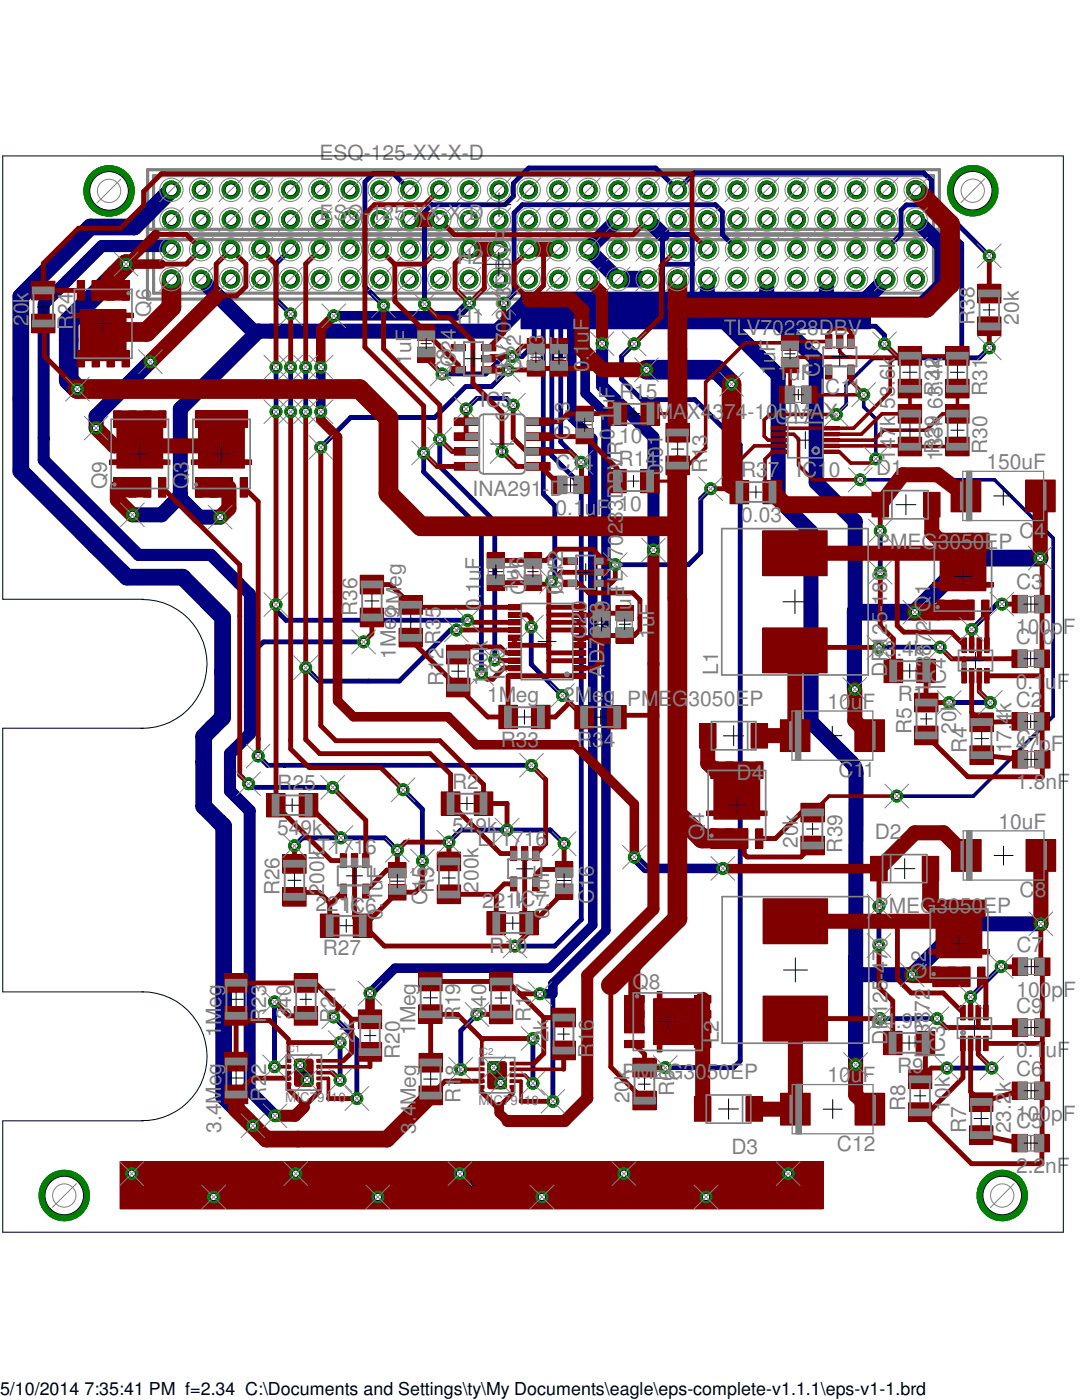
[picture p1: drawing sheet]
<svg xmlns="http://www.w3.org/2000/svg" width="216mm" height="279mm" viewBox="0 0 216 279" stroke-linecap="round" stroke-linejoin="round" font-family="sans-serif">
<defs><g id="words">
<g font-size="4.2" fill="#808080">
<text x="63.8" y="32">ESQ-125-XX-X-D</text>
<text x="63.8" y="43.8">ESQ-125-XX-X-D</text>
<text x="91.2" y="52.7">H2</text>
<text x="5.7" y="65.1" transform="rotate(-90 5.7 65.1)">20k</text>
<text x="14.6" y="66" transform="rotate(-90 14.6 66)">R24</text>
<text x="30.1" y="63.2" transform="rotate(-90 30.1 63.2)">Q6</text>
<text x="91.2" y="64.6">H1</text>
<text x="194.4" y="64.8" transform="rotate(-90 194.4 64.8)">R38</text>
<text x="203.3" y="64.8" transform="rotate(-90 203.3 64.8)">20k</text>
<text x="144.4" y="66.8">TLV70228DBV</text>
<text x="82" y="72.8" transform="rotate(-90 82 72.8)">1uF</text>
<text x="90" y="76.1" transform="rotate(-90 90 76.1)">IC8</text>
<text x="91" y="73.3" transform="rotate(-90 91 73.3)">C24</text>
<text x="101.9" y="76.1" transform="rotate(-90 101.9 76.1)">TLV70233DBVR</text>
<text x="104" y="74.3" transform="rotate(-90 104 74.3)">C22</text>
<text x="108.5" y="74.3" transform="rotate(-90 108.5 74.3)">C23</text>
<text x="112.9" y="74.3" transform="rotate(-90 112.9 74.3)">1uF</text>
<text x="117.5" y="74.3" transform="rotate(-90 117.5 74.3)">0.1uF</text>
<text x="154.6" y="74.8" transform="rotate(-90 154.6 74.8)">1uF</text>
<text x="155.1" y="75.8">1uF</text>
<text x="163.6" y="75.3" transform="rotate(-90 163.6 75.3)">C18</text>
<text x="95.8" y="81.2">IC5</text>
<text x="123.5" y="79.6">R15</text>
<text x="130.9" y="83.5">MAX4374-10UMAX</text>
<text x="163.5" y="78.7">IC11</text>
<text x="178.6" y="81.6" transform="rotate(-90 178.6 81.6)">53.6k</text>
<text x="187.5" y="79" transform="rotate(-90 187.5 79)">R32</text>
<text x="197" y="79" transform="rotate(-90 197 79)">R31</text>
<text x="113.7" y="87.8" transform="rotate(-90 113.7 87.8)">C13</text>
<text x="122.6" y="87.8" transform="rotate(-90 122.6 87.8)">0.1uF</text>
<text x="123.5" y="88.5">10</text>
<text x="154.6" y="84.7">C17</text>
<text x="110.8" y="93.8">C14</text>
<text x="123.4" y="93">R14</text>
<text x="132.2" y="94.8" transform="rotate(-90 132.2 94.8)">0.01</text>
<text x="141.1" y="94.3" transform="rotate(-90 141.1 94.3)">R13</text>
<text x="147.9" y="95.3">R37</text>
<text x="158.9" y="95.3">IC10</text>
<text x="174.8" y="94.8">D1</text>
<text x="178.6" y="92" transform="rotate(-90 178.6 92)">147k</text>
<text x="187.5" y="90.6" transform="rotate(-90 187.5 90.6)">R29</text>
<text x="188.1" y="92" transform="rotate(-90 188.1 92)">133k 63.4k</text>
<text x="196.8" y="93.6">150uF</text>
<text x="197" y="90.6" transform="rotate(-90 197 90.6)">R30</text>
<text x="21.3" y="97.6" transform="rotate(-90 21.3 97.6)">Q9</text>
<text x="37.6" y="97.6" transform="rotate(-90 37.6 97.6)">Q3</text>
<text x="94.3" y="99">INA291-D</text>
<text x="123.4" y="102">10</text>
<text x="110.8" y="102.7">0.1uF</text>
<text x="147.9" y="104.1">0.03</text>
<text x="203.4" y="107.3">C4</text>
<text x="174.8" y="109.6">PMEG3050EP</text>
<text x="103.4" y="118.3" transform="rotate(-90 103.4 118.3)">1uF</text>
<text x="104.9" y="118.8" transform="rotate(-90 104.9 118.8)">C26</text>
<text x="112.3" y="118.8" transform="rotate(-90 112.3 118.8)">C25</text>
<text x="112.4" y="118.7" transform="rotate(-90 112.4 118.7)">IC12</text>
<text x="124.3" y="118.7" transform="rotate(-90 124.3 118.7)">TLV70233DBVR</text>
<text x="202.7" y="117.6">C3</text>
<text x="71.2" y="122.9" transform="rotate(-90 71.2 122.9)">R36</text>
<text x="80.1" y="122.9" transform="rotate(-90 80.1 122.9)">2Meg</text>
<text x="96" y="121.8" transform="rotate(-90 96 121.8)">0.1uF</text>
<text x="185.6" y="122.1" transform="rotate(-90 185.6 122.1)">Q1</text>
<text x="79" y="131.4" transform="rotate(-90 79 131.4)">1Meg</text>
<text x="117" y="127.6" transform="rotate(-90 117 127.6)">C20</text>
<text x="121.6" y="127.6" transform="rotate(-90 121.6 127.6)">C19</text>
<text x="125.9" y="127.6" transform="rotate(-90 125.9 127.6)">0.1uF</text>
<text x="130.6" y="127.6" transform="rotate(-90 130.6 127.6)">1uF</text>
<text x="174.2" y="130.9">63.4k</text>
<text x="202.7" y="128.5">C10</text>
<text x="202.7" y="126.5">100pF</text>
<text x="88.5" y="136.9" transform="rotate(-90 88.5 136.9)">R12R35</text>
<text x="97.4" y="136.9" transform="rotate(-90 97.4 136.9)">100k</text>
<text x="100.7" y="135.8" transform="rotate(-90 100.7 135.8)">IC9</text>
<text x="120.6" y="135.3" transform="rotate(-90 120.6 135.3)">AD7998</text>
<text x="143.3" y="134.7" transform="rotate(-90 143.3 134.7)">L1</text>
<text x="177" y="135.1" transform="rotate(-90 177 135.1)">DR125-180</text>
<text x="185.7" y="137.8" transform="rotate(-90 185.7 137.8)">LT3872</text>
<text x="188.7" y="137.8" transform="rotate(-90 188.7 137.8)">IC4</text>
<text x="202.7" y="137.4">0.1uF</text>
<text x="97.2" y="140.1">1Meg</text>
<text x="112.4" y="140.1">2Meg</text>
<text x="125.1" y="140.9">PMEG3050EP</text>
<text x="165.1" y="141.4">10uF</text>
<text x="179.2" y="139.8">R1</text>
<text x="202.7" y="141">C2</text>
<text x="99.9" y="149.1">R33</text>
<text x="115.1" y="149.1">R34</text>
<text x="181.9" y="146.5" transform="rotate(-90 181.9 146.5)">R5</text>
<text x="190.8" y="146.5" transform="rotate(-90 190.8 146.5)">20k</text>
<text x="202.7" y="149.9">47pF</text>
<text x="202.8" y="148.6">C1</text>
<text x="147" y="155.7">D4</text>
<text x="167.3" y="155.2">C11</text>
<text x="192.9" y="150.4" transform="rotate(-90 192.9 150.4)">R4</text>
<text x="201.8" y="150.4" transform="rotate(-90 201.8 150.4)">17.4k</text>
<text x="55.3" y="157.7">R25</text>
<text x="90.2" y="157.4">R2</text>
<text x="202.8" y="157.5">1.8nF</text>
<text x="55.3" y="166.6">549k</text>
<text x="90.2" y="166.3">549k</text>
<text x="140.5" y="167.7" transform="rotate(-90 140.5 167.7)">Q4</text>
<text x="174.6" y="167.4">D2</text>
<text x="199.3" y="165.4">10uF</text>
<text x="61.3" y="170.3">LT1716</text>
<text x="95.3" y="168.9">LT1716</text>
<text x="159.2" y="169.2" transform="rotate(-90 159.2 169.2)">20k</text>
<text x="168.1" y="170.1" transform="rotate(-90 168.1 170.1)">R39</text>
<text x="55.8" y="178.7" transform="rotate(-90 55.8 178.7)">R26</text>
<text x="64.7" y="178.7" transform="rotate(-90 64.7 178.7)">200k</text>
<text x="86.6" y="178.2" transform="rotate(-90 86.6 178.2)">R3</text>
<text x="95.5" y="178.2" transform="rotate(-90 95.5 178.2)">200k</text>
<text x="203.5" y="179.1">C8</text>
<text x="62.9" y="181.8">221k</text>
<text x="68.7" y="182.2">IC6</text>
<text x="76.3" y="183.6" transform="rotate(-90 76.3 183.6)">0.1uF</text>
<text x="85.2" y="180.6" transform="rotate(-90 85.2 180.6)">C15</text>
<text x="96.2" y="181.2">221k</text>
<text x="102.7" y="180.8">IC7</text>
<text x="109.6" y="183.5" transform="rotate(-90 109.6 183.5)">0.1uF</text>
<text x="118.5" y="180.4" transform="rotate(-90 118.5 180.4)">C16</text>
<text x="174.6" y="182.3">PMEG3050EP</text>
<text x="64.4" y="190.7">R27</text>
<text x="97.6" y="190.2">R10</text>
<text x="202.8" y="189.9">C7</text>
<text x="126.2" y="197.4">Q8</text>
<text x="184.8" y="195.3" transform="rotate(-90 184.8 195.3)">Q2</text>
<text x="58.1" y="203.5" transform="rotate(-90 58.1 203.5)">340</text>
<text x="91.8" y="203.8" transform="rotate(-90 91.8 203.8)">R19</text>
<text x="97" y="203.2" transform="rotate(-90 97 203.2)">340</text>
<text x="105.9" y="203.9" transform="rotate(-90 105.9 203.9)">R17</text>
<text x="202.8" y="202.1">C9</text>
<text x="202.8" y="198.9">100pF</text>
<text x="44.2" y="206.9" transform="rotate(-90 44.2 206.9)">1Meg</text>
<text x="53.1" y="204.1" transform="rotate(-90 53.1 204.1)">R23</text>
<text x="67" y="204.1" transform="rotate(-90 67 204.1)">R21</text>
<text x="70.9" y="208.2" transform="rotate(-90 70.9 208.2)">2k</text>
<text x="82.9" y="206.6" transform="rotate(-90 82.9 206.6)">1Meg</text>
<text x="109.5" y="207.9" transform="rotate(-90 109.5 207.9)">2k</text>
<text x="143.4" y="208.2" transform="rotate(-90 143.4 208.2)">L2</text>
<text x="174.1" y="205.1">64.9k</text>
<text x="177.1" y="208.5" transform="rotate(-90 177.1 208.5)">DR125-470</text>
<text x="79.8" y="211.4" transform="rotate(-90 79.8 211.4)">R20</text>
<text x="118.4" y="211.1" transform="rotate(-90 118.4 211.1)">R16</text>
<text x="124.1" y="215.4">PMEG3050EP</text>
<text x="165.1" y="215.9">10uF</text>
<text x="179" y="214.1">R9</text>
<text x="185.5" y="211.1" transform="rotate(-90 185.5 211.1)">LT3872</text>
<text x="188.5" y="211.1" transform="rotate(-90 188.5 211.1)">IC3</text>
<text x="202.8" y="214.7">C6</text>
<text x="202.8" y="211">0.1uF</text>
<text x="53.1" y="219.8" transform="rotate(-90 53.1 219.8)">R22</text>
<text x="91.9" y="220" transform="rotate(-90 91.9 220)">R18</text>
<text x="125.6" y="220.2" transform="rotate(-90 125.6 220.2)">20k</text>
<text x="134.5" y="218.7" transform="rotate(-90 134.5 218.7)">R6</text>
<text x="180.6" y="221.7" transform="rotate(-90 180.6 221.7)">R8</text>
<text x="189.5" y="221.7" transform="rotate(-90 189.5 221.7)">10k</text>
<text x="44.2" y="226.1" transform="rotate(-90 44.2 226.1)">3.4Meg</text>
<text x="83" y="226.3" transform="rotate(-90 83 226.3)">3.4Meg</text>
<text x="192.8" y="226.2" transform="rotate(-90 192.8 226.2)">R7</text>
<text x="201.7" y="226.2" transform="rotate(-90 201.7 226.2)">23.2k</text>
<text x="202.7" y="225.2">C5</text>
<text x="202.8" y="223.6">100pF</text>
<text x="146" y="230.3">D3</text>
<text x="167" y="229.7">C12</text>
<text x="202.7" y="234.1">2.2nF</text>
</g>
<text font-size="3.6" x="0" y="278.4">5/10/2014 7:35:41 PM f=2.34 C:\Documents and Settings\ty\My Documents\eagle\eps-complete-v1.1.1\eps-v1-1.brd</text>
<g font-size="2.7" fill="#808080">
<text x="56.9" y="219.9">MIC79110</text>
<text x="95.5" y="220.4">MIC79110</text>
</g>
<g font-size="2" fill="#808080">
<text x="56.9" y="210">IC1</text>
<text x="95.5" y="210.5">IC2</text>
</g>
</g></defs>
<path d="M30.6 35.1h155.7v11.6h-155.7zM30.6 46.9h155.7v11.6h-155.7zM187.5 45.8h-158.1v13.9h158.1v-25.8h-158v13.9h158" fill="none" stroke="#808080" stroke-width=".63"/>
<path d="M104 58.3h69.7v7.3h-69.7z" fill-rule="evenodd" fill="#000080"/>
<path d="M104 58.3h69.7v7.3h-69.7z" fill="none" stroke="#000080" stroke-width=".2"/>
<g fill="none" stroke="#000080" stroke-width=".97">
<path d="M81.7 37.9l-3.3-3.3h-3.9l-1.7 1.7v20.9l3.7 3.8M58 49.7l-2.9 3v7l2.9 3M105.7 59.6v.9l.9 .9v7.3l-2.4 2.5h-3.7l-3.6 3.4h-8.7M119.7 58.8h-13.1l-1.4 1.3M123.3 55.6v.2M132.2 58.8v-12h5.9v12M132.2 52.7h6M138.1 58.8h-27.7l1.5 1.5v27.9l4.1 4M138.1 58.8l3.5 3.4h1M147.1 49.7l-3-2.9v-4.6l-1.4-1.3h-38.5l-1.6 1.6v16l-2.1 2M176.8 49.7l3-3v-4.7l1-1.1h3.4l7.7 7.7v22.8M197.4 51.1l-11.6-11.6v-3.5l-1.5-1.5h-45.7l-3.4 3.4-4.3-4.4h-25.4l-3.1 3.1v2.6l-1.6 1.7h-14.7l-1.4 1.4v18.4"/>
<path d="M55.1 73.3v8.9M58 73.3v8.9M61 73.3v8.9M93.7 60.5h.1M101.4 73.8l-3.3 3.3h-5.2l-6.2 6.2h-16.7l-6 6M106.6 63.9h3.5v27l5.9 5.9v86.7l-5.3 5.3h-8M108.4 63.9v34.7l2.3 2.3v14.5l-.6 .6M111.9 60.6h2l.3 .2h2.6M126.5 68.6l-2.5 2.5v4.6l4.1 4.1h10.5l9.1 9v123l-1.4 1.3h-13.5M142.8 62h11.8l1.8 1.8M164 60.7l4.4 4.4h6.3l1.8 1.8v1.7M191.9 71.4v.1"/>
<path d="M197.4 69.4l-2 2h-3.5M84.5 90.4v3.8l11.6 11.5v28.7M87.8 87.7v5.4l10.9 11v27.6M102.4 80.9l-1.4-1.4h-5.8l-2.2 2.1M141.8 97.5l-2 2v10.7l-2.4 2.5h-14.6M175.6 106v8.2M55.1 120.7v1.1l2 2h36.2M72.6 128.1h-20l-2.3 2.2h-.4M91.1 125.7h-1.2l-10.2 10.2h-16l-2.7-2.7M106 125.1v7.5l6.2 6.2M170.5 137.5l.1 .1M170.5 121.8h.1v.4"/>
<path d="M170.6 122.2h.1M173.7 122h-2.8l-.3 .2M187.6 129.2h-12.3M199.9 120.6h-1l-5 5M49.6 156.4l.7 .7h16.1M51.5 150.9l1.9 1.8h52.6M80.4 157.6l3.9 3.9v10.3M189.4 140.2h8.2M58.8 168.8l1.6-1.6h16.4l2.5 2.5M89.6 168.1l2.3-2.4h17.9l2.8 2.7M54.8 199.9v13M110.3 198.3v21.5"/>
<path d="M175.4 180.8v7.9M199.8 192.9l-6.1 6.1M66.6 202.9l4.6 4.7v11.6M67.9 208.1v7.5M95.2 202.4l-3.3 3.3v7.7M106.3 207.3v8.9M175.6 203.3h11.4M188.9 213.1h9"/>
</g>
<path d="M34.2 49.7l-.7-.6h-13.2l-11.6 11.6v31.1l18.9 18.9h14.5l7.8 7.9v27.8l-4 4v7.5l3.9 3.9v55.8l5.1 5.1M120.1 68.6v8.4l10.3 10.2v22.6" fill="none" stroke="#000080" stroke-width="2.4"/>
<g fill="none" stroke="#000080" stroke-width="3">
<path d="M40.1 55.7l10.4 10.4h48.7l6-6M123.3 43.8l-6 5.9 6 6.1M129.2 43.8l3 3M141.1 55.7v3.4l2.4 2.3M145.2 59.9l-.9 .8M153 55.7v4.2l.8 .8M164.9 55.7v4.8l.2 .2M176.8 55.7l-5 5M182.7 43.8l5.3 5.3v7.7l-3.9 3.9h-39.8M30 72.2l-10.8 10.9v2.3M51.6 66.1l-15.6 15.5v17.9l3.7 3.7h4.2M142.6 62.2l12.7 12.7v24.7l6.5 6.5v38l8.1 8.1a2.79 2.79 0 0 1 .9 2.1l-.1 58.2"/>
<path d="M142.6 62.2h10.7l9.6 9.6v24.5l7.7 7.8v17.7M143.5 61.4l-.9 .8M144.3 60.7l-.8 .7M36 98.9l-3.8 3.8h-5.8M170.5 121.8v15.7M207.7 184.4h-15.5l-10.2 10.1h-11.3"/>
</g>
<path d="M34.2 37.9l-7.4 7.4h-8.8l-13.9 13.9v34.8l21.2 21.2h11.1l8 8v20l-3.8 3.8v13.9l4 3.9v54l5.9 5.9M123.3 55.7h5.9M207.6 111.4h-14.3l-10.8 10.8h-11.9" fill="none" stroke="#000080" stroke-width="3.3"/>
<path d="M64 73.3v8.9M93.7 60.5l-2.6 2.5h-24.5M114.1 60.7v22.7l4.2 4.1v97.1l-8.6 8.6h-30.9l-5 5M116.8 60.8v17.7l4.1 4.1v103.1l-10.6 10.6v2h-2.6M126.6 171.1l2.2 2.2h15.4" fill="none" stroke="#000080" stroke-width="1.9"/>
<path d="M54.9 66l-.8 .1M172.3 78.8v2.4l2.5 2.4v8M191.9 71.5h-17.7l-5.4 5.4v3.9l-1.9 1.9M171.7 95.8h26.8l11.6 11.6v35.6l-15.9 15.9h-15.3" fill="none" stroke="#000080" stroke-width=".72"/>
<path d="M23 54.8l-9.3 9.3v11.8l1.8 1.7M23 54.8h.1M25.1 52.7l-2 2.1M129 73.8h14.1l2.9 2.9" fill="none" stroke="#000080" stroke-width="3.9"/>
<circle cx="34.2" cy="43.8" r="1.78" fill="#008000"/>
<circle cx="34.2" cy="43.8" r="1.78" fill="none" stroke="#008000" stroke-width=".2"/>
<circle cx="34.2" cy="43.8" r="1.18" fill="#fff"/>
<circle cx="34.2" cy="43.8" r="1.18" fill="none" stroke="#000" stroke-width=".2"/>
<circle cx="34.2" cy="37.9" r="1.78" fill="#008000"/>
<circle cx="34.2" cy="37.9" r="1.78" fill="none" stroke="#008000" stroke-width=".2"/>
<circle cx="34.2" cy="37.9" r="1.18" fill="#fff"/>
<circle cx="34.2" cy="37.9" r="1.18" fill="none" stroke="#000" stroke-width=".2"/>
<circle cx="40.1" cy="43.8" r="1.78" fill="#008000"/>
<circle cx="40.1" cy="43.8" r="1.78" fill="none" stroke="#008000" stroke-width=".2"/>
<circle cx="40.1" cy="43.8" r="1.18" fill="#fff"/>
<circle cx="40.1" cy="43.8" r="1.18" fill="none" stroke="#000" stroke-width=".2"/>
<circle cx="40.1" cy="37.9" r="1.78" fill="#008000"/>
<circle cx="40.1" cy="37.9" r="1.78" fill="none" stroke="#008000" stroke-width=".2"/>
<circle cx="40.1" cy="37.9" r="1.18" fill="#fff"/>
<circle cx="40.1" cy="37.9" r="1.18" fill="none" stroke="#000" stroke-width=".2"/>
<circle cx="46.1" cy="43.8" r="1.78" fill="#008000"/>
<circle cx="46.1" cy="43.8" r="1.78" fill="none" stroke="#008000" stroke-width=".2"/>
<circle cx="46.1" cy="43.8" r="1.18" fill="#fff"/>
<circle cx="46.1" cy="43.8" r="1.18" fill="none" stroke="#000" stroke-width=".2"/>
<circle cx="46.1" cy="37.9" r="1.78" fill="#008000"/>
<circle cx="46.1" cy="37.9" r="1.78" fill="none" stroke="#008000" stroke-width=".2"/>
<circle cx="46.1" cy="37.9" r="1.18" fill="#fff"/>
<circle cx="46.1" cy="37.9" r="1.18" fill="none" stroke="#000" stroke-width=".2"/>
<circle cx="52" cy="43.8" r="1.78" fill="#008000"/>
<circle cx="52" cy="43.8" r="1.78" fill="none" stroke="#008000" stroke-width=".2"/>
<circle cx="52" cy="43.8" r="1.18" fill="#fff"/>
<circle cx="52" cy="43.8" r="1.18" fill="none" stroke="#000" stroke-width=".2"/>
<circle cx="52" cy="37.9" r="1.78" fill="#008000"/>
<circle cx="52" cy="37.9" r="1.78" fill="none" stroke="#008000" stroke-width=".2"/>
<circle cx="52" cy="37.9" r="1.18" fill="#fff"/>
<circle cx="52" cy="37.9" r="1.18" fill="none" stroke="#000" stroke-width=".2"/>
<circle cx="58" cy="43.8" r="1.78" fill="#008000"/>
<circle cx="58" cy="43.8" r="1.78" fill="none" stroke="#008000" stroke-width=".2"/>
<circle cx="58" cy="43.8" r="1.18" fill="#fff"/>
<circle cx="58" cy="43.8" r="1.18" fill="none" stroke="#000" stroke-width=".2"/>
<circle cx="58" cy="37.9" r="1.78" fill="#008000"/>
<circle cx="58" cy="37.9" r="1.78" fill="none" stroke="#008000" stroke-width=".2"/>
<circle cx="58" cy="37.9" r="1.18" fill="#fff"/>
<circle cx="58" cy="37.9" r="1.18" fill="none" stroke="#000" stroke-width=".2"/>
<circle cx="63.9" cy="43.8" r="1.78" fill="#008000"/>
<circle cx="63.9" cy="43.8" r="1.78" fill="none" stroke="#008000" stroke-width=".2"/>
<circle cx="63.9" cy="43.8" r="1.18" fill="#fff"/>
<circle cx="63.9" cy="43.8" r="1.18" fill="none" stroke="#000" stroke-width=".2"/>
<circle cx="63.9" cy="37.9" r="1.78" fill="#008000"/>
<circle cx="63.9" cy="37.9" r="1.78" fill="none" stroke="#008000" stroke-width=".2"/>
<circle cx="63.9" cy="37.9" r="1.18" fill="#fff"/>
<circle cx="63.9" cy="37.9" r="1.18" fill="none" stroke="#000" stroke-width=".2"/>
<circle cx="69.9" cy="43.8" r="1.78" fill="#008000"/>
<circle cx="69.9" cy="43.8" r="1.78" fill="none" stroke="#008000" stroke-width=".2"/>
<circle cx="69.9" cy="43.8" r="1.18" fill="#fff"/>
<circle cx="69.9" cy="43.8" r="1.18" fill="none" stroke="#000" stroke-width=".2"/>
<circle cx="69.9" cy="37.9" r="1.78" fill="#008000"/>
<circle cx="69.9" cy="37.9" r="1.78" fill="none" stroke="#008000" stroke-width=".2"/>
<circle cx="69.9" cy="37.9" r="1.18" fill="#fff"/>
<circle cx="69.9" cy="37.9" r="1.18" fill="none" stroke="#000" stroke-width=".2"/>
<circle cx="75.8" cy="43.8" r="1.78" fill="#008000"/>
<circle cx="75.8" cy="43.8" r="1.78" fill="none" stroke="#008000" stroke-width=".2"/>
<circle cx="75.8" cy="43.8" r="1.18" fill="#fff"/>
<circle cx="75.8" cy="43.8" r="1.18" fill="none" stroke="#000" stroke-width=".2"/>
<circle cx="75.8" cy="37.9" r="1.78" fill="#008000"/>
<circle cx="75.8" cy="37.9" r="1.78" fill="none" stroke="#008000" stroke-width=".2"/>
<circle cx="75.8" cy="37.9" r="1.18" fill="#fff"/>
<circle cx="75.8" cy="37.9" r="1.18" fill="none" stroke="#000" stroke-width=".2"/>
<circle cx="81.7" cy="43.8" r="1.78" fill="#008000"/>
<circle cx="81.7" cy="43.8" r="1.78" fill="none" stroke="#008000" stroke-width=".2"/>
<circle cx="81.8" cy="43.8" r="1.18" fill="#fff"/>
<circle cx="81.8" cy="43.8" r="1.18" fill="none" stroke="#000" stroke-width=".2"/>
<circle cx="81.7" cy="37.9" r="1.78" fill="#008000"/>
<circle cx="81.7" cy="37.9" r="1.78" fill="none" stroke="#008000" stroke-width=".2"/>
<circle cx="81.8" cy="37.9" r="1.18" fill="#fff"/>
<circle cx="81.8" cy="37.9" r="1.18" fill="none" stroke="#000" stroke-width=".2"/>
<circle cx="87.7" cy="43.8" r="1.78" fill="#008000"/>
<circle cx="87.7" cy="43.8" r="1.78" fill="none" stroke="#008000" stroke-width=".2"/>
<circle cx="87.7" cy="43.8" r="1.18" fill="#fff"/>
<circle cx="87.7" cy="43.8" r="1.18" fill="none" stroke="#000" stroke-width=".2"/>
<circle cx="87.7" cy="37.9" r="1.78" fill="#008000"/>
<circle cx="87.7" cy="37.9" r="1.78" fill="none" stroke="#008000" stroke-width=".2"/>
<circle cx="87.7" cy="37.9" r="1.18" fill="#fff"/>
<circle cx="87.7" cy="37.9" r="1.18" fill="none" stroke="#000" stroke-width=".2"/>
<circle cx="93.6" cy="43.8" r="1.78" fill="#008000"/>
<circle cx="93.6" cy="43.8" r="1.78" fill="none" stroke="#008000" stroke-width=".2"/>
<circle cx="93.6" cy="43.8" r="1.18" fill="#fff"/>
<circle cx="93.6" cy="43.8" r="1.18" fill="none" stroke="#000" stroke-width=".2"/>
<circle cx="93.6" cy="37.9" r="1.78" fill="#008000"/>
<circle cx="93.6" cy="37.9" r="1.78" fill="none" stroke="#008000" stroke-width=".2"/>
<circle cx="93.6" cy="37.9" r="1.18" fill="#fff"/>
<circle cx="93.6" cy="37.9" r="1.18" fill="none" stroke="#000" stroke-width=".2"/>
<circle cx="99.6" cy="43.8" r="1.78" fill="#008000"/>
<circle cx="99.6" cy="43.8" r="1.78" fill="none" stroke="#008000" stroke-width=".2"/>
<circle cx="99.6" cy="43.8" r="1.18" fill="#fff"/>
<circle cx="99.6" cy="43.8" r="1.18" fill="none" stroke="#000" stroke-width=".2"/>
<circle cx="99.6" cy="37.9" r="1.78" fill="#008000"/>
<circle cx="99.6" cy="37.9" r="1.78" fill="none" stroke="#008000" stroke-width=".2"/>
<circle cx="99.6" cy="37.9" r="1.18" fill="#fff"/>
<circle cx="99.6" cy="37.9" r="1.18" fill="none" stroke="#000" stroke-width=".2"/>
<circle cx="105.5" cy="43.8" r="1.78" fill="#008000"/>
<circle cx="105.5" cy="43.8" r="1.78" fill="none" stroke="#008000" stroke-width=".2"/>
<circle cx="105.5" cy="43.8" r="1.18" fill="#fff"/>
<circle cx="105.5" cy="43.8" r="1.18" fill="none" stroke="#000" stroke-width=".2"/>
<circle cx="105.5" cy="37.9" r="1.78" fill="#008000"/>
<circle cx="105.5" cy="37.9" r="1.78" fill="none" stroke="#008000" stroke-width=".2"/>
<circle cx="105.5" cy="37.9" r="1.18" fill="#fff"/>
<circle cx="105.5" cy="37.9" r="1.18" fill="none" stroke="#000" stroke-width=".2"/>
<circle cx="111.4" cy="43.8" r="1.78" fill="#008000"/>
<circle cx="111.4" cy="43.8" r="1.78" fill="none" stroke="#008000" stroke-width=".2"/>
<circle cx="111.4" cy="43.8" r="1.18" fill="#fff"/>
<circle cx="111.4" cy="43.8" r="1.18" fill="none" stroke="#000" stroke-width=".2"/>
<circle cx="111.4" cy="37.9" r="1.78" fill="#008000"/>
<circle cx="111.4" cy="37.9" r="1.78" fill="none" stroke="#008000" stroke-width=".2"/>
<circle cx="111.4" cy="37.9" r="1.18" fill="#fff"/>
<circle cx="111.4" cy="37.9" r="1.18" fill="none" stroke="#000" stroke-width=".2"/>
<circle cx="117.4" cy="43.8" r="1.78" fill="#008000"/>
<circle cx="117.4" cy="43.8" r="1.78" fill="none" stroke="#008000" stroke-width=".2"/>
<circle cx="117.4" cy="43.8" r="1.18" fill="#fff"/>
<circle cx="117.4" cy="43.8" r="1.18" fill="none" stroke="#000" stroke-width=".2"/>
<circle cx="117.4" cy="37.9" r="1.78" fill="#008000"/>
<circle cx="117.4" cy="37.9" r="1.78" fill="none" stroke="#008000" stroke-width=".2"/>
<circle cx="117.4" cy="37.9" r="1.18" fill="#fff"/>
<circle cx="117.4" cy="37.9" r="1.18" fill="none" stroke="#000" stroke-width=".2"/>
<circle cx="123.3" cy="43.8" r="1.78" fill="#008000"/>
<circle cx="123.3" cy="43.8" r="1.78" fill="none" stroke="#008000" stroke-width=".2"/>
<circle cx="123.3" cy="43.8" r="1.18" fill="#fff"/>
<circle cx="123.3" cy="43.8" r="1.18" fill="none" stroke="#000" stroke-width=".2"/>
<circle cx="123.3" cy="37.9" r="1.78" fill="#008000"/>
<circle cx="123.3" cy="37.9" r="1.78" fill="none" stroke="#008000" stroke-width=".2"/>
<circle cx="123.3" cy="37.9" r="1.18" fill="#fff"/>
<circle cx="123.3" cy="37.9" r="1.18" fill="none" stroke="#000" stroke-width=".2"/>
<circle cx="129.2" cy="43.8" r="1.78" fill="#008000"/>
<circle cx="129.2" cy="43.8" r="1.78" fill="none" stroke="#008000" stroke-width=".2"/>
<circle cx="129.2" cy="43.8" r="1.18" fill="#fff"/>
<circle cx="129.2" cy="43.8" r="1.18" fill="none" stroke="#000" stroke-width=".2"/>
<circle cx="129.2" cy="37.9" r="1.78" fill="#008000"/>
<circle cx="129.2" cy="37.9" r="1.78" fill="none" stroke="#008000" stroke-width=".2"/>
<circle cx="129.2" cy="37.9" r="1.18" fill="#fff"/>
<circle cx="129.2" cy="37.9" r="1.18" fill="none" stroke="#000" stroke-width=".2"/>
<circle cx="135.2" cy="43.8" r="1.78" fill="#008000"/>
<circle cx="135.2" cy="43.8" r="1.78" fill="none" stroke="#008000" stroke-width=".2"/>
<circle cx="135.2" cy="43.8" r="1.18" fill="#fff"/>
<circle cx="135.2" cy="43.8" r="1.18" fill="none" stroke="#000" stroke-width=".2"/>
<circle cx="135.2" cy="37.9" r="1.78" fill="#008000"/>
<circle cx="135.2" cy="37.9" r="1.78" fill="none" stroke="#008000" stroke-width=".2"/>
<circle cx="135.2" cy="37.9" r="1.18" fill="#fff"/>
<circle cx="135.2" cy="37.9" r="1.18" fill="none" stroke="#000" stroke-width=".2"/>
<circle cx="141.1" cy="43.8" r="1.78" fill="#008000"/>
<circle cx="141.1" cy="43.8" r="1.78" fill="none" stroke="#008000" stroke-width=".2"/>
<circle cx="141.1" cy="43.8" r="1.18" fill="#fff"/>
<circle cx="141.1" cy="43.8" r="1.18" fill="none" stroke="#000" stroke-width=".2"/>
<circle cx="141.1" cy="37.9" r="1.78" fill="#008000"/>
<circle cx="141.1" cy="37.9" r="1.78" fill="none" stroke="#008000" stroke-width=".2"/>
<circle cx="141.1" cy="37.9" r="1.18" fill="#fff"/>
<circle cx="141.1" cy="37.9" r="1.18" fill="none" stroke="#000" stroke-width=".2"/>
<circle cx="147.1" cy="43.8" r="1.78" fill="#008000"/>
<circle cx="147.1" cy="43.8" r="1.78" fill="none" stroke="#008000" stroke-width=".2"/>
<circle cx="147.1" cy="43.8" r="1.18" fill="#fff"/>
<circle cx="147.1" cy="43.8" r="1.18" fill="none" stroke="#000" stroke-width=".2"/>
<circle cx="147.1" cy="37.9" r="1.78" fill="#008000"/>
<circle cx="147.1" cy="37.9" r="1.78" fill="none" stroke="#008000" stroke-width=".2"/>
<circle cx="147.1" cy="37.9" r="1.18" fill="#fff"/>
<circle cx="147.1" cy="37.9" r="1.18" fill="none" stroke="#000" stroke-width=".2"/>
<circle cx="153" cy="43.8" r="1.78" fill="#008000"/>
<circle cx="153" cy="43.8" r="1.78" fill="none" stroke="#008000" stroke-width=".2"/>
<circle cx="153" cy="43.8" r="1.18" fill="#fff"/>
<circle cx="153" cy="43.8" r="1.18" fill="none" stroke="#000" stroke-width=".2"/>
<circle cx="153" cy="37.9" r="1.78" fill="#008000"/>
<circle cx="153" cy="37.9" r="1.78" fill="none" stroke="#008000" stroke-width=".2"/>
<circle cx="153" cy="37.9" r="1.18" fill="#fff"/>
<circle cx="153" cy="37.9" r="1.18" fill="none" stroke="#000" stroke-width=".2"/>
<circle cx="159" cy="43.8" r="1.78" fill="#008000"/>
<circle cx="159" cy="43.8" r="1.78" fill="none" stroke="#008000" stroke-width=".2"/>
<circle cx="159" cy="43.8" r="1.18" fill="#fff"/>
<circle cx="159" cy="43.8" r="1.18" fill="none" stroke="#000" stroke-width=".2"/>
<circle cx="159" cy="37.9" r="1.78" fill="#008000"/>
<circle cx="159" cy="37.9" r="1.78" fill="none" stroke="#008000" stroke-width=".2"/>
<circle cx="159" cy="37.9" r="1.18" fill="#fff"/>
<circle cx="159" cy="37.9" r="1.18" fill="none" stroke="#000" stroke-width=".2"/>
<circle cx="164.9" cy="43.8" r="1.78" fill="#008000"/>
<circle cx="164.9" cy="43.8" r="1.78" fill="none" stroke="#008000" stroke-width=".2"/>
<circle cx="164.9" cy="43.8" r="1.18" fill="#fff"/>
<circle cx="164.9" cy="43.8" r="1.18" fill="none" stroke="#000" stroke-width=".2"/>
<circle cx="164.9" cy="37.9" r="1.78" fill="#008000"/>
<circle cx="164.9" cy="37.9" r="1.78" fill="none" stroke="#008000" stroke-width=".2"/>
<circle cx="164.9" cy="37.9" r="1.18" fill="#fff"/>
<circle cx="164.9" cy="37.9" r="1.18" fill="none" stroke="#000" stroke-width=".2"/>
<circle cx="170.9" cy="43.8" r="1.78" fill="#008000"/>
<circle cx="170.9" cy="43.8" r="1.78" fill="none" stroke="#008000" stroke-width=".2"/>
<circle cx="170.9" cy="43.8" r="1.18" fill="#fff"/>
<circle cx="170.9" cy="43.8" r="1.18" fill="none" stroke="#000" stroke-width=".2"/>
<circle cx="170.9" cy="37.9" r="1.78" fill="#008000"/>
<circle cx="170.9" cy="37.9" r="1.78" fill="none" stroke="#008000" stroke-width=".2"/>
<circle cx="170.9" cy="37.9" r="1.18" fill="#fff"/>
<circle cx="170.9" cy="37.9" r="1.18" fill="none" stroke="#000" stroke-width=".2"/>
<circle cx="176.8" cy="43.8" r="1.78" fill="#008000"/>
<circle cx="176.8" cy="43.8" r="1.78" fill="none" stroke="#008000" stroke-width=".2"/>
<circle cx="176.8" cy="43.8" r="1.18" fill="#fff"/>
<circle cx="176.8" cy="43.8" r="1.18" fill="none" stroke="#000" stroke-width=".2"/>
<circle cx="176.8" cy="37.9" r="1.78" fill="#008000"/>
<circle cx="176.8" cy="37.9" r="1.78" fill="none" stroke="#008000" stroke-width=".2"/>
<circle cx="176.8" cy="37.9" r="1.18" fill="#fff"/>
<circle cx="176.8" cy="37.9" r="1.18" fill="none" stroke="#000" stroke-width=".2"/>
<circle cx="182.7" cy="43.8" r="1.78" fill="#008000"/>
<circle cx="182.7" cy="43.8" r="1.78" fill="none" stroke="#008000" stroke-width=".2"/>
<circle cx="182.7" cy="43.8" r="1.18" fill="#fff"/>
<circle cx="182.7" cy="43.8" r="1.18" fill="none" stroke="#000" stroke-width=".2"/>
<circle cx="182.7" cy="37.9" r="1.78" fill="#008000"/>
<circle cx="182.7" cy="37.9" r="1.78" fill="none" stroke="#008000" stroke-width=".2"/>
<circle cx="182.7" cy="37.9" r="1.18" fill="#fff"/>
<circle cx="182.7" cy="37.9" r="1.18" fill="none" stroke="#000" stroke-width=".2"/>
<circle cx="34.2" cy="55.7" r="1.78" fill="#008000"/>
<circle cx="34.2" cy="55.7" r="1.78" fill="none" stroke="#008000" stroke-width=".2"/>
<circle cx="34.2" cy="55.7" r="1.18" fill="#fff"/>
<circle cx="34.2" cy="55.7" r="1.18" fill="none" stroke="#000" stroke-width=".2"/>
<circle cx="34.2" cy="49.7" r="1.78" fill="#008000"/>
<circle cx="34.2" cy="49.7" r="1.78" fill="none" stroke="#008000" stroke-width=".2"/>
<circle cx="34.2" cy="49.7" r="1.18" fill="#fff"/>
<circle cx="34.2" cy="49.7" r="1.18" fill="none" stroke="#000" stroke-width=".2"/>
<circle cx="40.1" cy="55.7" r="1.78" fill="#008000"/>
<circle cx="40.1" cy="55.7" r="1.78" fill="none" stroke="#008000" stroke-width=".2"/>
<circle cx="40.1" cy="55.7" r="1.18" fill="#fff"/>
<circle cx="40.1" cy="55.7" r="1.18" fill="none" stroke="#000" stroke-width=".2"/>
<circle cx="40.1" cy="49.7" r="1.78" fill="#008000"/>
<circle cx="40.1" cy="49.7" r="1.78" fill="none" stroke="#008000" stroke-width=".2"/>
<circle cx="40.1" cy="49.7" r="1.18" fill="#fff"/>
<circle cx="40.1" cy="49.7" r="1.18" fill="none" stroke="#000" stroke-width=".2"/>
<circle cx="46.1" cy="55.7" r="1.78" fill="#008000"/>
<circle cx="46.1" cy="55.7" r="1.78" fill="none" stroke="#008000" stroke-width=".2"/>
<circle cx="46.1" cy="55.7" r="1.18" fill="#fff"/>
<circle cx="46.1" cy="55.7" r="1.18" fill="none" stroke="#000" stroke-width=".2"/>
<circle cx="46.1" cy="49.7" r="1.78" fill="#008000"/>
<circle cx="46.1" cy="49.7" r="1.78" fill="none" stroke="#008000" stroke-width=".2"/>
<circle cx="46.1" cy="49.7" r="1.18" fill="#fff"/>
<circle cx="46.1" cy="49.7" r="1.18" fill="none" stroke="#000" stroke-width=".2"/>
<circle cx="52" cy="55.7" r="1.78" fill="#008000"/>
<circle cx="52" cy="55.7" r="1.78" fill="none" stroke="#008000" stroke-width=".2"/>
<circle cx="52" cy="55.7" r="1.18" fill="#fff"/>
<circle cx="52" cy="55.7" r="1.18" fill="none" stroke="#000" stroke-width=".2"/>
<circle cx="52" cy="49.7" r="1.78" fill="#008000"/>
<circle cx="52" cy="49.7" r="1.78" fill="none" stroke="#008000" stroke-width=".2"/>
<circle cx="52" cy="49.7" r="1.18" fill="#fff"/>
<circle cx="52" cy="49.7" r="1.18" fill="none" stroke="#000" stroke-width=".2"/>
<circle cx="58" cy="55.7" r="1.78" fill="#008000"/>
<circle cx="58" cy="55.7" r="1.78" fill="none" stroke="#008000" stroke-width=".2"/>
<circle cx="58" cy="55.7" r="1.18" fill="#fff"/>
<circle cx="58" cy="55.7" r="1.18" fill="none" stroke="#000" stroke-width=".2"/>
<circle cx="58" cy="49.7" r="1.78" fill="#008000"/>
<circle cx="58" cy="49.7" r="1.78" fill="none" stroke="#008000" stroke-width=".2"/>
<circle cx="58" cy="49.7" r="1.18" fill="#fff"/>
<circle cx="58" cy="49.7" r="1.18" fill="none" stroke="#000" stroke-width=".2"/>
<circle cx="63.9" cy="55.7" r="1.78" fill="#008000"/>
<circle cx="63.9" cy="55.7" r="1.78" fill="none" stroke="#008000" stroke-width=".2"/>
<circle cx="63.9" cy="55.7" r="1.18" fill="#fff"/>
<circle cx="63.9" cy="55.7" r="1.18" fill="none" stroke="#000" stroke-width=".2"/>
<circle cx="63.9" cy="49.7" r="1.78" fill="#008000"/>
<circle cx="63.9" cy="49.7" r="1.78" fill="none" stroke="#008000" stroke-width=".2"/>
<circle cx="63.9" cy="49.7" r="1.18" fill="#fff"/>
<circle cx="63.9" cy="49.7" r="1.18" fill="none" stroke="#000" stroke-width=".2"/>
<circle cx="69.9" cy="55.7" r="1.78" fill="#008000"/>
<circle cx="69.9" cy="55.7" r="1.78" fill="none" stroke="#008000" stroke-width=".2"/>
<circle cx="69.9" cy="55.7" r="1.18" fill="#fff"/>
<circle cx="69.9" cy="55.7" r="1.18" fill="none" stroke="#000" stroke-width=".2"/>
<circle cx="69.9" cy="49.7" r="1.78" fill="#008000"/>
<circle cx="69.9" cy="49.7" r="1.78" fill="none" stroke="#008000" stroke-width=".2"/>
<circle cx="69.9" cy="49.7" r="1.18" fill="#fff"/>
<circle cx="69.9" cy="49.7" r="1.18" fill="none" stroke="#000" stroke-width=".2"/>
<circle cx="75.8" cy="55.7" r="1.78" fill="#008000"/>
<circle cx="75.8" cy="55.7" r="1.78" fill="none" stroke="#008000" stroke-width=".2"/>
<circle cx="75.8" cy="55.7" r="1.18" fill="#fff"/>
<circle cx="75.8" cy="55.7" r="1.18" fill="none" stroke="#000" stroke-width=".2"/>
<circle cx="75.8" cy="49.7" r="1.78" fill="#008000"/>
<circle cx="75.8" cy="49.7" r="1.78" fill="none" stroke="#008000" stroke-width=".2"/>
<circle cx="75.8" cy="49.7" r="1.18" fill="#fff"/>
<circle cx="75.8" cy="49.7" r="1.18" fill="none" stroke="#000" stroke-width=".2"/>
<circle cx="81.7" cy="55.7" r="1.78" fill="#008000"/>
<circle cx="81.7" cy="55.7" r="1.78" fill="none" stroke="#008000" stroke-width=".2"/>
<circle cx="81.7" cy="55.7" r="1.18" fill="#fff"/>
<circle cx="81.7" cy="55.7" r="1.18" fill="none" stroke="#000" stroke-width=".2"/>
<circle cx="81.7" cy="49.7" r="1.78" fill="#008000"/>
<circle cx="81.7" cy="49.7" r="1.78" fill="none" stroke="#008000" stroke-width=".2"/>
<circle cx="81.7" cy="49.7" r="1.18" fill="#fff"/>
<circle cx="81.7" cy="49.7" r="1.18" fill="none" stroke="#000" stroke-width=".2"/>
<circle cx="87.7" cy="55.7" r="1.78" fill="#008000"/>
<circle cx="87.7" cy="55.7" r="1.78" fill="none" stroke="#008000" stroke-width=".2"/>
<circle cx="87.7" cy="55.7" r="1.18" fill="#fff"/>
<circle cx="87.7" cy="55.7" r="1.18" fill="none" stroke="#000" stroke-width=".2"/>
<circle cx="87.7" cy="49.7" r="1.78" fill="#008000"/>
<circle cx="87.7" cy="49.7" r="1.78" fill="none" stroke="#008000" stroke-width=".2"/>
<circle cx="87.7" cy="49.7" r="1.18" fill="#fff"/>
<circle cx="87.7" cy="49.7" r="1.18" fill="none" stroke="#000" stroke-width=".2"/>
<circle cx="93.6" cy="55.7" r="1.78" fill="#008000"/>
<circle cx="93.6" cy="55.7" r="1.78" fill="none" stroke="#008000" stroke-width=".2"/>
<circle cx="93.6" cy="55.7" r="1.18" fill="#fff"/>
<circle cx="93.6" cy="55.7" r="1.18" fill="none" stroke="#000" stroke-width=".2"/>
<circle cx="93.6" cy="49.7" r="1.78" fill="#008000"/>
<circle cx="93.6" cy="49.7" r="1.78" fill="none" stroke="#008000" stroke-width=".2"/>
<circle cx="93.6" cy="49.7" r="1.18" fill="#fff"/>
<circle cx="93.6" cy="49.7" r="1.18" fill="none" stroke="#000" stroke-width=".2"/>
<circle cx="99.5" cy="55.7" r="1.78" fill="#008000"/>
<circle cx="99.5" cy="55.7" r="1.78" fill="none" stroke="#008000" stroke-width=".2"/>
<circle cx="99.5" cy="55.7" r="1.18" fill="#fff"/>
<circle cx="99.5" cy="55.7" r="1.18" fill="none" stroke="#000" stroke-width=".2"/>
<circle cx="99.5" cy="49.7" r="1.78" fill="#008000"/>
<circle cx="99.5" cy="49.7" r="1.78" fill="none" stroke="#008000" stroke-width=".2"/>
<circle cx="99.5" cy="49.7" r="1.18" fill="#fff"/>
<circle cx="99.5" cy="49.7" r="1.18" fill="none" stroke="#000" stroke-width=".2"/>
<circle cx="105.5" cy="55.7" r="1.78" fill="#008000"/>
<circle cx="105.5" cy="55.7" r="1.78" fill="none" stroke="#008000" stroke-width=".2"/>
<circle cx="105.5" cy="55.7" r="1.18" fill="#fff"/>
<circle cx="105.5" cy="55.7" r="1.18" fill="none" stroke="#000" stroke-width=".2"/>
<circle cx="105.5" cy="49.7" r="1.78" fill="#008000"/>
<circle cx="105.5" cy="49.7" r="1.78" fill="none" stroke="#008000" stroke-width=".2"/>
<circle cx="105.5" cy="49.7" r="1.18" fill="#fff"/>
<circle cx="105.5" cy="49.7" r="1.18" fill="none" stroke="#000" stroke-width=".2"/>
<circle cx="111.4" cy="55.7" r="1.78" fill="#008000"/>
<circle cx="111.4" cy="55.7" r="1.78" fill="none" stroke="#008000" stroke-width=".2"/>
<circle cx="111.4" cy="55.7" r="1.18" fill="#fff"/>
<circle cx="111.4" cy="55.7" r="1.18" fill="none" stroke="#000" stroke-width=".2"/>
<circle cx="111.4" cy="49.7" r="1.78" fill="#008000"/>
<circle cx="111.4" cy="49.7" r="1.78" fill="none" stroke="#008000" stroke-width=".2"/>
<circle cx="111.4" cy="49.7" r="1.18" fill="#fff"/>
<circle cx="111.4" cy="49.7" r="1.18" fill="none" stroke="#000" stroke-width=".2"/>
<circle cx="117.4" cy="55.7" r="1.78" fill="#008000"/>
<circle cx="117.4" cy="55.7" r="1.78" fill="none" stroke="#008000" stroke-width=".2"/>
<circle cx="117.4" cy="55.7" r="1.18" fill="#fff"/>
<circle cx="117.4" cy="55.7" r="1.18" fill="none" stroke="#000" stroke-width=".2"/>
<circle cx="117.4" cy="49.7" r="1.78" fill="#008000"/>
<circle cx="117.4" cy="49.7" r="1.78" fill="none" stroke="#008000" stroke-width=".2"/>
<circle cx="117.4" cy="49.7" r="1.18" fill="#fff"/>
<circle cx="117.4" cy="49.7" r="1.18" fill="none" stroke="#000" stroke-width=".2"/>
<circle cx="123.3" cy="55.7" r="1.78" fill="#008000"/>
<circle cx="123.3" cy="55.7" r="1.78" fill="none" stroke="#008000" stroke-width=".2"/>
<circle cx="123.3" cy="55.7" r="1.18" fill="#fff"/>
<circle cx="123.3" cy="55.7" r="1.18" fill="none" stroke="#000" stroke-width=".2"/>
<circle cx="123.3" cy="49.7" r="1.78" fill="#008000"/>
<circle cx="123.3" cy="49.7" r="1.78" fill="none" stroke="#008000" stroke-width=".2"/>
<circle cx="123.3" cy="49.7" r="1.18" fill="#fff"/>
<circle cx="123.3" cy="49.7" r="1.18" fill="none" stroke="#000" stroke-width=".2"/>
<circle cx="129.2" cy="55.7" r="1.78" fill="#008000"/>
<circle cx="129.2" cy="55.7" r="1.78" fill="none" stroke="#008000" stroke-width=".2"/>
<circle cx="129.2" cy="55.7" r="1.18" fill="#fff"/>
<circle cx="129.2" cy="55.7" r="1.18" fill="none" stroke="#000" stroke-width=".2"/>
<circle cx="129.2" cy="49.7" r="1.78" fill="#008000"/>
<circle cx="129.2" cy="49.7" r="1.78" fill="none" stroke="#008000" stroke-width=".2"/>
<circle cx="129.2" cy="49.7" r="1.18" fill="#fff"/>
<circle cx="129.2" cy="49.7" r="1.18" fill="none" stroke="#000" stroke-width=".2"/>
<circle cx="135.2" cy="55.7" r="1.78" fill="#008000"/>
<circle cx="135.2" cy="55.7" r="1.78" fill="none" stroke="#008000" stroke-width=".2"/>
<circle cx="135.2" cy="55.7" r="1.18" fill="#fff"/>
<circle cx="135.2" cy="55.7" r="1.18" fill="none" stroke="#000" stroke-width=".2"/>
<circle cx="135.2" cy="49.7" r="1.78" fill="#008000"/>
<circle cx="135.2" cy="49.7" r="1.78" fill="none" stroke="#008000" stroke-width=".2"/>
<circle cx="135.2" cy="49.7" r="1.18" fill="#fff"/>
<circle cx="135.2" cy="49.7" r="1.18" fill="none" stroke="#000" stroke-width=".2"/>
<circle cx="141.1" cy="55.7" r="1.78" fill="#008000"/>
<circle cx="141.1" cy="55.7" r="1.78" fill="none" stroke="#008000" stroke-width=".2"/>
<circle cx="141.1" cy="55.7" r="1.18" fill="#fff"/>
<circle cx="141.1" cy="55.7" r="1.18" fill="none" stroke="#000" stroke-width=".2"/>
<circle cx="141.1" cy="49.7" r="1.78" fill="#008000"/>
<circle cx="141.1" cy="49.7" r="1.78" fill="none" stroke="#008000" stroke-width=".2"/>
<circle cx="141.1" cy="49.7" r="1.18" fill="#fff"/>
<circle cx="141.1" cy="49.7" r="1.18" fill="none" stroke="#000" stroke-width=".2"/>
<circle cx="147.1" cy="55.7" r="1.78" fill="#008000"/>
<circle cx="147.1" cy="55.7" r="1.78" fill="none" stroke="#008000" stroke-width=".2"/>
<circle cx="147.1" cy="55.7" r="1.18" fill="#fff"/>
<circle cx="147.1" cy="55.7" r="1.18" fill="none" stroke="#000" stroke-width=".2"/>
<circle cx="147.1" cy="49.7" r="1.78" fill="#008000"/>
<circle cx="147.1" cy="49.7" r="1.78" fill="none" stroke="#008000" stroke-width=".2"/>
<circle cx="147.1" cy="49.7" r="1.18" fill="#fff"/>
<circle cx="147.1" cy="49.7" r="1.18" fill="none" stroke="#000" stroke-width=".2"/>
<circle cx="153" cy="55.7" r="1.78" fill="#008000"/>
<circle cx="153" cy="55.7" r="1.78" fill="none" stroke="#008000" stroke-width=".2"/>
<circle cx="153" cy="55.7" r="1.18" fill="#fff"/>
<circle cx="153" cy="55.7" r="1.18" fill="none" stroke="#000" stroke-width=".2"/>
<circle cx="153" cy="49.7" r="1.78" fill="#008000"/>
<circle cx="153" cy="49.7" r="1.78" fill="none" stroke="#008000" stroke-width=".2"/>
<circle cx="153" cy="49.7" r="1.18" fill="#fff"/>
<circle cx="153" cy="49.7" r="1.18" fill="none" stroke="#000" stroke-width=".2"/>
<circle cx="159" cy="55.7" r="1.78" fill="#008000"/>
<circle cx="159" cy="55.7" r="1.78" fill="none" stroke="#008000" stroke-width=".2"/>
<circle cx="159" cy="55.7" r="1.18" fill="#fff"/>
<circle cx="159" cy="55.7" r="1.18" fill="none" stroke="#000" stroke-width=".2"/>
<circle cx="159" cy="49.7" r="1.78" fill="#008000"/>
<circle cx="159" cy="49.7" r="1.78" fill="none" stroke="#008000" stroke-width=".2"/>
<circle cx="159" cy="49.7" r="1.18" fill="#fff"/>
<circle cx="159" cy="49.7" r="1.18" fill="none" stroke="#000" stroke-width=".2"/>
<circle cx="164.9" cy="55.7" r="1.78" fill="#008000"/>
<circle cx="164.9" cy="55.7" r="1.78" fill="none" stroke="#008000" stroke-width=".2"/>
<circle cx="164.9" cy="55.7" r="1.18" fill="#fff"/>
<circle cx="164.9" cy="55.7" r="1.18" fill="none" stroke="#000" stroke-width=".2"/>
<circle cx="164.9" cy="49.7" r="1.78" fill="#008000"/>
<circle cx="164.9" cy="49.7" r="1.78" fill="none" stroke="#008000" stroke-width=".2"/>
<circle cx="164.9" cy="49.7" r="1.18" fill="#fff"/>
<circle cx="164.9" cy="49.7" r="1.18" fill="none" stroke="#000" stroke-width=".2"/>
<circle cx="170.8" cy="55.7" r="1.78" fill="#008000"/>
<circle cx="170.8" cy="55.7" r="1.78" fill="none" stroke="#008000" stroke-width=".2"/>
<circle cx="170.8" cy="55.7" r="1.18" fill="#fff"/>
<circle cx="170.8" cy="55.7" r="1.18" fill="none" stroke="#000" stroke-width=".2"/>
<circle cx="170.8" cy="49.7" r="1.78" fill="#008000"/>
<circle cx="170.8" cy="49.7" r="1.78" fill="none" stroke="#008000" stroke-width=".2"/>
<circle cx="170.8" cy="49.7" r="1.18" fill="#fff"/>
<circle cx="170.8" cy="49.7" r="1.18" fill="none" stroke="#000" stroke-width=".2"/>
<circle cx="176.8" cy="55.7" r="1.78" fill="#008000"/>
<circle cx="176.8" cy="55.7" r="1.78" fill="none" stroke="#008000" stroke-width=".2"/>
<circle cx="176.8" cy="55.7" r="1.18" fill="#fff"/>
<circle cx="176.8" cy="55.7" r="1.18" fill="none" stroke="#000" stroke-width=".2"/>
<circle cx="176.8" cy="49.7" r="1.78" fill="#008000"/>
<circle cx="176.8" cy="49.7" r="1.78" fill="none" stroke="#008000" stroke-width=".2"/>
<circle cx="176.8" cy="49.7" r="1.18" fill="#fff"/>
<circle cx="176.8" cy="49.7" r="1.18" fill="none" stroke="#000" stroke-width=".2"/>
<circle cx="182.7" cy="55.7" r="1.78" fill="#008000"/>
<circle cx="182.7" cy="55.7" r="1.78" fill="none" stroke="#008000" stroke-width=".2"/>
<circle cx="182.7" cy="55.7" r="1.18" fill="#fff"/>
<circle cx="182.7" cy="55.7" r="1.18" fill="none" stroke="#000" stroke-width=".2"/>
<circle cx="182.7" cy="49.7" r="1.78" fill="#008000"/>
<circle cx="182.7" cy="49.7" r="1.78" fill="none" stroke="#008000" stroke-width=".2"/>
<circle cx="182.7" cy="49.7" r="1.18" fill="#fff"/>
<circle cx="182.7" cy="49.7" r="1.18" fill="none" stroke="#000" stroke-width=".2"/>
<circle cx="197.6" cy="140.2" r="1.18" fill="#008000"/>
<circle cx="197.6" cy="140.2" r="1.18" fill="none" stroke="#008000" stroke-width=".2"/>
<circle cx="197.6" cy="140.2" r=".72" fill="#fff"/>
<circle cx="197.6" cy="140.2" r=".72" fill="none" stroke="#000" stroke-width=".2"/>
<circle cx="189.4" cy="140.2" r="1.18" fill="#008000"/>
<circle cx="189.4" cy="140.2" r="1.18" fill="none" stroke="#008000" stroke-width=".2"/>
<circle cx="189.4" cy="140.2" r=".72" fill="#fff"/>
<circle cx="189.4" cy="140.2" r=".72" fill="none" stroke="#000" stroke-width=".2"/>
<circle cx="193.7" cy="199" r="1.18" fill="#008000"/>
<circle cx="193.7" cy="199" r="1.18" fill="none" stroke="#008000" stroke-width=".2"/>
<circle cx="193.7" cy="199" r=".72" fill="#fff"/>
<circle cx="193.7" cy="199" r=".72" fill="none" stroke="#000" stroke-width=".2"/>
<circle cx="199.8" cy="192.9" r="1.18" fill="#008000"/>
<circle cx="199.8" cy="192.9" r="1.18" fill="none" stroke="#008000" stroke-width=".2"/>
<circle cx="199.8" cy="192.9" r=".72" fill="#fff"/>
<circle cx="199.8" cy="192.9" r=".72" fill="none" stroke="#000" stroke-width=".2"/>
<circle cx="197.9" cy="213.2" r="1.18" fill="#008000"/>
<circle cx="197.9" cy="213.2" r="1.18" fill="none" stroke="#008000" stroke-width=".2"/>
<circle cx="197.9" cy="213.1" r=".72" fill="#fff"/>
<circle cx="197.9" cy="213.1" r=".72" fill="none" stroke="#000" stroke-width=".2"/>
<circle cx="188.9" cy="213.2" r="1.18" fill="#008000"/>
<circle cx="188.9" cy="213.2" r="1.18" fill="none" stroke="#008000" stroke-width=".2"/>
<circle cx="188.9" cy="213.1" r=".72" fill="#fff"/>
<circle cx="188.9" cy="213.1" r=".72" fill="none" stroke="#000" stroke-width=".2"/>
<circle cx="175.6" cy="203.3" r="1.18" fill="#008000"/>
<circle cx="175.6" cy="203.3" r="1.18" fill="none" stroke="#008000" stroke-width=".2"/>
<circle cx="175.6" cy="203.3" r=".72" fill="#fff"/>
<circle cx="175.6" cy="203.3" r=".72" fill="none" stroke="#000" stroke-width=".2"/>
<circle cx="187" cy="203.3" r="1.18" fill="#008000"/>
<circle cx="187" cy="203.3" r="1.18" fill="none" stroke="#008000" stroke-width=".2"/>
<circle cx="187" cy="203.3" r=".72" fill="#fff"/>
<circle cx="187" cy="203.3" r=".72" fill="none" stroke="#000" stroke-width=".2"/>
<circle cx="100.5" cy="60.5" r="1.18" fill="#008000"/>
<circle cx="100.5" cy="60.5" r="1.18" fill="none" stroke="#008000" stroke-width=".2"/>
<circle cx="100.5" cy="60.5" r=".72" fill="#fff"/>
<circle cx="100.5" cy="60.5" r=".72" fill="none" stroke="#000" stroke-width=".2"/>
<circle cx="54.9" cy="222.7" r="1.18" fill="#008000"/>
<circle cx="54.9" cy="222.7" r="1.18" fill="none" stroke="#008000" stroke-width=".2"/>
<circle cx="54.9" cy="222.7" r=".72" fill="#fff"/>
<circle cx="54.9" cy="222.7" r=".72" fill="none" stroke="#000" stroke-width=".2"/>
<circle cx="72.6" cy="128.1" r="1.18" fill="#008000"/>
<circle cx="72.6" cy="128.1" r="1.18" fill="none" stroke="#008000" stroke-width=".2"/>
<circle cx="72.6" cy="128.1" r=".72" fill="#fff"/>
<circle cx="72.6" cy="128.1" r=".72" fill="none" stroke="#000" stroke-width=".2"/>
<circle cx="92" cy="213.4" r="1.18" fill="#008000"/>
<circle cx="92" cy="213.4" r="1.18" fill="none" stroke="#008000" stroke-width=".2"/>
<circle cx="92" cy="213.4" r=".72" fill="#fff"/>
<circle cx="92" cy="213.4" r=".72" fill="none" stroke="#000" stroke-width=".2"/>
<circle cx="95.2" cy="202.4" r="1.18" fill="#008000"/>
<circle cx="95.2" cy="202.4" r="1.18" fill="none" stroke="#008000" stroke-width=".2"/>
<circle cx="95.2" cy="202.4" r=".72" fill="#fff"/>
<circle cx="95.2" cy="202.4" r=".72" fill="none" stroke="#000" stroke-width=".2"/>
<circle cx="106.3" cy="216.2" r="1.18" fill="#008000"/>
<circle cx="106.3" cy="216.2" r="1.18" fill="none" stroke="#008000" stroke-width=".2"/>
<circle cx="106.3" cy="216.2" r=".72" fill="#fff"/>
<circle cx="106.3" cy="216.2" r=".72" fill="none" stroke="#000" stroke-width=".2"/>
<circle cx="106.3" cy="207.3" r="1.18" fill="#008000"/>
<circle cx="106.3" cy="207.3" r="1.18" fill="none" stroke="#008000" stroke-width=".2"/>
<circle cx="106.3" cy="207.3" r=".72" fill="#fff"/>
<circle cx="106.3" cy="207.3" r=".72" fill="none" stroke="#000" stroke-width=".2"/>
<circle cx="182.5" cy="122.2" r="1.18" fill="#008000"/>
<circle cx="182.5" cy="122.2" r="1.18" fill="none" stroke="#008000" stroke-width=".2"/>
<circle cx="182.5" cy="122.2" r=".72" fill="#fff"/>
<circle cx="182.5" cy="122.2" r=".72" fill="none" stroke="#000" stroke-width=".2"/>
<circle cx="170.6" cy="137.6" r="1.18" fill="#008000"/>
<circle cx="170.6" cy="137.6" r="1.18" fill="none" stroke="#008000" stroke-width=".2"/>
<circle cx="170.6" cy="137.6" r=".72" fill="#fff"/>
<circle cx="170.6" cy="137.6" r=".72" fill="none" stroke="#000" stroke-width=".2"/>
<circle cx="207.6" cy="111.4" r="1.18" fill="#008000"/>
<circle cx="207.6" cy="111.4" r="1.18" fill="none" stroke="#008000" stroke-width=".2"/>
<circle cx="207.6" cy="111.4" r=".72" fill="#fff"/>
<circle cx="207.6" cy="111.4" r=".72" fill="none" stroke="#000" stroke-width=".2"/>
<circle cx="116" cy="92.2" r="1.18" fill="#008000"/>
<circle cx="116" cy="92.2" r="1.18" fill="none" stroke="#008000" stroke-width=".2"/>
<circle cx="116" cy="92.2" r=".72" fill="#fff"/>
<circle cx="116" cy="92.2" r=".72" fill="none" stroke="#000" stroke-width=".2"/>
<circle cx="71.2" cy="219.2" r="1.18" fill="#008000"/>
<circle cx="71.2" cy="219.2" r="1.18" fill="none" stroke="#008000" stroke-width=".2"/>
<circle cx="71.2" cy="219.2" r=".72" fill="#fff"/>
<circle cx="71.2" cy="219.2" r=".72" fill="none" stroke="#000" stroke-width=".2"/>
<circle cx="66.6" cy="202.9" r="1.18" fill="#008000"/>
<circle cx="66.6" cy="202.9" r="1.18" fill="none" stroke="#008000" stroke-width=".2"/>
<circle cx="66.6" cy="202.9" r=".72" fill="#fff"/>
<circle cx="66.6" cy="202.9" r=".72" fill="none" stroke="#000" stroke-width=".2"/>
<circle cx="110.3" cy="219.8" r="1.18" fill="#008000"/>
<circle cx="110.3" cy="219.8" r="1.18" fill="none" stroke="#008000" stroke-width=".2"/>
<circle cx="110.3" cy="219.8" r=".72" fill="#fff"/>
<circle cx="110.3" cy="219.8" r=".72" fill="none" stroke="#000" stroke-width=".2"/>
<circle cx="107.7" cy="198.3" r="1.18" fill="#008000"/>
<circle cx="107.7" cy="198.3" r="1.18" fill="none" stroke="#008000" stroke-width=".2"/>
<circle cx="107.7" cy="198.3" r=".72" fill="#fff"/>
<circle cx="107.7" cy="198.3" r=".72" fill="none" stroke="#000" stroke-width=".2"/>
<circle cx="58" cy="62.7" r="1.18" fill="#008000"/>
<circle cx="58" cy="62.7" r="1.18" fill="none" stroke="#008000" stroke-width=".2"/>
<circle cx="58" cy="62.7" r=".72" fill="#fff"/>
<circle cx="58" cy="62.7" r=".72" fill="none" stroke="#000" stroke-width=".2"/>
<circle cx="58" cy="73.3" r="1.18" fill="#008000"/>
<circle cx="58" cy="73.3" r="1.18" fill="none" stroke="#008000" stroke-width=".2"/>
<circle cx="58" cy="73.3" r=".72" fill="#fff"/>
<circle cx="58" cy="73.3" r=".72" fill="none" stroke="#000" stroke-width=".2"/>
<circle cx="182" cy="194.5" r="1.18" fill="#008000"/>
<circle cx="182" cy="194.5" r="1.18" fill="none" stroke="#008000" stroke-width=".2"/>
<circle cx="182" cy="194.5" r=".72" fill="#fff"/>
<circle cx="182" cy="194.5" r=".72" fill="none" stroke="#000" stroke-width=".2"/>
<circle cx="207.7" cy="184.4" r="1.18" fill="#008000"/>
<circle cx="207.7" cy="184.4" r="1.18" fill="none" stroke="#008000" stroke-width=".2"/>
<circle cx="207.7" cy="184.4" r=".72" fill="#fff"/>
<circle cx="207.7" cy="184.4" r=".72" fill="none" stroke="#000" stroke-width=".2"/>
<circle cx="170.7" cy="212.5" r="1.18" fill="#008000"/>
<circle cx="170.7" cy="212.5" r="1.18" fill="none" stroke="#008000" stroke-width=".2"/>
<circle cx="170.7" cy="212.5" r=".72" fill="#fff"/>
<circle cx="170.7" cy="212.5" r=".72" fill="none" stroke="#000" stroke-width=".2"/>
<circle cx="73.8" cy="198.2" r="1.18" fill="#008000"/>
<circle cx="73.8" cy="198.2" r="1.18" fill="none" stroke="#008000" stroke-width=".2"/>
<circle cx="73.8" cy="198.2" r=".72" fill="#fff"/>
<circle cx="73.8" cy="198.2" r=".72" fill="none" stroke="#000" stroke-width=".2"/>
<circle cx="58" cy="82.2" r="1.18" fill="#008000"/>
<circle cx="58" cy="82.2" r="1.18" fill="none" stroke="#008000" stroke-width=".2"/>
<circle cx="58" cy="82.2" r=".72" fill="#fff"/>
<circle cx="58" cy="82.2" r=".72" fill="none" stroke="#000" stroke-width=".2"/>
<circle cx="93" cy="81.6" r="1.18" fill="#008000"/>
<circle cx="93" cy="81.6" r="1.18" fill="none" stroke="#008000" stroke-width=".2"/>
<circle cx="93" cy="81.6" r=".72" fill="#fff"/>
<circle cx="93" cy="81.6" r=".72" fill="none" stroke="#000" stroke-width=".2"/>
<circle cx="102.4" cy="80.9" r="1.18" fill="#008000"/>
<circle cx="102.4" cy="80.9" r="1.18" fill="none" stroke="#008000" stroke-width=".2"/>
<circle cx="102.4" cy="80.9" r=".72" fill="#fff"/>
<circle cx="102.4" cy="80.9" r=".72" fill="none" stroke="#000" stroke-width=".2"/>
<circle cx="102.2" cy="71.2" r="1.18" fill="#008000"/>
<circle cx="102.2" cy="71.2" r="1.18" fill="none" stroke="#008000" stroke-width=".2"/>
<circle cx="102.2" cy="71.2" r=".72" fill="#fff"/>
<circle cx="102.2" cy="71.2" r=".72" fill="none" stroke="#000" stroke-width=".2"/>
<circle cx="102.7" cy="188.8" r="1.18" fill="#008000"/>
<circle cx="102.7" cy="188.8" r="1.18" fill="none" stroke="#008000" stroke-width=".2"/>
<circle cx="102.7" cy="188.8" r=".72" fill="#fff"/>
<circle cx="102.7" cy="188.8" r=".72" fill="none" stroke="#000" stroke-width=".2"/>
<circle cx="80.4" cy="157.6" r="1.18" fill="#008000"/>
<circle cx="80.4" cy="157.6" r="1.18" fill="none" stroke="#008000" stroke-width=".2"/>
<circle cx="80.4" cy="157.6" r=".72" fill="#fff"/>
<circle cx="80.4" cy="157.6" r=".72" fill="none" stroke="#000" stroke-width=".2"/>
<circle cx="84.3" cy="171.8" r="1.18" fill="#008000"/>
<circle cx="84.3" cy="171.8" r="1.18" fill="none" stroke="#008000" stroke-width=".2"/>
<circle cx="84.3" cy="171.8" r=".72" fill="#fff"/>
<circle cx="84.3" cy="171.8" r=".72" fill="none" stroke="#000" stroke-width=".2"/>
<circle cx="26.4" cy="102.7" r="1.18" fill="#008000"/>
<circle cx="26.4" cy="102.7" r="1.18" fill="none" stroke="#008000" stroke-width=".2"/>
<circle cx="26.4" cy="102.7" r=".72" fill="#fff"/>
<circle cx="26.4" cy="102.7" r=".72" fill="none" stroke="#000" stroke-width=".2"/>
<circle cx="43.9" cy="103.2" r="1.18" fill="#008000"/>
<circle cx="43.9" cy="103.2" r="1.18" fill="none" stroke="#008000" stroke-width=".2"/>
<circle cx="43.9" cy="103.2" r=".72" fill="#fff"/>
<circle cx="43.9" cy="103.2" r=".72" fill="none" stroke="#000" stroke-width=".2"/>
<circle cx="176.5" cy="68.6" r="1.18" fill="#008000"/>
<circle cx="176.5" cy="68.6" r="1.18" fill="none" stroke="#008000" stroke-width=".2"/>
<circle cx="176.5" cy="68.6" r=".72" fill="#fff"/>
<circle cx="176.5" cy="68.6" r=".72" fill="none" stroke="#000" stroke-width=".2"/>
<circle cx="88.2" cy="74.6" r="1.18" fill="#008000"/>
<circle cx="88.2" cy="74.6" r="1.18" fill="none" stroke="#008000" stroke-width=".2"/>
<circle cx="88.2" cy="74.6" r=".72" fill="#fff"/>
<circle cx="88.2" cy="74.6" r=".72" fill="none" stroke="#000" stroke-width=".2"/>
<circle cx="110.1" cy="116" r="1.18" fill="#008000"/>
<circle cx="110.1" cy="116" r="1.18" fill="none" stroke="#008000" stroke-width=".2"/>
<circle cx="110.1" cy="116" r=".72" fill="#fff"/>
<circle cx="110.1" cy="116" r=".72" fill="none" stroke="#000" stroke-width=".2"/>
<circle cx="54.8" cy="199.9" r="1.18" fill="#008000"/>
<circle cx="54.8" cy="199.9" r="1.18" fill="none" stroke="#008000" stroke-width=".2"/>
<circle cx="54.8" cy="199.9" r=".72" fill="#fff"/>
<circle cx="54.8" cy="199.9" r=".72" fill="none" stroke="#000" stroke-width=".2"/>
<circle cx="54.8" cy="212.9" r="1.18" fill="#008000"/>
<circle cx="54.8" cy="212.9" r="1.18" fill="none" stroke="#008000" stroke-width=".2"/>
<circle cx="54.8" cy="212.9" r=".72" fill="#fff"/>
<circle cx="54.8" cy="212.9" r=".72" fill="none" stroke="#000" stroke-width=".2"/>
<circle cx="67.9" cy="215.6" r="1.18" fill="#008000"/>
<circle cx="67.9" cy="215.6" r="1.18" fill="none" stroke="#008000" stroke-width=".2"/>
<circle cx="67.9" cy="215.6" r=".72" fill="#fff"/>
<circle cx="67.9" cy="215.6" r=".72" fill="none" stroke="#000" stroke-width=".2"/>
<circle cx="67.9" cy="208.1" r="1.18" fill="#008000"/>
<circle cx="67.9" cy="208.1" r="1.18" fill="none" stroke="#008000" stroke-width=".2"/>
<circle cx="67.9" cy="208.1" r=".72" fill="#fff"/>
<circle cx="67.9" cy="208.1" r=".72" fill="none" stroke="#000" stroke-width=".2"/>
<circle cx="120.1" cy="68.6" r="1.18" fill="#008000"/>
<circle cx="120.1" cy="68.6" r="1.18" fill="none" stroke="#008000" stroke-width=".2"/>
<circle cx="120.1" cy="68.6" r=".72" fill="#fff"/>
<circle cx="120.1" cy="68.6" r=".72" fill="none" stroke="#000" stroke-width=".2"/>
<circle cx="130.4" cy="109.8" r="1.18" fill="#008000"/>
<circle cx="130.4" cy="109.8" r="1.18" fill="none" stroke="#008000" stroke-width=".2"/>
<circle cx="130.4" cy="109.8" r=".72" fill="#fff"/>
<circle cx="130.4" cy="109.8" r=".72" fill="none" stroke="#000" stroke-width=".2"/>
<circle cx="93.7" cy="60.5" r="1.18" fill="#008000"/>
<circle cx="93.7" cy="60.5" r="1.18" fill="none" stroke="#008000" stroke-width=".2"/>
<circle cx="93.7" cy="60.5" r=".72" fill="#fff"/>
<circle cx="93.7" cy="60.5" r=".72" fill="none" stroke="#000" stroke-width=".2"/>
<circle cx="64" cy="73.3" r="1.18" fill="#008000"/>
<circle cx="64" cy="73.3" r="1.18" fill="none" stroke="#008000" stroke-width=".2"/>
<circle cx="64" cy="73.3" r=".72" fill="#fff"/>
<circle cx="64" cy="73.3" r=".72" fill="none" stroke="#000" stroke-width=".2"/>
<circle cx="64" cy="82.2" r="1.18" fill="#008000"/>
<circle cx="64" cy="82.2" r="1.18" fill="none" stroke="#008000" stroke-width=".2"/>
<circle cx="64" cy="82.2" r=".72" fill="#fff"/>
<circle cx="64" cy="82.2" r=".72" fill="none" stroke="#000" stroke-width=".2"/>
<circle cx="175.4" cy="180.9" r="1.18" fill="#008000"/>
<circle cx="175.4" cy="180.9" r="1.18" fill="none" stroke="#008000" stroke-width=".2"/>
<circle cx="175.4" cy="180.8" r=".72" fill="#fff"/>
<circle cx="175.4" cy="180.8" r=".72" fill="none" stroke="#000" stroke-width=".2"/>
<circle cx="175.4" cy="188.7" r="1.18" fill="#008000"/>
<circle cx="175.4" cy="188.7" r="1.18" fill="none" stroke="#008000" stroke-width=".2"/>
<circle cx="175.4" cy="188.7" r=".72" fill="#fff"/>
<circle cx="175.4" cy="188.7" r=".72" fill="none" stroke="#000" stroke-width=".2"/>
<circle cx="126.6" cy="171.1" r="1.18" fill="#008000"/>
<circle cx="126.6" cy="171.1" r="1.18" fill="none" stroke="#008000" stroke-width=".2"/>
<circle cx="126.6" cy="171.1" r=".72" fill="#fff"/>
<circle cx="126.6" cy="171.1" r=".72" fill="none" stroke="#000" stroke-width=".2"/>
<circle cx="144.2" cy="173.3" r="1.18" fill="#008000"/>
<circle cx="144.2" cy="173.3" r="1.18" fill="none" stroke="#008000" stroke-width=".2"/>
<circle cx="144.2" cy="173.3" r=".72" fill="#fff"/>
<circle cx="144.2" cy="173.3" r=".72" fill="none" stroke="#000" stroke-width=".2"/>
<circle cx="66.6" cy="63" r="1.18" fill="#008000"/>
<circle cx="66.6" cy="63" r="1.18" fill="none" stroke="#008000" stroke-width=".2"/>
<circle cx="66.6" cy="63" r=".72" fill="#fff"/>
<circle cx="66.6" cy="63" r=".72" fill="none" stroke="#000" stroke-width=".2"/>
<circle cx="93.7" cy="60.5" r="1.18" fill="#008000"/>
<circle cx="93.7" cy="60.5" r="1.18" fill="none" stroke="#008000" stroke-width=".2"/>
<circle cx="93.7" cy="60.5" r=".72" fill="#fff"/>
<circle cx="93.7" cy="60.5" r=".72" fill="none" stroke="#000" stroke-width=".2"/>
<circle cx="76.5" cy="61" r="1.18" fill="#008000"/>
<circle cx="76.5" cy="61" r="1.18" fill="none" stroke="#008000" stroke-width=".2"/>
<circle cx="76.5" cy="61" r=".72" fill="#fff"/>
<circle cx="76.5" cy="61" r=".72" fill="none" stroke="#000" stroke-width=".2"/>
<circle cx="98.7" cy="131.7" r="1.18" fill="#008000"/>
<circle cx="98.7" cy="131.7" r="1.18" fill="none" stroke="#008000" stroke-width=".2"/>
<circle cx="98.7" cy="131.7" r=".72" fill="#fff"/>
<circle cx="98.7" cy="131.7" r=".72" fill="none" stroke="#000" stroke-width=".2"/>
<circle cx="87.8" cy="87.7" r="1.18" fill="#008000"/>
<circle cx="87.8" cy="87.7" r="1.18" fill="none" stroke="#008000" stroke-width=".2"/>
<circle cx="87.8" cy="87.7" r=".72" fill="#fff"/>
<circle cx="87.8" cy="87.7" r=".72" fill="none" stroke="#000" stroke-width=".2"/>
<circle cx="84.5" cy="90.4" r="1.18" fill="#008000"/>
<circle cx="84.5" cy="90.4" r="1.18" fill="none" stroke="#008000" stroke-width=".2"/>
<circle cx="84.5" cy="90.4" r=".72" fill="#fff"/>
<circle cx="84.5" cy="90.4" r=".72" fill="none" stroke="#000" stroke-width=".2"/>
<circle cx="96.1" cy="134.4" r="1.18" fill="#008000"/>
<circle cx="96.1" cy="134.4" r="1.18" fill="none" stroke="#008000" stroke-width=".2"/>
<circle cx="96.1" cy="134.4" r=".72" fill="#fff"/>
<circle cx="96.1" cy="134.4" r=".72" fill="none" stroke="#000" stroke-width=".2"/>
<circle cx="55.1" cy="73.3" r="1.18" fill="#008000"/>
<circle cx="55.1" cy="73.3" r="1.18" fill="none" stroke="#008000" stroke-width=".2"/>
<circle cx="55.1" cy="73.3" r=".72" fill="#fff"/>
<circle cx="55.1" cy="73.3" r=".72" fill="none" stroke="#000" stroke-width=".2"/>
<circle cx="55.1" cy="82.2" r="1.18" fill="#008000"/>
<circle cx="55.1" cy="82.2" r="1.18" fill="none" stroke="#008000" stroke-width=".2"/>
<circle cx="55.1" cy="82.2" r=".72" fill="#fff"/>
<circle cx="55.1" cy="82.2" r=".72" fill="none" stroke="#000" stroke-width=".2"/>
<circle cx="55.1" cy="120.7" r="1.18" fill="#008000"/>
<circle cx="55.1" cy="120.7" r="1.18" fill="none" stroke="#008000" stroke-width=".2"/>
<circle cx="55.1" cy="120.7" r=".72" fill="#fff"/>
<circle cx="55.1" cy="120.7" r=".72" fill="none" stroke="#000" stroke-width=".2"/>
<circle cx="93.3" cy="123.8" r="1.18" fill="#008000"/>
<circle cx="93.3" cy="123.8" r="1.18" fill="none" stroke="#008000" stroke-width=".2"/>
<circle cx="93.3" cy="123.8" r=".72" fill="#fff"/>
<circle cx="93.3" cy="123.8" r=".72" fill="none" stroke="#000" stroke-width=".2"/>
<circle cx="30" cy="72.2" r="1.18" fill="#008000"/>
<circle cx="30" cy="72.2" r="1.18" fill="none" stroke="#008000" stroke-width=".2"/>
<circle cx="30" cy="72.2" r=".72" fill="#fff"/>
<circle cx="30" cy="72.2" r=".72" fill="none" stroke="#000" stroke-width=".2"/>
<circle cx="19.2" cy="85.4" r="1.18" fill="#008000"/>
<circle cx="19.2" cy="85.4" r="1.18" fill="none" stroke="#008000" stroke-width=".2"/>
<circle cx="19.2" cy="85.4" r=".72" fill="#fff"/>
<circle cx="19.2" cy="85.4" r=".72" fill="none" stroke="#000" stroke-width=".2"/>
<circle cx="106" cy="152.7" r="1.18" fill="#008000"/>
<circle cx="106" cy="152.7" r="1.18" fill="none" stroke="#008000" stroke-width=".2"/>
<circle cx="106" cy="152.7" r=".72" fill="#fff"/>
<circle cx="106" cy="152.7" r=".72" fill="none" stroke="#000" stroke-width=".2"/>
<circle cx="51.5" cy="150.9" r="1.18" fill="#008000"/>
<circle cx="51.5" cy="150.9" r="1.18" fill="none" stroke="#008000" stroke-width=".2"/>
<circle cx="51.5" cy="150.9" r=".72" fill="#fff"/>
<circle cx="51.5" cy="150.9" r=".72" fill="none" stroke="#000" stroke-width=".2"/>
<circle cx="61" cy="73.3" r="1.18" fill="#008000"/>
<circle cx="61" cy="73.3" r="1.18" fill="none" stroke="#008000" stroke-width=".2"/>
<circle cx="61" cy="73.3" r=".72" fill="#fff"/>
<circle cx="61" cy="73.3" r=".72" fill="none" stroke="#000" stroke-width=".2"/>
<circle cx="61" cy="82.2" r="1.18" fill="#008000"/>
<circle cx="61" cy="82.2" r="1.18" fill="none" stroke="#008000" stroke-width=".2"/>
<circle cx="61" cy="82.2" r=".72" fill="#fff"/>
<circle cx="61" cy="82.2" r=".72" fill="none" stroke="#000" stroke-width=".2"/>
<circle cx="91.1" cy="125.7" r="1.18" fill="#008000"/>
<circle cx="91.1" cy="125.7" r="1.18" fill="none" stroke="#008000" stroke-width=".2"/>
<circle cx="91.1" cy="125.7" r=".72" fill="#fff"/>
<circle cx="91.1" cy="125.7" r=".72" fill="none" stroke="#000" stroke-width=".2"/>
<circle cx="61" cy="133.2" r="1.18" fill="#008000"/>
<circle cx="61" cy="133.2" r="1.18" fill="none" stroke="#008000" stroke-width=".2"/>
<circle cx="61" cy="133.2" r=".72" fill="#fff"/>
<circle cx="61" cy="133.2" r=".72" fill="none" stroke="#000" stroke-width=".2"/>
<circle cx="106" cy="125.1" r="1.18" fill="#008000"/>
<circle cx="106" cy="125.1" r="1.18" fill="none" stroke="#008000" stroke-width=".2"/>
<circle cx="106" cy="125.1" r=".72" fill="#fff"/>
<circle cx="106" cy="125.1" r=".72" fill="none" stroke="#000" stroke-width=".2"/>
<circle cx="112.2" cy="138.8" r="1.18" fill="#008000"/>
<circle cx="112.2" cy="138.8" r="1.18" fill="none" stroke="#008000" stroke-width=".2"/>
<circle cx="112.2" cy="138.8" r=".72" fill="#fff"/>
<circle cx="112.2" cy="138.8" r=".72" fill="none" stroke="#000" stroke-width=".2"/>
<circle cx="174.8" cy="91.6" r="1.18" fill="#008000"/>
<circle cx="174.8" cy="91.6" r="1.18" fill="none" stroke="#008000" stroke-width=".2"/>
<circle cx="174.8" cy="91.6" r=".72" fill="#fff"/>
<circle cx="174.8" cy="91.6" r=".72" fill="none" stroke="#000" stroke-width=".2"/>
<circle cx="172.3" cy="78.8" r="1.18" fill="#008000"/>
<circle cx="172.3" cy="78.8" r="1.18" fill="none" stroke="#008000" stroke-width=".2"/>
<circle cx="172.3" cy="78.8" r=".72" fill="#fff"/>
<circle cx="172.3" cy="78.8" r=".72" fill="none" stroke="#000" stroke-width=".2"/>
<circle cx="193.9" cy="125.6" r="1.18" fill="#008000"/>
<circle cx="193.9" cy="125.6" r="1.18" fill="none" stroke="#008000" stroke-width=".2"/>
<circle cx="193.9" cy="125.6" r=".72" fill="#fff"/>
<circle cx="193.9" cy="125.6" r=".72" fill="none" stroke="#000" stroke-width=".2"/>
<circle cx="199.9" cy="120.6" r="1.18" fill="#008000"/>
<circle cx="199.9" cy="120.6" r="1.18" fill="none" stroke="#008000" stroke-width=".2"/>
<circle cx="199.9" cy="120.6" r=".72" fill="#fff"/>
<circle cx="199.9" cy="120.6" r=".72" fill="none" stroke="#000" stroke-width=".2"/>
<circle cx="175.3" cy="129.2" r="1.18" fill="#008000"/>
<circle cx="175.3" cy="129.2" r="1.18" fill="none" stroke="#008000" stroke-width=".2"/>
<circle cx="175.3" cy="129.2" r=".72" fill="#fff"/>
<circle cx="175.3" cy="129.2" r=".72" fill="none" stroke="#000" stroke-width=".2"/>
<circle cx="187.6" cy="129.2" r="1.18" fill="#008000"/>
<circle cx="187.6" cy="129.2" r="1.18" fill="none" stroke="#008000" stroke-width=".2"/>
<circle cx="187.6" cy="129.2" r=".72" fill="#fff"/>
<circle cx="187.6" cy="129.2" r=".72" fill="none" stroke="#000" stroke-width=".2"/>
<circle cx="171.7" cy="95.8" r="1.18" fill="#008000"/>
<circle cx="171.7" cy="95.8" r="1.18" fill="none" stroke="#008000" stroke-width=".2"/>
<circle cx="171.7" cy="95.8" r=".72" fill="#fff"/>
<circle cx="171.7" cy="95.8" r=".72" fill="none" stroke="#000" stroke-width=".2"/>
<circle cx="178.9" cy="158.9" r="1.18" fill="#008000"/>
<circle cx="178.9" cy="158.9" r="1.18" fill="none" stroke="#008000" stroke-width=".2"/>
<circle cx="178.9" cy="158.9" r=".72" fill="#fff"/>
<circle cx="178.9" cy="158.9" r=".72" fill="none" stroke="#000" stroke-width=".2"/>
<circle cx="84.7" cy="60.7" r="1.18" fill="#008000"/>
<circle cx="84.7" cy="60.7" r="1.18" fill="none" stroke="#008000" stroke-width=".2"/>
<circle cx="84.7" cy="60.7" r=".72" fill="#fff"/>
<circle cx="84.7" cy="60.7" r=".72" fill="none" stroke="#000" stroke-width=".2"/>
<circle cx="100.2" cy="90.1" r="1.18" fill="#008000"/>
<circle cx="100.2" cy="90.1" r="1.18" fill="none" stroke="#008000" stroke-width=".2"/>
<circle cx="100.2" cy="90.1" r=".72" fill="#fff"/>
<circle cx="100.2" cy="90.1" r=".72" fill="none" stroke="#000" stroke-width=".2"/>
<circle cx="197.4" cy="51.1" r="1.18" fill="#008000"/>
<circle cx="197.4" cy="51.1" r="1.18" fill="none" stroke="#008000" stroke-width=".2"/>
<circle cx="197.4" cy="51.1" r=".72" fill="#fff"/>
<circle cx="197.4" cy="51.1" r=".72" fill="none" stroke="#000" stroke-width=".2"/>
<circle cx="175.6" cy="106" r="1.18" fill="#008000"/>
<circle cx="175.6" cy="106" r="1.18" fill="none" stroke="#008000" stroke-width=".2"/>
<circle cx="175.6" cy="106" r=".72" fill="#fff"/>
<circle cx="175.6" cy="106" r=".72" fill="none" stroke="#000" stroke-width=".2"/>
<circle cx="175.6" cy="114.2" r="1.18" fill="#008000"/>
<circle cx="175.6" cy="114.2" r="1.18" fill="none" stroke="#008000" stroke-width=".2"/>
<circle cx="175.6" cy="114.2" r=".72" fill="#fff"/>
<circle cx="175.6" cy="114.2" r=".72" fill="none" stroke="#000" stroke-width=".2"/>
<circle cx="25.2" cy="52.7" r="1.18" fill="#008000"/>
<circle cx="25.2" cy="52.7" r="1.18" fill="none" stroke="#008000" stroke-width=".2"/>
<circle cx="25.2" cy="52.7" r=".72" fill="#fff"/>
<circle cx="25.2" cy="52.7" r=".72" fill="none" stroke="#000" stroke-width=".2"/>
<circle cx="15.5" cy="77.6" r="1.18" fill="#008000"/>
<circle cx="15.5" cy="77.6" r="1.18" fill="none" stroke="#008000" stroke-width=".2"/>
<circle cx="15.5" cy="77.6" r=".72" fill="#fff"/>
<circle cx="15.5" cy="77.6" r=".72" fill="none" stroke="#000" stroke-width=".2"/>
<circle cx="166.9" cy="82.7" r="1.18" fill="#008000"/>
<circle cx="166.9" cy="82.7" r="1.18" fill="none" stroke="#008000" stroke-width=".2"/>
<circle cx="166.9" cy="82.7" r=".72" fill="#fff"/>
<circle cx="166.9" cy="82.7" r=".72" fill="none" stroke="#000" stroke-width=".2"/>
<circle cx="197.4" cy="69.4" r="1.18" fill="#008000"/>
<circle cx="197.4" cy="69.4" r="1.18" fill="none" stroke="#008000" stroke-width=".2"/>
<circle cx="197.4" cy="69.4" r=".72" fill="#fff"/>
<circle cx="197.4" cy="69.4" r=".72" fill="none" stroke="#000" stroke-width=".2"/>
<circle cx="194.1" cy="38.1" r="5" fill="#008000"/>
<circle cx="194.1" cy="38.1" r="5" fill="none" stroke="#008000" stroke-width=".2"/>
<circle cx="194.1" cy="38.1" r="3.8" fill="#fff"/>
<circle cx="194.1" cy="38.1" r="3.8" fill="none" stroke="#000" stroke-width=".2"/>
<circle cx="21.8" cy="38.1" r="5" fill="#008000"/>
<circle cx="21.8" cy="38.1" r="5" fill="none" stroke="#008000" stroke-width=".2"/>
<circle cx="21.8" cy="38.1" r="3.8" fill="#fff"/>
<circle cx="21.8" cy="38.1" r="3.8" fill="none" stroke="#000" stroke-width=".2"/>
<circle cx="12.8" cy="238.6" r="5" fill="#008000"/>
<circle cx="12.8" cy="238.6" r="5" fill="none" stroke="#008000" stroke-width=".2"/>
<circle cx="12.8" cy="238.6" r="3.8" fill="#fff"/>
<circle cx="12.8" cy="238.6" r="3.8" fill="none" stroke="#000" stroke-width=".2"/>
<circle cx="200" cy="238.6" r="5" fill="#008000"/>
<circle cx="200" cy="238.6" r="5" fill="none" stroke="#008000" stroke-width=".2"/>
<circle cx="200" cy="238.6" r="3.8" fill="#fff"/>
<circle cx="200" cy="238.6" r="3.8" fill="none" stroke="#000" stroke-width=".2"/>
<circle cx="26.3" cy="234.2" r="1.18" fill="#008000"/>
<circle cx="26.3" cy="234.2" r="1.18" fill="none" stroke="#008000" stroke-width=".2"/>
<circle cx="26.3" cy="234.2" r=".72" fill="#fff"/>
<circle cx="26.3" cy="234.2" r=".72" fill="none" stroke="#000" stroke-width=".2"/>
<circle cx="42.6" cy="238.9" r="1.18" fill="#008000"/>
<circle cx="42.6" cy="238.9" r="1.18" fill="none" stroke="#008000" stroke-width=".2"/>
<circle cx="42.6" cy="238.9" r=".72" fill="#fff"/>
<circle cx="42.6" cy="238.9" r=".72" fill="none" stroke="#000" stroke-width=".2"/>
<circle cx="59" cy="234.2" r="1.18" fill="#008000"/>
<circle cx="59" cy="234.2" r="1.18" fill="none" stroke="#008000" stroke-width=".2"/>
<circle cx="59" cy="234.2" r=".72" fill="#fff"/>
<circle cx="59" cy="234.2" r=".72" fill="none" stroke="#000" stroke-width=".2"/>
<circle cx="75.4" cy="238.9" r="1.18" fill="#008000"/>
<circle cx="75.4" cy="238.9" r="1.18" fill="none" stroke="#008000" stroke-width=".2"/>
<circle cx="75.4" cy="238.9" r=".72" fill="#fff"/>
<circle cx="75.4" cy="238.9" r=".72" fill="none" stroke="#000" stroke-width=".2"/>
<circle cx="91.8" cy="234.2" r="1.18" fill="#008000"/>
<circle cx="91.8" cy="234.2" r="1.18" fill="none" stroke="#008000" stroke-width=".2"/>
<circle cx="91.8" cy="234.2" r=".72" fill="#fff"/>
<circle cx="91.8" cy="234.2" r=".72" fill="none" stroke="#000" stroke-width=".2"/>
<circle cx="108.1" cy="238.9" r="1.18" fill="#008000"/>
<circle cx="108.1" cy="238.9" r="1.18" fill="none" stroke="#008000" stroke-width=".2"/>
<circle cx="108.1" cy="238.9" r=".72" fill="#fff"/>
<circle cx="108.1" cy="238.9" r=".72" fill="none" stroke="#000" stroke-width=".2"/>
<circle cx="124.5" cy="234.2" r="1.18" fill="#008000"/>
<circle cx="124.5" cy="234.2" r="1.18" fill="none" stroke="#008000" stroke-width=".2"/>
<circle cx="124.5" cy="234.2" r=".72" fill="#fff"/>
<circle cx="124.5" cy="234.2" r=".72" fill="none" stroke="#000" stroke-width=".2"/>
<circle cx="140.9" cy="238.9" r="1.18" fill="#008000"/>
<circle cx="140.9" cy="238.9" r="1.18" fill="none" stroke="#008000" stroke-width=".2"/>
<circle cx="140.9" cy="238.9" r=".72" fill="#fff"/>
<circle cx="140.9" cy="238.9" r=".72" fill="none" stroke="#000" stroke-width=".2"/>
<circle cx="157.3" cy="234.2" r="1.18" fill="#008000"/>
<circle cx="157.3" cy="234.2" r="1.18" fill="none" stroke="#008000" stroke-width=".2"/>
<circle cx="157.3" cy="234.2" r=".72" fill="#fff"/>
<circle cx="157.3" cy="234.2" r=".72" fill="none" stroke="#000" stroke-width=".2"/>
<circle cx="61.3" cy="215.6" r="1.18" fill="#008000"/>
<circle cx="61.3" cy="215.6" r="1.18" fill="none" stroke="#008000" stroke-width=".2"/>
<circle cx="61.3" cy="215.6" r=".72" fill="#fff"/>
<circle cx="61.3" cy="215.6" r=".72" fill="none" stroke="#000" stroke-width=".2"/>
<circle cx="59.9" cy="212.6" r="1.18" fill="#008000"/>
<circle cx="59.9" cy="212.6" r="1.18" fill="none" stroke="#008000" stroke-width=".2"/>
<circle cx="59.9" cy="212.6" r=".72" fill="#fff"/>
<circle cx="59.9" cy="212.6" r=".72" fill="none" stroke="#000" stroke-width=".2"/>
<circle cx="98.5" cy="213.1" r="1.18" fill="#008000"/>
<circle cx="98.5" cy="213.1" r="1.18" fill="none" stroke="#008000" stroke-width=".2"/>
<circle cx="98.5" cy="213.1" r=".72" fill="#fff"/>
<circle cx="98.5" cy="213.1" r=".72" fill="none" stroke="#000" stroke-width=".2"/>
<circle cx="99.9" cy="216.1" r="1.18" fill="#008000"/>
<circle cx="99.9" cy="216.1" r="1.18" fill="none" stroke="#008000" stroke-width=".2"/>
<circle cx="99.9" cy="216.1" r=".72" fill="#fff"/>
<circle cx="99.9" cy="216.1" r=".72" fill="none" stroke="#000" stroke-width=".2"/>
<circle cx="79.3" cy="169.7" r="1.18" fill="#008000"/>
<circle cx="79.3" cy="169.7" r="1.18" fill="none" stroke="#008000" stroke-width=".2"/>
<circle cx="79.3" cy="169.7" r=".72" fill="#fff"/>
<circle cx="79.3" cy="169.7" r=".72" fill="none" stroke="#000" stroke-width=".2"/>
<circle cx="112.6" cy="168.4" r="1.18" fill="#008000"/>
<circle cx="112.6" cy="168.4" r="1.18" fill="none" stroke="#008000" stroke-width=".2"/>
<circle cx="112.6" cy="168.4" r=".72" fill="#fff"/>
<circle cx="112.6" cy="168.4" r=".72" fill="none" stroke="#000" stroke-width=".2"/>
<circle cx="101.2" cy="165.7" r="1.18" fill="#008000"/>
<circle cx="101.2" cy="165.7" r="1.18" fill="none" stroke="#008000" stroke-width=".2"/>
<circle cx="101.2" cy="165.7" r=".72" fill="#fff"/>
<circle cx="101.2" cy="165.7" r=".72" fill="none" stroke="#000" stroke-width=".2"/>
<circle cx="89.6" cy="168.1" r="1.18" fill="#008000"/>
<circle cx="89.6" cy="168.1" r="1.18" fill="none" stroke="#008000" stroke-width=".2"/>
<circle cx="89.6" cy="168.1" r=".72" fill="#fff"/>
<circle cx="89.6" cy="168.1" r=".72" fill="none" stroke="#000" stroke-width=".2"/>
<circle cx="68" cy="167.2" r="1.18" fill="#008000"/>
<circle cx="68" cy="167.2" r="1.18" fill="none" stroke="#008000" stroke-width=".2"/>
<circle cx="68" cy="167.2" r=".72" fill="#fff"/>
<circle cx="68" cy="167.2" r=".72" fill="none" stroke="#000" stroke-width=".2"/>
<circle cx="58.8" cy="168.8" r="1.18" fill="#008000"/>
<circle cx="58.8" cy="168.8" r="1.18" fill="none" stroke="#008000" stroke-width=".2"/>
<circle cx="58.8" cy="168.8" r=".72" fill="#fff"/>
<circle cx="58.8" cy="168.8" r=".72" fill="none" stroke="#000" stroke-width=".2"/>
<circle cx="64" cy="89.3" r="1.18" fill="#008000"/>
<circle cx="64" cy="89.3" r="1.18" fill="none" stroke="#008000" stroke-width=".2"/>
<circle cx="64" cy="89.3" r=".72" fill="#fff"/>
<circle cx="64" cy="89.3" r=".72" fill="none" stroke="#000" stroke-width=".2"/>
<circle cx="129" cy="73.8" r="1.18" fill="#008000"/>
<circle cx="129" cy="73.8" r="1.18" fill="none" stroke="#008000" stroke-width=".2"/>
<circle cx="129" cy="73.8" r=".72" fill="#fff"/>
<circle cx="129" cy="73.8" r=".72" fill="none" stroke="#000" stroke-width=".2"/>
<circle cx="146" cy="76.7" r="1.18" fill="#008000"/>
<circle cx="146" cy="76.7" r="1.18" fill="none" stroke="#008000" stroke-width=".2"/>
<circle cx="146" cy="76.7" r=".72" fill="#fff"/>
<circle cx="146" cy="76.7" r=".72" fill="none" stroke="#000" stroke-width=".2"/>
<circle cx="101.4" cy="73.8" r="1.18" fill="#008000"/>
<circle cx="101.4" cy="73.8" r="1.18" fill="none" stroke="#008000" stroke-width=".2"/>
<circle cx="101.4" cy="73.8" r=".72" fill="#fff"/>
<circle cx="101.4" cy="73.8" r=".72" fill="none" stroke="#000" stroke-width=".2"/>
<circle cx="122.8" cy="112.7" r="1.18" fill="#008000"/>
<circle cx="122.8" cy="112.7" r="1.18" fill="none" stroke="#008000" stroke-width=".2"/>
<circle cx="122.8" cy="112.7" r=".72" fill="#fff"/>
<circle cx="122.8" cy="112.7" r=".72" fill="none" stroke="#000" stroke-width=".2"/>
<circle cx="141.8" cy="97.5" r="1.18" fill="#008000"/>
<circle cx="141.8" cy="97.5" r="1.18" fill="none" stroke="#008000" stroke-width=".2"/>
<circle cx="141.8" cy="97.5" r=".72" fill="#fff"/>
<circle cx="141.8" cy="97.5" r=".72" fill="none" stroke="#000" stroke-width=".2"/>
<circle cx="66.4" cy="157.1" r="1.18" fill="#008000"/>
<circle cx="66.4" cy="157.1" r="1.18" fill="none" stroke="#008000" stroke-width=".2"/>
<circle cx="66.4" cy="157.1" r=".72" fill="#fff"/>
<circle cx="66.4" cy="157.1" r=".72" fill="none" stroke="#000" stroke-width=".2"/>
<circle cx="49.6" cy="156.4" r="1.18" fill="#008000"/>
<circle cx="49.6" cy="156.4" r="1.18" fill="none" stroke="#008000" stroke-width=".2"/>
<circle cx="49.6" cy="156.4" r=".72" fill="#fff"/>
<circle cx="49.6" cy="156.4" r=".72" fill="none" stroke="#000" stroke-width=".2"/>
<circle cx="126.5" cy="68.6" r="1.18" fill="#008000"/>
<circle cx="126.5" cy="68.6" r="1.18" fill="none" stroke="#008000" stroke-width=".2"/>
<circle cx="126.5" cy="68.6" r=".72" fill="#fff"/>
<circle cx="126.5" cy="68.6" r=".72" fill="none" stroke="#000" stroke-width=".2"/>
<circle cx="132.8" cy="213.1" r="1.18" fill="#008000"/>
<circle cx="132.8" cy="213.1" r="1.18" fill="none" stroke="#008000" stroke-width=".2"/>
<circle cx="132.8" cy="213.1" r=".72" fill="#fff"/>
<circle cx="132.8" cy="213.1" r=".72" fill="none" stroke="#000" stroke-width=".2"/>
<circle cx="50.5" cy="224.7" r="1.18" fill="#008000"/>
<circle cx="50.5" cy="224.7" r="1.18" fill="none" stroke="#008000" stroke-width=".2"/>
<circle cx="50.5" cy="224.7" r=".72" fill="#fff"/>
<circle cx="50.5" cy="224.7" r=".72" fill="none" stroke="#000" stroke-width=".2"/>
<path d="M18.4 56h7.4v3.9h-7.4z" fill-rule="evenodd" fill="#800000"/>
<path d="M18.4 56h7.4v3.9h-7.4z" fill="none" stroke="#800000" stroke-width=".2"/>
<path d="M16.5 70.3h8.3v.9h-8.3z" fill-rule="evenodd" fill="#800000"/>
<path d="M16.5 70.3h8.3v.9h-8.3z" fill="none" stroke="#800000" stroke-width=".2"/>
<path d="M22.7 95.3h7.4v3.9h-7.4z" fill-rule="evenodd" fill="#800000"/>
<path d="M22.7 95.3h7.4v3.9h-7.4z" fill="none" stroke="#800000" stroke-width=".2"/>
<path d="M39 95.3h7.4v3.9h-7.4z" fill-rule="evenodd" fill="#800000"/>
<path d="M39 95.3h7.4v3.9h-7.4z" fill="none" stroke="#800000" stroke-width=".2"/>
<path d="M124.6 198.7h3.9v7.4h-3.9z" fill-rule="evenodd" fill="#800000"/>
<path d="M124.6 198.7h3.9v7.4h-3.9z" fill="none" stroke="#800000" stroke-width=".2"/>
<path d="M141.8 165.4h7.4v3.9h-7.4z" fill-rule="evenodd" fill="#800000"/>
<path d="M141.8 165.4h7.4v3.9h-7.4z" fill="none" stroke="#800000" stroke-width=".2"/>
<path d="M141.9 152.1h10.3v3.3h-10.3z" fill-rule="evenodd" fill="#800000"/>
<path d="M141.9 152.1h10.3v3.3h-10.3z" fill="none" stroke="#800000" stroke-width=".2"/>
<path d="M187 119.8h7.4v3.9h-7.4z" fill-rule="evenodd" fill="#800000"/>
<path d="M187 119.8h7.4v3.9h-7.4z" fill="none" stroke="#800000" stroke-width=".2"/>
<path d="M187 106.4h10.3v3.3h-10.3z" fill-rule="evenodd" fill="#800000"/>
<path d="M187 106.4h10.3v3.3h-10.3z" fill="none" stroke="#800000" stroke-width=".2"/>
<path d="M186.1 193h7.4v3.9h-7.4z" fill-rule="evenodd" fill="#800000"/>
<path d="M186.1 193h7.4v3.9h-7.4z" fill="none" stroke="#800000" stroke-width=".2"/>
<path d="M186.2 179.7h10.3v3.3h-10.3z" fill-rule="evenodd" fill="#800000"/>
<path d="M186.2 179.7h10.3v3.3h-10.3z" fill="none" stroke="#800000" stroke-width=".2"/>
<path d="M22.7 82h10.4v3.3h-10.4z" fill-rule="evenodd" fill="#800000"/>
<path d="M22.7 82h10.4v3.3h-10.4z" fill="none" stroke="#800000" stroke-width=".2"/>
<path d="M39.1 82h10.3v3.3h-10.3z" fill-rule="evenodd" fill="#800000"/>
<path d="M39.1 82h10.3v3.3h-10.3z" fill="none" stroke="#800000" stroke-width=".2"/>
<path d="M193.5 148.8h4.7v3.8h-4.7z" fill-rule="evenodd" fill="#800000"/>
<path d="M193.5 148.8h4.7v3.8h-4.7z" fill="none" stroke="#800000" stroke-width=".2"/>
<path d="M193.5 142.3h4.7v3.7h-4.7z" fill-rule="evenodd" fill="#800000"/>
<path d="M193.5 142.3h4.7v3.7h-4.7z" fill="none" stroke="#800000" stroke-width=".2"/>
<path d="M182.5 144.9h4.7v3.7h-4.7z" fill-rule="evenodd" fill="#800000"/>
<path d="M182.5 144.9h4.7v3.7h-4.7z" fill="none" stroke="#800000" stroke-width=".2"/>
<path d="M182.5 138.3h4.7v3.8h-4.7z" fill-rule="evenodd" fill="#800000"/>
<path d="M182.5 138.3h4.7v3.8h-4.7z" fill="none" stroke="#800000" stroke-width=".2"/>
<path d="M193.5 224.7h4.6v3.7h-4.6z" fill-rule="evenodd" fill="#800000"/>
<path d="M193.5 224.7h4.6v3.7h-4.6z" fill="none" stroke="#800000" stroke-width=".2"/>
<path d="M193.5 218.1h4.6v3.7h-4.6z" fill-rule="evenodd" fill="#800000"/>
<path d="M193.5 218.1h4.6v3.7h-4.6z" fill="none" stroke="#800000" stroke-width=".2"/>
<path d="M181.3 220.1h4.6v3.7h-4.6z" fill-rule="evenodd" fill="#800000"/>
<path d="M181.3 220.1h4.6v3.7h-4.6z" fill="none" stroke="#800000" stroke-width=".2"/>
<path d="M181.3 213.5h4.6v3.8h-4.6z" fill-rule="evenodd" fill="#800000"/>
<path d="M181.3 213.5h4.6v3.8h-4.6z" fill="none" stroke="#800000" stroke-width=".2"/>
<path d="M182.8 205.8h3.7v4.7h-3.7z" fill-rule="evenodd" fill="#800000"/>
<path d="M182.8 205.8h3.7v4.7h-3.7z" fill="none" stroke="#800000" stroke-width=".2"/>
<path d="M176.3 205.8h3.7v4.7h-3.7z" fill-rule="evenodd" fill="#800000"/>
<path d="M176.3 205.8h3.7v4.7h-3.7z" fill="none" stroke="#800000" stroke-width=".2"/>
<path d="M182.9 131.6h3.7v4.6h-3.7z" fill-rule="evenodd" fill="#800000"/>
<path d="M182.9 131.6h3.7v4.6h-3.7z" fill="none" stroke="#800000" stroke-width=".2"/>
<path d="M176.4 131.6h3.7v4.6h-3.7z" fill-rule="evenodd" fill="#800000"/>
<path d="M176.4 131.6h3.7v4.6h-3.7z" fill="none" stroke="#800000" stroke-width=".2"/>
<path d="M95.7 214.3h.9v.6h-.9z" fill-rule="evenodd" fill="#800000"/>
<path d="M95.7 214.3h.9v.6h-.9z" fill="none" stroke="#800000" stroke-width=".2"/>
<path d="M95.7 213.1h.9v.6h-.9z" fill-rule="evenodd" fill="#800000"/>
<path d="M95.7 213.1h.9v.6h-.9z" fill="none" stroke="#800000" stroke-width=".2"/>
<path d="M95.7 215.5h.9v.6h-.9z" fill-rule="evenodd" fill="#800000"/>
<path d="M95.7 215.5h.9v.6h-.9z" fill="none" stroke="#800000" stroke-width=".2"/>
<path d="M95.7 212h.9v.6h-.9z" fill-rule="evenodd" fill="#800000"/>
<path d="M95.7 212h.9v.6h-.9z" fill="none" stroke="#800000" stroke-width=".2"/>
<path d="M95.7 216.6h.9v.6h-.9z" fill-rule="evenodd" fill="#800000"/>
<path d="M95.7 216.6h.9v.6h-.9z" fill="none" stroke="#800000" stroke-width=".2"/>
<path d="M101.8 216.6h.9v.6h-.9z" fill-rule="evenodd" fill="#800000"/>
<path d="M101.8 216.6h.9v.6h-.9z" fill="none" stroke="#800000" stroke-width=".2"/>
<path d="M101.8 215.5h.9v.6h-.9z" fill-rule="evenodd" fill="#800000"/>
<path d="M101.8 215.5h.9v.6h-.9z" fill="none" stroke="#800000" stroke-width=".2"/>
<path d="M101.8 214.3h.9v.6h-.9z" fill-rule="evenodd" fill="#800000"/>
<path d="M101.8 214.3h.9v.6h-.9z" fill="none" stroke="#800000" stroke-width=".2"/>
<path d="M101.8 213.1h.9v.6h-.9z" fill-rule="evenodd" fill="#800000"/>
<path d="M101.8 213.1h.9v.6h-.9z" fill="none" stroke="#800000" stroke-width=".2"/>
<path d="M101.8 212h.9v.6h-.9z" fill-rule="evenodd" fill="#800000"/>
<path d="M101.8 212h.9v.6h-.9z" fill="none" stroke="#800000" stroke-width=".2"/>
<path d="M97.6 211.9h3l.4 .2v4.7l-.2 .4-3 .1-.4-.2-.1-4.8z" fill-rule="evenodd" fill="#800000"/>
<path d="M97.6 211.9h3l.4 .2v4.7l-.2 .4-3 .1-.4-.2-.1-4.8z" fill="none" stroke="#800000" stroke-width=".2"/>
<path d="M110.2 201.2h4.6v3.7h-4.6z" fill-rule="evenodd" fill="#800000"/>
<path d="M110.2 201.2h4.6v3.7h-4.6z" fill="none" stroke="#800000" stroke-width=".2"/>
<path d="M110.2 207.8h4.6v3.7h-4.6z" fill-rule="evenodd" fill="#800000"/>
<path d="M110.2 207.8h4.6v3.7h-4.6z" fill="none" stroke="#800000" stroke-width=".2"/>
<path d="M97.7 194h4.6v3.7h-4.6z" fill-rule="evenodd" fill="#800000"/>
<path d="M97.7 194h4.6v3.7h-4.6z" fill="none" stroke="#800000" stroke-width=".2"/>
<path d="M97.7 200.6h4.6v3.7h-4.6z" fill-rule="evenodd" fill="#800000"/>
<path d="M97.7 200.6h4.6v3.7h-4.6z" fill="none" stroke="#800000" stroke-width=".2"/>
<path d="M83.6 210.2h4.7v3.8h-4.7z" fill-rule="evenodd" fill="#800000"/>
<path d="M83.6 210.2h4.7v3.8h-4.7z" fill="none" stroke="#800000" stroke-width=".2"/>
<path d="M83.6 216.7h4.7v3.8h-4.7z" fill-rule="evenodd" fill="#800000"/>
<path d="M83.6 216.7h4.7v3.8h-4.7z" fill="none" stroke="#800000" stroke-width=".2"/>
<path d="M83.6 194h4.6v3.7h-4.6z" fill-rule="evenodd" fill="#800000"/>
<path d="M83.6 194h4.6v3.7h-4.6z" fill="none" stroke="#800000" stroke-width=".2"/>
<path d="M83.6 200.5h4.6v3.8h-4.6z" fill-rule="evenodd" fill="#800000"/>
<path d="M83.6 200.5h4.6v3.8h-4.6z" fill="none" stroke="#800000" stroke-width=".2"/>
<path d="M57.1 213.8h.9v.6h-.9z" fill-rule="evenodd" fill="#800000"/>
<path d="M57.1 213.8h.9v.6h-.9z" fill="none" stroke="#800000" stroke-width=".2"/>
<path d="M57.1 212.6h.9v.6h-.9z" fill-rule="evenodd" fill="#800000"/>
<path d="M57.1 212.6h.9v.6h-.9z" fill="none" stroke="#800000" stroke-width=".2"/>
<path d="M57.1 214.9h.9v.6h-.9z" fill-rule="evenodd" fill="#800000"/>
<path d="M57.1 214.9h.9v.6h-.9z" fill="none" stroke="#800000" stroke-width=".2"/>
<path d="M57.1 211.4h.9v.6h-.9z" fill-rule="evenodd" fill="#800000"/>
<path d="M57.1 211.4h.9v.6h-.9z" fill="none" stroke="#800000" stroke-width=".2"/>
<path d="M57.1 216.1h.9v.6h-.9z" fill-rule="evenodd" fill="#800000"/>
<path d="M57.1 216.1h.9v.6h-.9z" fill="none" stroke="#800000" stroke-width=".2"/>
<path d="M63.2 216.1h.9v.6h-.9z" fill-rule="evenodd" fill="#800000"/>
<path d="M63.2 216.1h.9v.6h-.9z" fill="none" stroke="#800000" stroke-width=".2"/>
<path d="M63.2 214.9h.9v.6h-.9z" fill-rule="evenodd" fill="#800000"/>
<path d="M63.2 214.9h.9v.6h-.9z" fill="none" stroke="#800000" stroke-width=".2"/>
<path d="M63.2 213.8h.9v.6h-.9z" fill-rule="evenodd" fill="#800000"/>
<path d="M63.2 213.8h.9v.6h-.9z" fill="none" stroke="#800000" stroke-width=".2"/>
<path d="M63.2 212.6h.9v.6h-.9z" fill-rule="evenodd" fill="#800000"/>
<path d="M63.2 212.6h.9v.6h-.9z" fill="none" stroke="#800000" stroke-width=".2"/>
<path d="M63.2 211.4h.9v.6h-.9z" fill-rule="evenodd" fill="#800000"/>
<path d="M63.2 211.4h.9v.6h-.9z" fill="none" stroke="#800000" stroke-width=".2"/>
<path d="M58.8 211.6l.4-.2h2.8l.4 .2 .1 4.7-.2 .4-3.1 .1-.4-.2z" fill-rule="evenodd" fill="#800000"/>
<path d="M58.8 211.6l.4-.2h2.8l.4 .2 .1 4.7-.2 .4-3.1 .1-.4-.2z" fill="none" stroke="#800000" stroke-width=".2"/>
<path d="M71.5 201.5h4.7v3.8h-4.7z" fill-rule="evenodd" fill="#800000"/>
<path d="M71.5 201.5h4.7v3.8h-4.7z" fill="none" stroke="#800000" stroke-width=".2"/>
<path d="M71.5 208.1h4.7v3.7h-4.7z" fill-rule="evenodd" fill="#800000"/>
<path d="M71.5 208.1h4.7v3.7h-4.7z" fill="none" stroke="#800000" stroke-width=".2"/>
<path d="M58.7 194.3h4.7v3.7h-4.7z" fill-rule="evenodd" fill="#800000"/>
<path d="M58.7 194.3h4.7v3.7h-4.7z" fill="none" stroke="#800000" stroke-width=".2"/>
<path d="M58.7 200.9h4.7v3.7h-4.7z" fill-rule="evenodd" fill="#800000"/>
<path d="M58.7 200.9h4.7v3.7h-4.7z" fill="none" stroke="#800000" stroke-width=".2"/>
<path d="M44.8 210h4.6v3.7h-4.6z" fill-rule="evenodd" fill="#800000"/>
<path d="M44.8 210h4.6v3.7h-4.6z" fill="none" stroke="#800000" stroke-width=".2"/>
<path d="M44.8 216.5h4.6v3.8h-4.6z" fill-rule="evenodd" fill="#800000"/>
<path d="M44.8 216.5h4.6v3.8h-4.6z" fill="none" stroke="#800000" stroke-width=".2"/>
<path d="M44.8 194.3h4.6v3.7h-4.6z" fill-rule="evenodd" fill="#800000"/>
<path d="M44.8 194.3h4.6v3.7h-4.6z" fill="none" stroke="#800000" stroke-width=".2"/>
<path d="M44.8 200.9h4.6v3.7h-4.6z" fill-rule="evenodd" fill="#800000"/>
<path d="M44.8 200.9h4.6v3.7h-4.6z" fill="none" stroke="#800000" stroke-width=".2"/>
<path d="M6.3 56.1h4.7v3.8h-4.7z" fill-rule="evenodd" fill="#800000"/>
<path d="M6.3 56.1h4.7v3.8h-4.7z" fill="none" stroke="#800000" stroke-width=".2"/>
<path d="M6.3 62.7h4.7v3.7h-4.7z" fill-rule="evenodd" fill="#800000"/>
<path d="M6.3 62.7h4.7v3.7h-4.7z" fill="none" stroke="#800000" stroke-width=".2"/>
<path d="M202 149.8h3.1v3.5h-3.1z" fill-rule="evenodd" fill="#800000"/>
<path d="M202 149.8h3.1v3.5h-3.1z" fill="none" stroke="#800000" stroke-width=".2"/>
<path d="M206.5 149.8h3v3.5h-3z" fill-rule="evenodd" fill="#800000"/>
<path d="M206.5 149.8h3v3.5h-3z" fill="none" stroke="#800000" stroke-width=".2"/>
<path d="M201.9 142.2h3.1v3.5h-3.1z" fill-rule="evenodd" fill="#800000"/>
<path d="M201.9 142.2h3.1v3.5h-3.1z" fill="none" stroke="#800000" stroke-width=".2"/>
<path d="M206.4 142.2h3v3.5h-3z" fill-rule="evenodd" fill="#800000"/>
<path d="M206.4 142.2h3v3.5h-3z" fill="none" stroke="#800000" stroke-width=".2"/>
<path d="M202 118.8h3v3.5h-3z" fill-rule="evenodd" fill="#800000"/>
<path d="M202 118.8h3v3.5h-3z" fill="none" stroke="#800000" stroke-width=".2"/>
<path d="M206.4 118.8h3.1v3.5h-3.1z" fill-rule="evenodd" fill="#800000"/>
<path d="M206.4 118.8h3.1v3.5h-3.1z" fill="none" stroke="#800000" stroke-width=".2"/>
<path d="M189.8 95.8h5.9v6.4h-5.9z" fill-rule="evenodd" fill="#800000"/>
<path d="M189.8 95.8h5.9v6.4h-5.9z" fill="none" stroke="#800000" stroke-width=".2"/>
<path d="M204.6 95.8h6v6.4h-6z" fill-rule="evenodd" fill="#800000"/>
<path d="M204.6 95.8h6v6.4h-6z" fill="none" stroke="#800000" stroke-width=".2"/>
<path d="M189.9 119.8h1.5v3.9h-1.5z" fill-rule="evenodd" fill="#800000"/>
<path d="M189.9 119.8h1.5v3.9h-1.5z" fill="none" stroke="#800000" stroke-width=".2"/>
<path d="M187 119.8h1.4v3.9h-1.4z" fill-rule="evenodd" fill="#800000"/>
<path d="M187 119.8h1.4v3.9h-1.4z" fill="none" stroke="#800000" stroke-width=".2"/>
<path d="M192.9 119.8h1.5v3.9h-1.5z" fill-rule="evenodd" fill="#800000"/>
<path d="M192.9 119.8h1.5v3.9h-1.5z" fill="none" stroke="#800000" stroke-width=".2"/>
<path d="M195.9 119.8h1.5v3.9h-1.5z" fill-rule="evenodd" fill="#800000"/>
<path d="M195.9 119.8h1.5v3.9h-1.5z" fill="none" stroke="#800000" stroke-width=".2"/>
<path d="M187.6 109h9.1v8.9h-9.1z" fill-rule="evenodd" fill="#800000"/>
<path d="M187.6 109h9.1v8.9h-9.1z" fill="none" stroke="#800000" stroke-width=".2"/>
<path d="M187 106.4h1.4v3.3h-1.4z" fill-rule="evenodd" fill="#800000"/>
<path d="M187 106.4h1.4v3.3h-1.4z" fill="none" stroke="#800000" stroke-width=".2"/>
<path d="M189.9 106.4h1.5v3.3h-1.5z" fill-rule="evenodd" fill="#800000"/>
<path d="M189.9 106.4h1.5v3.3h-1.5z" fill="none" stroke="#800000" stroke-width=".2"/>
<path d="M192.9 106.4h1.5v3.3h-1.5z" fill-rule="evenodd" fill="#800000"/>
<path d="M192.9 106.4h1.5v3.3h-1.5z" fill="none" stroke="#800000" stroke-width=".2"/>
<path d="M195.9 106.4h1.5v3.3h-1.5z" fill-rule="evenodd" fill="#800000"/>
<path d="M195.9 106.4h1.5v3.3h-1.5z" fill="none" stroke="#800000" stroke-width=".2"/>
<path d="M186.1 116.2h1.6v1h-1.6z" fill-rule="evenodd" fill="#800000"/>
<path d="M186.1 116.2h1.6v1h-1.6z" fill="none" stroke="#800000" stroke-width=".2"/>
<path d="M196.6 116.2h1.6v1h-1.6z" fill-rule="evenodd" fill="#800000"/>
<path d="M196.6 116.2h1.6v1h-1.6z" fill="none" stroke="#800000" stroke-width=".2"/>
<path d="M189.2 193h1.4v3.9h-1.4z" fill-rule="evenodd" fill="#800000"/>
<path d="M189.2 193h1.4v3.9h-1.4z" fill="none" stroke="#800000" stroke-width=".2"/>
<path d="M186.2 193h1.4v3.9h-1.4z" fill-rule="evenodd" fill="#800000"/>
<path d="M186.2 193h1.4v3.9h-1.4z" fill="none" stroke="#800000" stroke-width=".2"/>
<path d="M192.1 193h1.4v3.9h-1.4z" fill-rule="evenodd" fill="#800000"/>
<path d="M192.1 193h1.4v3.9h-1.4z" fill="none" stroke="#800000" stroke-width=".2"/>
<path d="M195.1 193h1.5v3.9h-1.5z" fill-rule="evenodd" fill="#800000"/>
<path d="M195.1 193h1.5v3.9h-1.5z" fill="none" stroke="#800000" stroke-width=".2"/>
<path d="M186.8 182.2h9.1v8.9h-9.1z" fill-rule="evenodd" fill="#800000"/>
<path d="M186.8 182.2h9.1v8.9h-9.1z" fill="none" stroke="#800000" stroke-width=".2"/>
<path d="M186.2 179.7h1.4v3.3h-1.4z" fill-rule="evenodd" fill="#800000"/>
<path d="M186.2 179.7h1.4v3.3h-1.4z" fill="none" stroke="#800000" stroke-width=".2"/>
<path d="M189.2 179.7h1.4v3.3h-1.4z" fill-rule="evenodd" fill="#800000"/>
<path d="M189.2 179.7h1.4v3.3h-1.4z" fill="none" stroke="#800000" stroke-width=".2"/>
<path d="M192.1 179.7h1.4v3.3h-1.4z" fill-rule="evenodd" fill="#800000"/>
<path d="M192.1 179.7h1.4v3.3h-1.4z" fill="none" stroke="#800000" stroke-width=".2"/>
<path d="M195.1 179.7h1.5v3.3h-1.5z" fill-rule="evenodd" fill="#800000"/>
<path d="M195.1 179.7h1.5v3.3h-1.5z" fill="none" stroke="#800000" stroke-width=".2"/>
<path d="M185.3 189.5h1.6v.9h-1.6z" fill-rule="evenodd" fill="#800000"/>
<path d="M185.3 189.5h1.6v.9h-1.6z" fill="none" stroke="#800000" stroke-width=".2"/>
<path d="M195.8 189.5h1.6v.9h-1.6z" fill-rule="evenodd" fill="#800000"/>
<path d="M195.8 189.5h1.6v.9h-1.6z" fill="none" stroke="#800000" stroke-width=".2"/>
<path d="M201.9 226.4h3.1v3.5h-3.1z" fill-rule="evenodd" fill="#800000"/>
<path d="M201.9 226.4h3.1v3.5h-3.1z" fill="none" stroke="#800000" stroke-width=".2"/>
<path d="M206.4 226.4h3v3.5h-3z" fill-rule="evenodd" fill="#800000"/>
<path d="M206.4 226.4h3v3.5h-3z" fill="none" stroke="#800000" stroke-width=".2"/>
<path d="M202 215.9h3v3.5h-3z" fill-rule="evenodd" fill="#800000"/>
<path d="M202 215.9h3v3.5h-3z" fill="none" stroke="#800000" stroke-width=".2"/>
<path d="M206.4 215.9h3.1v3.5h-3.1z" fill-rule="evenodd" fill="#800000"/>
<path d="M206.4 215.9h3.1v3.5h-3.1z" fill="none" stroke="#800000" stroke-width=".2"/>
<path d="M202 191.2h3.1v3.4h-3.1z" fill-rule="evenodd" fill="#800000"/>
<path d="M202 191.2h3.1v3.4h-3.1z" fill="none" stroke="#800000" stroke-width=".2"/>
<path d="M206.5 191.2h3v3.4h-3z" fill-rule="evenodd" fill="#800000"/>
<path d="M206.5 191.2h3v3.4h-3z" fill="none" stroke="#800000" stroke-width=".2"/>
<path d="M189.9 167.6h5.9v6.3h-5.9z" fill-rule="evenodd" fill="#800000"/>
<path d="M189.9 167.6h5.9v6.3h-5.9z" fill="none" stroke="#800000" stroke-width=".2"/>
<path d="M204.7 167.6h6v6.3h-6z" fill-rule="evenodd" fill="#800000"/>
<path d="M204.7 167.6h6v6.3h-6z" fill="none" stroke="#800000" stroke-width=".2"/>
<path d="M21.3 56h1.5v3.9h-1.5z" fill-rule="evenodd" fill="#800000"/>
<path d="M21.3 56h1.5v3.9h-1.5z" fill="none" stroke="#800000" stroke-width=".2"/>
<path d="M24.3 56h1.5v3.9h-1.5z" fill-rule="evenodd" fill="#800000"/>
<path d="M24.3 56h1.5v3.9h-1.5z" fill="none" stroke="#800000" stroke-width=".2"/>
<path d="M18.4 56h1.4v3.9h-1.4z" fill-rule="evenodd" fill="#800000"/>
<path d="M18.4 56h1.4v3.9h-1.4z" fill="none" stroke="#800000" stroke-width=".2"/>
<path d="M15.4 56h1.4v3.9h-1.4z" fill-rule="evenodd" fill="#800000"/>
<path d="M15.4 56h1.4v3.9h-1.4z" fill="none" stroke="#800000" stroke-width=".2"/>
<path d="M16 61.8h9.1v8.9h-9.1z" fill-rule="evenodd" fill="#800000"/>
<path d="M16 61.8h9.1v8.9h-9.1z" fill="none" stroke="#800000" stroke-width=".2"/>
<path d="M24.3 69.9h1.5v3.3h-1.5z" fill-rule="evenodd" fill="#800000"/>
<path d="M24.3 69.9h1.5v3.3h-1.5z" fill="none" stroke="#800000" stroke-width=".2"/>
<path d="M21.3 69.9h1.5v3.3h-1.5z" fill-rule="evenodd" fill="#800000"/>
<path d="M21.3 69.9h1.5v3.3h-1.5z" fill="none" stroke="#800000" stroke-width=".2"/>
<path d="M18.4 69.9h1.4v3.3h-1.4z" fill-rule="evenodd" fill="#800000"/>
<path d="M18.4 69.9h1.4v3.3h-1.4z" fill="none" stroke="#800000" stroke-width=".2"/>
<path d="M15.4 69.9h1.4v3.3h-1.4z" fill-rule="evenodd" fill="#800000"/>
<path d="M15.4 69.9h1.4v3.3h-1.4z" fill="none" stroke="#800000" stroke-width=".2"/>
<path d="M25 62.5h1.6v.9h-1.6z" fill-rule="evenodd" fill="#800000"/>
<path d="M25 62.5h1.6v.9h-1.6z" fill="none" stroke="#800000" stroke-width=".2"/>
<path d="M14.6 62.5h1.6v.9h-1.6z" fill-rule="evenodd" fill="#800000"/>
<path d="M14.6 62.5h1.6v.9h-1.6z" fill="none" stroke="#800000" stroke-width=".2"/>
<path d="M124.6 201.7h3.9v1.5h-3.9z" fill-rule="evenodd" fill="#800000"/>
<path d="M124.6 201.7h3.9v1.5h-3.9z" fill="none" stroke="#800000" stroke-width=".2"/>
<path d="M124.6 198.7h3.9v1.5h-3.9z" fill-rule="evenodd" fill="#800000"/>
<path d="M124.6 198.7h3.9v1.5h-3.9z" fill="none" stroke="#800000" stroke-width=".2"/>
<path d="M124.6 204.7h3.9v1.4h-3.9z" fill-rule="evenodd" fill="#800000"/>
<path d="M124.6 204.7h3.9v1.4h-3.9z" fill="none" stroke="#800000" stroke-width=".2"/>
<path d="M124.6 207.6h3.9v1.5h-3.9z" fill-rule="evenodd" fill="#800000"/>
<path d="M124.6 207.6h3.9v1.5h-3.9z" fill="none" stroke="#800000" stroke-width=".2"/>
<path d="M130.4 199.3h8.9v9.1h-8.9z" fill-rule="evenodd" fill="#800000"/>
<path d="M130.4 199.3h8.9v9.1h-8.9z" fill="none" stroke="#800000" stroke-width=".2"/>
<path d="M138.6 198.7h3.3v1.5h-3.3z" fill-rule="evenodd" fill="#800000"/>
<path d="M138.6 198.7h3.3v1.5h-3.3z" fill="none" stroke="#800000" stroke-width=".2"/>
<path d="M138.6 201.7h3.3v1.5h-3.3z" fill-rule="evenodd" fill="#800000"/>
<path d="M138.6 201.7h3.3v1.5h-3.3z" fill="none" stroke="#800000" stroke-width=".2"/>
<path d="M138.6 204.7h3.3v1.4h-3.3z" fill-rule="evenodd" fill="#800000"/>
<path d="M138.6 204.7h3.3v1.4h-3.3z" fill="none" stroke="#800000" stroke-width=".2"/>
<path d="M138.6 207.6h3.3v1.5h-3.3z" fill-rule="evenodd" fill="#800000"/>
<path d="M138.6 207.6h3.3v1.5h-3.3z" fill="none" stroke="#800000" stroke-width=".2"/>
<path d="M131.1 197.9h1v1.6h-1z" fill-rule="evenodd" fill="#800000"/>
<path d="M131.1 197.9h1v1.6h-1z" fill="none" stroke="#800000" stroke-width=".2"/>
<path d="M131.1 208.3h1v1.6h-1z" fill-rule="evenodd" fill="#800000"/>
<path d="M131.1 208.3h1v1.6h-1z" fill="none" stroke="#800000" stroke-width=".2"/>
<path d="M126.3 211.2h4.6v3.7h-4.6z" fill-rule="evenodd" fill="#800000"/>
<path d="M126.3 211.2h4.6v3.7h-4.6z" fill="none" stroke="#800000" stroke-width=".2"/>
<path d="M126.3 217.8h4.6v3.7h-4.6z" fill-rule="evenodd" fill="#800000"/>
<path d="M126.3 217.8h4.6v3.7h-4.6z" fill="none" stroke="#800000" stroke-width=".2"/>
<path d="M202 203.3h3.1v3.5h-3.1z" fill-rule="evenodd" fill="#800000"/>
<path d="M202 203.3h3.1v3.5h-3.1z" fill="none" stroke="#800000" stroke-width=".2"/>
<path d="M206.5 203.3h3v3.5h-3z" fill-rule="evenodd" fill="#800000"/>
<path d="M206.5 203.3h3v3.5h-3z" fill="none" stroke="#800000" stroke-width=".2"/>
<path d="M201.9 129.7h3.1v3.5h-3.1z" fill-rule="evenodd" fill="#800000"/>
<path d="M201.9 129.7h3.1v3.5h-3.1z" fill="none" stroke="#800000" stroke-width=".2"/>
<path d="M206.4 129.7h3v3.5h-3z" fill-rule="evenodd" fill="#800000"/>
<path d="M206.4 129.7h3v3.5h-3z" fill="none" stroke="#800000" stroke-width=".2"/>
<path d="M152.2 125.3h12.9v9h-12.9z" fill-rule="evenodd" fill="#800000"/>
<path d="M152.2 125.3h12.9v9h-12.9z" fill="none" stroke="#800000" stroke-width=".2"/>
<path d="M152.2 105.9h12.9v9h-12.9z" fill-rule="evenodd" fill="#800000"/>
<path d="M152.2 105.9h12.9v9h-12.9z" fill="none" stroke="#800000" stroke-width=".2"/>
<path d="M152.3 198.8h12.8v9h-12.8z" fill-rule="evenodd" fill="#800000"/>
<path d="M152.3 198.8h12.8v9h-12.8z" fill="none" stroke="#800000" stroke-width=".2"/>
<path d="M152.3 179.4h12.8v8.9h-12.8z" fill-rule="evenodd" fill="#800000"/>
<path d="M152.3 179.4h12.8v8.9h-12.8z" fill="none" stroke="#800000" stroke-width=".2"/>
<path d="M155.7 143.6h5.9v6.4h-5.9z" fill-rule="evenodd" fill="#800000"/>
<path d="M155.7 143.6h5.9v6.4h-5.9z" fill="none" stroke="#800000" stroke-width=".2"/>
<path d="M170.6 143.6h5.9v6.4h-5.9z" fill-rule="evenodd" fill="#800000"/>
<path d="M170.6 143.6h5.9v6.4h-5.9z" fill="none" stroke="#800000" stroke-width=".2"/>
<path d="M155.7 218.2h6v6.3h-6z" fill-rule="evenodd" fill="#800000"/>
<path d="M155.7 218.2h6v6.3h-6z" fill="none" stroke="#800000" stroke-width=".2"/>
<path d="M170.6 218.2h5.9v6.3h-5.9z" fill-rule="evenodd" fill="#800000"/>
<path d="M170.6 218.2h5.9v6.3h-5.9z" fill="none" stroke="#800000" stroke-width=".2"/>
<path d="M148.8 218.9h3.3v4.9h-3.3z" fill-rule="evenodd" fill="#800000"/>
<path d="M148.8 218.9h3.3v4.9h-3.3z" fill="none" stroke="#800000" stroke-width=".2"/>
<path d="M138.6 218.9h3.3v4.9h-3.3z" fill-rule="evenodd" fill="#800000"/>
<path d="M138.6 218.9h3.3v4.9h-3.3z" fill="none" stroke="#800000" stroke-width=".2"/>
<path d="M173.7 170.9h3.3v4.9h-3.3z" fill-rule="evenodd" fill="#800000"/>
<path d="M173.7 170.9h3.3v4.9h-3.3z" fill="none" stroke="#800000" stroke-width=".2"/>
<path d="M184 170.9h3.3v4.9h-3.3z" fill-rule="evenodd" fill="#800000"/>
<path d="M184 170.9h3.3v4.9h-3.3z" fill="none" stroke="#800000" stroke-width=".2"/>
<path d="M149.9 144.4h3.3v4.9h-3.3z" fill-rule="evenodd" fill="#800000"/>
<path d="M149.9 144.4h3.3v4.9h-3.3z" fill="none" stroke="#800000" stroke-width=".2"/>
<path d="M139.6 144.4h3.3v4.9h-3.3z" fill-rule="evenodd" fill="#800000"/>
<path d="M139.6 144.4h3.3v4.9h-3.3z" fill="none" stroke="#800000" stroke-width=".2"/>
<path d="M174 98.3h3.3v4.9h-3.3z" fill-rule="evenodd" fill="#800000"/>
<path d="M174 98.3h3.3v4.9h-3.3z" fill="none" stroke="#800000" stroke-width=".2"/>
<path d="M184.3 98.3h3.3v4.9h-3.3z" fill-rule="evenodd" fill="#800000"/>
<path d="M184.3 98.3h3.3v4.9h-3.3z" fill="none" stroke="#800000" stroke-width=".2"/>
<path d="M194.9 127.3h1v2.9h-1z" fill-rule="evenodd" fill="#800000"/>
<path d="M194.9 127.3h1v2.9h-1z" fill="none" stroke="#800000" stroke-width=".2"/>
<path d="M196.5 127.3h.9v2.9h-.9z" fill-rule="evenodd" fill="#800000"/>
<path d="M196.5 127.3h.9v2.9h-.9z" fill="none" stroke="#800000" stroke-width=".2"/>
<path d="M193.4 127.3h1v2.9h-1z" fill-rule="evenodd" fill="#800000"/>
<path d="M193.4 127.3h1v2.9h-1z" fill="none" stroke="#800000" stroke-width=".2"/>
<path d="M191.9 127.3h.9v2.9h-.9z" fill-rule="evenodd" fill="#800000"/>
<path d="M191.9 127.3h.9v2.9h-.9z" fill="none" stroke="#800000" stroke-width=".2"/>
<path d="M191.9 133.4h.9v2.9h-.9z" fill-rule="evenodd" fill="#800000"/>
<path d="M191.9 133.4h.9v2.9h-.9z" fill="none" stroke="#800000" stroke-width=".2"/>
<path d="M193.4 133.4h1v2.9h-1z" fill-rule="evenodd" fill="#800000"/>
<path d="M193.4 133.4h1v2.9h-1z" fill="none" stroke="#800000" stroke-width=".2"/>
<path d="M194.9 133.4h1v2.9h-1z" fill-rule="evenodd" fill="#800000"/>
<path d="M194.9 133.4h1v2.9h-1z" fill="none" stroke="#800000" stroke-width=".2"/>
<path d="M196.5 133.4h.9v2.9h-.9z" fill-rule="evenodd" fill="#800000"/>
<path d="M196.5 133.4h.9v2.9h-.9z" fill="none" stroke="#800000" stroke-width=".2"/>
<path d="M194.7 200.7h1v2.8h-1z" fill-rule="evenodd" fill="#800000"/>
<path d="M194.7 200.7h1v2.8h-1z" fill="none" stroke="#800000" stroke-width=".2"/>
<path d="M196.3 200.7h.9v2.8h-.9z" fill-rule="evenodd" fill="#800000"/>
<path d="M196.3 200.7h.9v2.8h-.9z" fill="none" stroke="#800000" stroke-width=".2"/>
<path d="M193.2 200.7h.9v2.8h-.9z" fill-rule="evenodd" fill="#800000"/>
<path d="M193.2 200.7h.9v2.8h-.9z" fill="none" stroke="#800000" stroke-width=".2"/>
<path d="M191.7 200.7h.9v2.8h-.9z" fill-rule="evenodd" fill="#800000"/>
<path d="M191.7 200.7h.9v2.8h-.9z" fill="none" stroke="#800000" stroke-width=".2"/>
<path d="M191.7 206.8h.9v2.9h-.9z" fill-rule="evenodd" fill="#800000"/>
<path d="M191.7 206.8h.9v2.9h-.9z" fill="none" stroke="#800000" stroke-width=".2"/>
<path d="M193.2 206.8h.9v2.9h-.9z" fill-rule="evenodd" fill="#800000"/>
<path d="M193.2 206.8h.9v2.9h-.9z" fill="none" stroke="#800000" stroke-width=".2"/>
<path d="M194.7 206.8h1v2.9h-1z" fill-rule="evenodd" fill="#800000"/>
<path d="M194.7 206.8h1v2.9h-1z" fill="none" stroke="#800000" stroke-width=".2"/>
<path d="M196.3 206.8h.9v2.9h-.9z" fill-rule="evenodd" fill="#800000"/>
<path d="M196.3 206.8h.9v2.9h-.9z" fill="none" stroke="#800000" stroke-width=".2"/>
<path d="M90.6 83.4h4.8v1.5h-4.8z" fill-rule="evenodd" fill="#800000"/>
<path d="M90.6 83.4h4.8v1.5h-4.8z" fill="none" stroke="#800000" stroke-width=".2"/>
<path d="M105 83.4h4.8v1.5h-4.8z" fill-rule="evenodd" fill="#800000"/>
<path d="M105 83.4h4.8v1.5h-4.8z" fill="none" stroke="#800000" stroke-width=".2"/>
<path d="M90.6 86.4h4.8v1.5h-4.8z" fill-rule="evenodd" fill="#800000"/>
<path d="M90.6 86.4h4.8v1.5h-4.8z" fill="none" stroke="#800000" stroke-width=".2"/>
<path d="M90.6 89.3h4.8v1.5h-4.8z" fill-rule="evenodd" fill="#800000"/>
<path d="M90.6 89.3h4.8v1.5h-4.8z" fill="none" stroke="#800000" stroke-width=".2"/>
<path d="M105 86.4h4.8v1.5h-4.8z" fill-rule="evenodd" fill="#800000"/>
<path d="M105 86.4h4.8v1.5h-4.8z" fill="none" stroke="#800000" stroke-width=".2"/>
<path d="M105 89.3h4.8v1.5h-4.8z" fill-rule="evenodd" fill="#800000"/>
<path d="M105 89.3h4.8v1.5h-4.8z" fill="none" stroke="#800000" stroke-width=".2"/>
<path d="M90.6 92.3h4.8v1.6h-4.8z" fill-rule="evenodd" fill="#800000"/>
<path d="M90.6 92.3h4.8v1.6h-4.8z" fill="none" stroke="#800000" stroke-width=".2"/>
<path d="M105 92.3h4.8v1.6h-4.8z" fill-rule="evenodd" fill="#800000"/>
<path d="M105 92.3h4.8v1.6h-4.8z" fill="none" stroke="#800000" stroke-width=".2"/>
<path d="M132.9 84.5h4.6v3.7h-4.6z" fill-rule="evenodd" fill="#800000"/>
<path d="M132.9 84.5h4.6v3.7h-4.6z" fill="none" stroke="#800000" stroke-width=".2"/>
<path d="M132.9 91h4.6v3.7h-4.6z" fill-rule="evenodd" fill="#800000"/>
<path d="M132.9 91h4.6v3.7h-4.6z" fill="none" stroke="#800000" stroke-width=".2"/>
<path d="M121.2 93.7h3.8v4.6h-3.8z" fill-rule="evenodd" fill="#800000"/>
<path d="M121.2 93.7h3.8v4.6h-3.8z" fill="none" stroke="#800000" stroke-width=".2"/>
<path d="M127.8 93.7h3.7v4.6h-3.7z" fill-rule="evenodd" fill="#800000"/>
<path d="M127.8 93.7h3.7v4.6h-3.7z" fill="none" stroke="#800000" stroke-width=".2"/>
<path d="M121.3 80.2h3.8v4.7h-3.8z" fill-rule="evenodd" fill="#800000"/>
<path d="M121.3 80.2h3.8v4.7h-3.8z" fill="none" stroke="#800000" stroke-width=".2"/>
<path d="M127.9 80.2h3.7v4.7h-3.7z" fill-rule="evenodd" fill="#800000"/>
<path d="M127.9 80.2h3.7v4.7h-3.7z" fill="none" stroke="#800000" stroke-width=".2"/>
<path d="M114.9 85.5h3.5v3.1h-3.5z" fill-rule="evenodd" fill="#800000"/>
<path d="M114.9 85.5h3.5v3.1h-3.5z" fill="none" stroke="#800000" stroke-width=".2"/>
<path d="M114.9 81.1h3.5v3h-3.5z" fill-rule="evenodd" fill="#800000"/>
<path d="M114.9 81.1h3.5v3h-3.5z" fill="none" stroke="#800000" stroke-width=".2"/>
<path d="M110.1 95h3v3.5h-3z" fill-rule="evenodd" fill="#800000"/>
<path d="M110.1 95h3v3.5h-3z" fill="none" stroke="#800000" stroke-width=".2"/>
<path d="M114.5 95h3.1v3.5h-3.1z" fill-rule="evenodd" fill="#800000"/>
<path d="M114.5 95h3.1v3.5h-3.1z" fill="none" stroke="#800000" stroke-width=".2"/>
<path d="M53.2 158.4h3.7v4.6h-3.7z" fill-rule="evenodd" fill="#800000"/>
<path d="M53.2 158.4h3.7v4.6h-3.7z" fill="none" stroke="#800000" stroke-width=".2"/>
<path d="M59.7 158.4h3.7v4.6h-3.7z" fill-rule="evenodd" fill="#800000"/>
<path d="M59.7 158.4h3.7v4.6h-3.7z" fill="none" stroke="#800000" stroke-width=".2"/>
<path d="M56.4 177.1h4.7v3.7h-4.7z" fill-rule="evenodd" fill="#800000"/>
<path d="M56.4 177.1h4.7v3.7h-4.7z" fill="none" stroke="#800000" stroke-width=".2"/>
<path d="M56.4 170.6h4.7v3.7h-4.7z" fill-rule="evenodd" fill="#800000"/>
<path d="M56.4 170.6h4.7v3.7h-4.7z" fill="none" stroke="#800000" stroke-width=".2"/>
<path d="M70.5 182.4h3.7v4.7h-3.7z" fill-rule="evenodd" fill="#800000"/>
<path d="M70.5 182.4h3.7v4.7h-3.7z" fill="none" stroke="#800000" stroke-width=".2"/>
<path d="M63.9 182.4h3.7v4.7h-3.7z" fill-rule="evenodd" fill="#800000"/>
<path d="M63.9 182.4h3.7v4.7h-3.7z" fill="none" stroke="#800000" stroke-width=".2"/>
<path d="M25.7 95.3h1.4v3.9h-1.4z" fill-rule="evenodd" fill="#800000"/>
<path d="M25.7 95.3h1.4v3.9h-1.4z" fill="none" stroke="#800000" stroke-width=".2"/>
<path d="M22.7 95.3h1.4v3.9h-1.4z" fill-rule="evenodd" fill="#800000"/>
<path d="M22.7 95.3h1.4v3.9h-1.4z" fill="none" stroke="#800000" stroke-width=".2"/>
<path d="M28.7 95.3h1.4v3.9h-1.4z" fill-rule="evenodd" fill="#800000"/>
<path d="M28.7 95.3h1.4v3.9h-1.4z" fill="none" stroke="#800000" stroke-width=".2"/>
<path d="M31.7 95.3h1.4v3.9h-1.4z" fill-rule="evenodd" fill="#800000"/>
<path d="M31.7 95.3h1.4v3.9h-1.4z" fill="none" stroke="#800000" stroke-width=".2"/>
<path d="M23.3 84.5h9.2v8.9h-9.2z" fill-rule="evenodd" fill="#800000"/>
<path d="M23.3 84.5h9.2v8.9h-9.2z" fill="none" stroke="#800000" stroke-width=".2"/>
<path d="M22.7 82h1.4v3.3h-1.4z" fill-rule="evenodd" fill="#800000"/>
<path d="M22.7 82h1.4v3.3h-1.4z" fill="none" stroke="#800000" stroke-width=".2"/>
<path d="M25.7 82h1.4v3.3h-1.4z" fill-rule="evenodd" fill="#800000"/>
<path d="M25.7 82h1.4v3.3h-1.4z" fill="none" stroke="#800000" stroke-width=".2"/>
<path d="M28.7 82h1.4v3.3h-1.4z" fill-rule="evenodd" fill="#800000"/>
<path d="M28.7 82h1.4v3.3h-1.4z" fill="none" stroke="#800000" stroke-width=".2"/>
<path d="M31.7 82h1.4v3.3h-1.4z" fill-rule="evenodd" fill="#800000"/>
<path d="M31.7 82h1.4v3.3h-1.4z" fill="none" stroke="#800000" stroke-width=".2"/>
<path d="M21.9 91.8h1.6v.9h-1.6z" fill-rule="evenodd" fill="#800000"/>
<path d="M21.9 91.8h1.6v.9h-1.6z" fill="none" stroke="#800000" stroke-width=".2"/>
<path d="M32.3 91.8h1.6v.9h-1.6z" fill-rule="evenodd" fill="#800000"/>
<path d="M32.3 91.8h1.6v.9h-1.6z" fill="none" stroke="#800000" stroke-width=".2"/>
<path d="M77.6 172.1h3.4v3.1h-3.4z" fill-rule="evenodd" fill="#800000"/>
<path d="M77.6 172.1h3.4v3.1h-3.4z" fill="none" stroke="#800000" stroke-width=".2"/>
<path d="M77.6 176.6h3.4v3h-3.4z" fill-rule="evenodd" fill="#800000"/>
<path d="M77.6 176.6h3.4v3h-3.4z" fill="none" stroke="#800000" stroke-width=".2"/>
<path d="M96.1 73.2h2.8v1.3h-2.8z" fill-rule="evenodd" fill="#800000"/>
<path d="M96.1 73.2h2.8v1.3h-2.8z" fill="none" stroke="#800000" stroke-width=".2"/>
<path d="M96.1 71h2.8v1.2h-2.8z" fill-rule="evenodd" fill="#800000"/>
<path d="M96.1 71h2.8v1.2h-2.8z" fill="none" stroke="#800000" stroke-width=".2"/>
<path d="M96.1 68.7h2.8v1.3h-2.8z" fill-rule="evenodd" fill="#800000"/>
<path d="M96.1 68.7h2.8v1.3h-2.8z" fill="none" stroke="#800000" stroke-width=".2"/>
<path d="M90 68.7h2.8v1.3h-2.8z" fill-rule="evenodd" fill="#800000"/>
<path d="M90 68.7h2.8v1.3h-2.8z" fill="none" stroke="#800000" stroke-width=".2"/>
<path d="M90 73.2h2.8v1.3h-2.8z" fill-rule="evenodd" fill="#800000"/>
<path d="M90 73.2h2.8v1.3h-2.8z" fill="none" stroke="#800000" stroke-width=".2"/>
<path d="M88.1 158h3.7v4.7h-3.7z" fill-rule="evenodd" fill="#800000"/>
<path d="M88.1 158h3.7v4.7h-3.7z" fill="none" stroke="#800000" stroke-width=".2"/>
<path d="M94.6 158h3.7v4.7h-3.7z" fill-rule="evenodd" fill="#800000"/>
<path d="M94.6 158h3.7v4.7h-3.7z" fill="none" stroke="#800000" stroke-width=".2"/>
<path d="M87.2 176.6h4.7v3.7h-4.7z" fill-rule="evenodd" fill="#800000"/>
<path d="M87.2 176.6h4.7v3.7h-4.7z" fill="none" stroke="#800000" stroke-width=".2"/>
<path d="M87.2 170.1h4.7v3.7h-4.7z" fill-rule="evenodd" fill="#800000"/>
<path d="M87.2 170.1h4.7v3.7h-4.7z" fill="none" stroke="#800000" stroke-width=".2"/>
<path d="M103.7 181.9h3.7v4.7h-3.7z" fill-rule="evenodd" fill="#800000"/>
<path d="M103.7 181.9h3.7v4.7h-3.7z" fill="none" stroke="#800000" stroke-width=".2"/>
<path d="M97.2 181.9h3.7v4.7h-3.7z" fill-rule="evenodd" fill="#800000"/>
<path d="M97.2 181.9h3.7v4.7h-3.7z" fill="none" stroke="#800000" stroke-width=".2"/>
<path d="M42 95.3h1.4v3.9h-1.4z" fill-rule="evenodd" fill="#800000"/>
<path d="M42 95.3h1.4v3.9h-1.4z" fill="none" stroke="#800000" stroke-width=".2"/>
<path d="M39 95.3h1.4v3.9h-1.4z" fill-rule="evenodd" fill="#800000"/>
<path d="M39 95.3h1.4v3.9h-1.4z" fill="none" stroke="#800000" stroke-width=".2"/>
<path d="M45 95.3h1.4v3.9h-1.4z" fill-rule="evenodd" fill="#800000"/>
<path d="M45 95.3h1.4v3.9h-1.4z" fill="none" stroke="#800000" stroke-width=".2"/>
<path d="M47.9 95.3h1.5v3.9h-1.5z" fill-rule="evenodd" fill="#800000"/>
<path d="M47.9 95.3h1.5v3.9h-1.5z" fill="none" stroke="#800000" stroke-width=".2"/>
<path d="M39.6 84.5h9.2v8.9h-9.2z" fill-rule="evenodd" fill="#800000"/>
<path d="M39.6 84.5h9.2v8.9h-9.2z" fill="none" stroke="#800000" stroke-width=".2"/>
<path d="M39 82h1.4v3.3h-1.4z" fill-rule="evenodd" fill="#800000"/>
<path d="M39 82h1.4v3.3h-1.4z" fill="none" stroke="#800000" stroke-width=".2"/>
<path d="M42 82h1.4v3.3h-1.4z" fill-rule="evenodd" fill="#800000"/>
<path d="M42 82h1.4v3.3h-1.4z" fill="none" stroke="#800000" stroke-width=".2"/>
<path d="M45 82h1.4v3.3h-1.4z" fill-rule="evenodd" fill="#800000"/>
<path d="M45 82h1.4v3.3h-1.4z" fill="none" stroke="#800000" stroke-width=".2"/>
<path d="M47.9 82h1.5v3.3h-1.5z" fill-rule="evenodd" fill="#800000"/>
<path d="M47.9 82h1.5v3.3h-1.5z" fill="none" stroke="#800000" stroke-width=".2"/>
<path d="M38.2 91.8h1.6v.9h-1.6z" fill-rule="evenodd" fill="#800000"/>
<path d="M38.2 91.8h1.6v.9h-1.6z" fill="none" stroke="#800000" stroke-width=".2"/>
<path d="M48.6 91.8h1.6v.9h-1.6z" fill-rule="evenodd" fill="#800000"/>
<path d="M48.6 91.8h1.6v.9h-1.6z" fill="none" stroke="#800000" stroke-width=".2"/>
<path d="M110.8 172h3.5v3h-3.5z" fill-rule="evenodd" fill="#800000"/>
<path d="M110.8 172h3.5v3h-3.5z" fill="none" stroke="#800000" stroke-width=".2"/>
<path d="M110.8 176.4h3.5v3.1h-3.5z" fill-rule="evenodd" fill="#800000"/>
<path d="M110.8 176.4h3.5v3.1h-3.5z" fill="none" stroke="#800000" stroke-width=".2"/>
<path d="M114.4 134.4h2.5v1h-2.5z" fill-rule="evenodd" fill="#800000"/>
<path d="M114.4 134.4h2.5v1h-2.5z" fill="none" stroke="#800000" stroke-width=".2"/>
<path d="M114.4 132.8h2.5v1.1h-2.5z" fill-rule="evenodd" fill="#800000"/>
<path d="M114.4 132.8h2.5v1.1h-2.5z" fill="none" stroke="#800000" stroke-width=".2"/>
<path d="M114.4 131.4h2.5v1h-2.5z" fill-rule="evenodd" fill="#800000"/>
<path d="M114.4 131.4h2.5v1h-2.5z" fill="none" stroke="#800000" stroke-width=".2"/>
<path d="M114.4 129.8h2.5v1h-2.5z" fill-rule="evenodd" fill="#800000"/>
<path d="M114.4 129.8h2.5v1h-2.5z" fill="none" stroke="#800000" stroke-width=".2"/>
<path d="M114.4 128.3h2.5v1h-2.5z" fill-rule="evenodd" fill="#800000"/>
<path d="M114.4 128.3h2.5v1h-2.5z" fill="none" stroke="#800000" stroke-width=".2"/>
<path d="M114.4 126.7h2.5v1.1h-2.5z" fill-rule="evenodd" fill="#800000"/>
<path d="M114.4 126.7h2.5v1.1h-2.5z" fill="none" stroke="#800000" stroke-width=".2"/>
<path d="M114.4 125.2h2.5v1h-2.5z" fill-rule="evenodd" fill="#800000"/>
<path d="M114.4 125.2h2.5v1h-2.5z" fill="none" stroke="#800000" stroke-width=".2"/>
<path d="M114.4 123.7h2.5v1h-2.5z" fill-rule="evenodd" fill="#800000"/>
<path d="M114.4 123.7h2.5v1h-2.5z" fill="none" stroke="#800000" stroke-width=".2"/>
<path d="M114.4 122.2h2.5v1h-2.5z" fill-rule="evenodd" fill="#800000"/>
<path d="M114.4 122.2h2.5v1h-2.5z" fill="none" stroke="#800000" stroke-width=".2"/>
<path d="M114.4 120.7h2.5v1h-2.5z" fill-rule="evenodd" fill="#800000"/>
<path d="M114.4 120.7h2.5v1h-2.5z" fill="none" stroke="#800000" stroke-width=".2"/>
<path d="M101.4 120.7h2.5v1h-2.5z" fill-rule="evenodd" fill="#800000"/>
<path d="M101.4 120.7h2.5v1h-2.5z" fill="none" stroke="#800000" stroke-width=".2"/>
<path d="M101.4 122.2h2.5v1h-2.5z" fill-rule="evenodd" fill="#800000"/>
<path d="M101.4 122.2h2.5v1h-2.5z" fill="none" stroke="#800000" stroke-width=".2"/>
<path d="M101.4 123.7h2.5v1h-2.5z" fill-rule="evenodd" fill="#800000"/>
<path d="M101.4 123.7h2.5v1h-2.5z" fill="none" stroke="#800000" stroke-width=".2"/>
<path d="M101.4 125.2h2.5v1h-2.5z" fill-rule="evenodd" fill="#800000"/>
<path d="M101.4 125.2h2.5v1h-2.5z" fill="none" stroke="#800000" stroke-width=".2"/>
<path d="M101.4 126.7h2.5v1.1h-2.5z" fill-rule="evenodd" fill="#800000"/>
<path d="M101.4 126.7h2.5v1.1h-2.5z" fill="none" stroke="#800000" stroke-width=".2"/>
<path d="M101.4 128.3h2.5v1h-2.5z" fill-rule="evenodd" fill="#800000"/>
<path d="M101.4 128.3h2.5v1h-2.5z" fill="none" stroke="#800000" stroke-width=".2"/>
<path d="M101.4 129.8h2.5v1h-2.5z" fill-rule="evenodd" fill="#800000"/>
<path d="M101.4 129.8h2.5v1h-2.5z" fill="none" stroke="#800000" stroke-width=".2"/>
<path d="M101.4 131.3h2.5v1h-2.5z" fill-rule="evenodd" fill="#800000"/>
<path d="M101.4 131.3h2.5v1h-2.5z" fill="none" stroke="#800000" stroke-width=".2"/>
<path d="M101.4 132.8h2.5v1.1h-2.5z" fill-rule="evenodd" fill="#800000"/>
<path d="M101.4 132.8h2.5v1.1h-2.5z" fill="none" stroke="#800000" stroke-width=".2"/>
<path d="M101.4 134.4h2.5v1h-2.5z" fill-rule="evenodd" fill="#800000"/>
<path d="M101.4 134.4h2.5v1h-2.5z" fill="none" stroke="#800000" stroke-width=".2"/>
<path d="M122.9 125.3h3.5v3.1h-3.5z" fill-rule="evenodd" fill="#800000"/>
<path d="M122.9 125.3h3.5v3.1h-3.5z" fill="none" stroke="#800000" stroke-width=".2"/>
<path d="M122.9 120.9h3.5v3h-3.5z" fill-rule="evenodd" fill="#800000"/>
<path d="M122.9 120.9h3.5v3h-3.5z" fill="none" stroke="#800000" stroke-width=".2"/>
<path d="M118.3 125.3h3.5v3.1h-3.5z" fill-rule="evenodd" fill="#800000"/>
<path d="M118.3 125.3h3.5v3.1h-3.5z" fill="none" stroke="#800000" stroke-width=".2"/>
<path d="M118.3 120.9h3.5v3h-3.5z" fill-rule="evenodd" fill="#800000"/>
<path d="M118.3 120.9h3.5v3h-3.5z" fill="none" stroke="#800000" stroke-width=".2"/>
<path d="M89.1 135.3h4.7v3.8h-4.7z" fill-rule="evenodd" fill="#800000"/>
<path d="M89.1 135.3h4.7v3.8h-4.7z" fill="none" stroke="#800000" stroke-width=".2"/>
<path d="M89.1 128.8h4.7v3.7h-4.7z" fill-rule="evenodd" fill="#800000"/>
<path d="M89.1 128.8h4.7v3.7h-4.7z" fill="none" stroke="#800000" stroke-width=".2"/>
<path d="M164.2 87.5h3.3v.7h-3.3z" fill-rule="evenodd" fill="#800000"/>
<path d="M164.2 87.5h3.3v.7h-3.3z" fill="none" stroke="#800000" stroke-width=".2"/>
<path d="M164.2 88.6h3.3v.7h-3.3z" fill-rule="evenodd" fill="#800000"/>
<path d="M164.2 88.6h3.3v.7h-3.3z" fill="none" stroke="#800000" stroke-width=".2"/>
<path d="M164.2 89.8h3.3v.7h-3.3z" fill-rule="evenodd" fill="#800000"/>
<path d="M164.2 89.8h3.3v.7h-3.3z" fill="none" stroke="#800000" stroke-width=".2"/>
<path d="M164.2 86.3h3.3v.7h-3.3z" fill-rule="evenodd" fill="#800000"/>
<path d="M164.2 86.3h3.3v.7h-3.3z" fill="none" stroke="#800000" stroke-width=".2"/>
<path d="M164.2 85.1h3.3v.7h-3.3z" fill-rule="evenodd" fill="#800000"/>
<path d="M164.2 85.1h3.3v.7h-3.3z" fill="none" stroke="#800000" stroke-width=".2"/>
<path d="M153.9 87.5h3.3v.7h-3.3z" fill-rule="evenodd" fill="#800000"/>
<path d="M153.9 87.5h3.3v.7h-3.3z" fill="none" stroke="#800000" stroke-width=".2"/>
<path d="M153.9 88.6h3.3v.7h-3.3z" fill-rule="evenodd" fill="#800000"/>
<path d="M153.9 88.6h3.3v.7h-3.3z" fill="none" stroke="#800000" stroke-width=".2"/>
<path d="M153.9 89.8h3.3v.7h-3.3z" fill-rule="evenodd" fill="#800000"/>
<path d="M153.9 89.8h3.3v.7h-3.3z" fill="none" stroke="#800000" stroke-width=".2"/>
<path d="M153.9 86.3h3.3v.7h-3.3z" fill-rule="evenodd" fill="#800000"/>
<path d="M153.9 86.3h3.3v.7h-3.3z" fill="none" stroke="#800000" stroke-width=".2"/>
<path d="M153.9 85.1h3.3v.7h-3.3z" fill-rule="evenodd" fill="#800000"/>
<path d="M153.9 85.1h3.3v.7h-3.3z" fill="none" stroke="#800000" stroke-width=".2"/>
<path d="M179.2 80.7h4.7v3.8h-4.7z" fill-rule="evenodd" fill="#800000"/>
<path d="M179.2 80.7h4.7v3.8h-4.7z" fill="none" stroke="#800000" stroke-width=".2"/>
<path d="M179.2 87.2h4.7v3.8h-4.7z" fill-rule="evenodd" fill="#800000"/>
<path d="M179.2 87.2h4.7v3.8h-4.7z" fill="none" stroke="#800000" stroke-width=".2"/>
<path d="M188.7 80.7h4.7v3.8h-4.7z" fill-rule="evenodd" fill="#800000"/>
<path d="M188.7 80.7h4.7v3.8h-4.7z" fill="none" stroke="#800000" stroke-width=".2"/>
<path d="M188.7 87.2h4.7v3.8h-4.7z" fill-rule="evenodd" fill="#800000"/>
<path d="M188.7 87.2h4.7v3.8h-4.7z" fill="none" stroke="#800000" stroke-width=".2"/>
<path d="M188.7 69.2h4.7v3.7h-4.7z" fill-rule="evenodd" fill="#800000"/>
<path d="M188.7 69.2h4.7v3.7h-4.7z" fill="none" stroke="#800000" stroke-width=".2"/>
<path d="M188.7 75.7h4.7v3.7h-4.7z" fill-rule="evenodd" fill="#800000"/>
<path d="M188.7 75.7h4.7v3.7h-4.7z" fill="none" stroke="#800000" stroke-width=".2"/>
<path d="M179.2 69.2h4.7v3.7h-4.7z" fill-rule="evenodd" fill="#800000"/>
<path d="M179.2 69.2h4.7v3.7h-4.7z" fill="none" stroke="#800000" stroke-width=".2"/>
<path d="M179.2 75.7h4.7v3.7h-4.7z" fill-rule="evenodd" fill="#800000"/>
<path d="M179.2 75.7h4.7v3.7h-4.7z" fill="none" stroke="#800000" stroke-width=".2"/>
<path d="M106 140.8h3.8v4.6h-3.8z" fill-rule="evenodd" fill="#800000"/>
<path d="M106 140.8h3.8v4.6h-3.8z" fill="none" stroke="#800000" stroke-width=".2"/>
<path d="M99.5 140.8h3.8v4.6h-3.8z" fill-rule="evenodd" fill="#800000"/>
<path d="M99.5 140.8h3.8v4.6h-3.8z" fill="none" stroke="#800000" stroke-width=".2"/>
<path d="M121.2 140.8h3.8v4.7h-3.8z" fill-rule="evenodd" fill="#800000"/>
<path d="M121.2 140.8h3.8v4.7h-3.8z" fill="none" stroke="#800000" stroke-width=".2"/>
<path d="M114.7 140.8h3.7v4.7h-3.7z" fill-rule="evenodd" fill="#800000"/>
<path d="M114.7 140.8h3.7v4.7h-3.7z" fill="none" stroke="#800000" stroke-width=".2"/>
<path d="M79.6 118.9h4.7v3.7h-4.7z" fill-rule="evenodd" fill="#800000"/>
<path d="M79.6 118.9h4.7v3.7h-4.7z" fill="none" stroke="#800000" stroke-width=".2"/>
<path d="M79.6 125.4h4.7v3.7h-4.7z" fill-rule="evenodd" fill="#800000"/>
<path d="M79.6 125.4h4.7v3.7h-4.7z" fill="none" stroke="#800000" stroke-width=".2"/>
<path d="M71.9 121.4h4.6v3.7h-4.6z" fill-rule="evenodd" fill="#800000"/>
<path d="M71.9 121.4h4.6v3.7h-4.6z" fill="none" stroke="#800000" stroke-width=".2"/>
<path d="M71.9 114.8h4.6v3.7h-4.6z" fill-rule="evenodd" fill="#800000"/>
<path d="M71.9 114.8h4.6v3.7h-4.6z" fill="none" stroke="#800000" stroke-width=".2"/>
<path d="M169.2 66.8h1.2v2.8h-1.2z" fill-rule="evenodd" fill="#800000"/>
<path d="M169.2 66.8h1.2v2.8h-1.2z" fill="none" stroke="#800000" stroke-width=".2"/>
<path d="M166.9 66.8h1.3v2.8h-1.3z" fill-rule="evenodd" fill="#800000"/>
<path d="M166.9 66.8h1.3v2.8h-1.3z" fill="none" stroke="#800000" stroke-width=".2"/>
<path d="M164.7 66.8h1.3v2.8h-1.3z" fill-rule="evenodd" fill="#800000"/>
<path d="M164.7 66.8h1.3v2.8h-1.3z" fill="none" stroke="#800000" stroke-width=".2"/>
<path d="M164.7 72.9h1.3v2.7h-1.3z" fill-rule="evenodd" fill="#800000"/>
<path d="M164.7 72.9h1.3v2.7h-1.3z" fill="none" stroke="#800000" stroke-width=".2"/>
<path d="M169.2 72.9h1.2v2.7h-1.2z" fill-rule="evenodd" fill="#800000"/>
<path d="M169.2 72.9h1.2v2.7h-1.2z" fill="none" stroke="#800000" stroke-width=".2"/>
<path d="M145.7 95.9h3.7v4.6h-3.7z" fill-rule="evenodd" fill="#800000"/>
<path d="M145.7 95.9h3.7v4.6h-3.7z" fill="none" stroke="#800000" stroke-width=".2"/>
<path d="M152.2 95.9h3.8v4.6h-3.8z" fill-rule="evenodd" fill="#800000"/>
<path d="M152.2 95.9h3.8v4.6h-3.8z" fill="none" stroke="#800000" stroke-width=".2"/>
<path d="M195.1 63.2h4.6v3.8h-4.6z" fill-rule="evenodd" fill="#800000"/>
<path d="M195.1 63.2h4.6v3.8h-4.6z" fill="none" stroke="#800000" stroke-width=".2"/>
<path d="M195.1 56.7h4.6v3.8h-4.6z" fill-rule="evenodd" fill="#800000"/>
<path d="M195.1 56.7h4.6v3.8h-4.6z" fill="none" stroke="#800000" stroke-width=".2"/>
<path d="M144.8 165.4h1.5v3.9h-1.5z" fill-rule="evenodd" fill="#800000"/>
<path d="M144.8 165.4h1.5v3.9h-1.5z" fill="none" stroke="#800000" stroke-width=".2"/>
<path d="M141.9 165.4h1.4v3.9h-1.4z" fill-rule="evenodd" fill="#800000"/>
<path d="M141.9 165.4h1.4v3.9h-1.4z" fill="none" stroke="#800000" stroke-width=".2"/>
<path d="M147.8 165.4h1.4v3.9h-1.4z" fill-rule="evenodd" fill="#800000"/>
<path d="M147.8 165.4h1.4v3.9h-1.4z" fill="none" stroke="#800000" stroke-width=".2"/>
<path d="M150.8 165.4h1.4v3.9h-1.4z" fill-rule="evenodd" fill="#800000"/>
<path d="M150.8 165.4h1.4v3.9h-1.4z" fill="none" stroke="#800000" stroke-width=".2"/>
<path d="M142.5 154.6h9.1v8.9h-9.1z" fill-rule="evenodd" fill="#800000"/>
<path d="M142.5 154.6h9.1v8.9h-9.1z" fill="none" stroke="#800000" stroke-width=".2"/>
<path d="M141.9 152.1h1.4v3.3h-1.4z" fill-rule="evenodd" fill="#800000"/>
<path d="M141.9 152.1h1.4v3.3h-1.4z" fill="none" stroke="#800000" stroke-width=".2"/>
<path d="M144.8 152.1h1.5v3.3h-1.5z" fill-rule="evenodd" fill="#800000"/>
<path d="M144.8 152.1h1.5v3.3h-1.5z" fill="none" stroke="#800000" stroke-width=".2"/>
<path d="M147.8 152.1h1.4v3.3h-1.4z" fill-rule="evenodd" fill="#800000"/>
<path d="M147.8 152.1h1.4v3.3h-1.4z" fill="none" stroke="#800000" stroke-width=".2"/>
<path d="M150.8 152.1h1.4v3.3h-1.4z" fill-rule="evenodd" fill="#800000"/>
<path d="M150.8 152.1h1.4v3.3h-1.4z" fill="none" stroke="#800000" stroke-width=".2"/>
<path d="M141 161.8h1.6v1h-1.6z" fill-rule="evenodd" fill="#800000"/>
<path d="M141 161.8h1.6v1h-1.6z" fill="none" stroke="#800000" stroke-width=".2"/>
<path d="M151.4 161.8h1.6v1h-1.6z" fill-rule="evenodd" fill="#800000"/>
<path d="M151.4 161.8h1.6v1h-1.6z" fill="none" stroke="#800000" stroke-width=".2"/>
<path d="M159.8 160.3h4.7v3.7h-4.7z" fill-rule="evenodd" fill="#800000"/>
<path d="M159.8 160.3h4.7v3.7h-4.7z" fill="none" stroke="#800000" stroke-width=".2"/>
<path d="M159.8 166.9h4.7v3.7h-4.7z" fill-rule="evenodd" fill="#800000"/>
<path d="M159.8 166.9h4.7v3.7h-4.7z" fill="none" stroke="#800000" stroke-width=".2"/>
<path d="M24 231.9h140.3v9.4h-140.3z" fill-rule="evenodd" fill="#800000"/>
<path d="M24 231.9h140.3v9.4h-140.3z" fill="none" stroke="#800000" stroke-width=".2"/>
<path d="M118.5 115.8h2.8v1.3h-2.8z" fill-rule="evenodd" fill="#800000"/>
<path d="M118.5 115.8h2.8v1.3h-2.8z" fill="none" stroke="#800000" stroke-width=".2"/>
<path d="M118.5 113.6h2.8v1.3h-2.8z" fill-rule="evenodd" fill="#800000"/>
<path d="M118.5 113.6h2.8v1.3h-2.8z" fill="none" stroke="#800000" stroke-width=".2"/>
<path d="M118.5 111.3h2.8v1.3h-2.8z" fill-rule="evenodd" fill="#800000"/>
<path d="M118.5 111.3h2.8v1.3h-2.8z" fill="none" stroke="#800000" stroke-width=".2"/>
<path d="M112.4 111.3h2.8v1.3h-2.8z" fill-rule="evenodd" fill="#800000"/>
<path d="M112.4 111.3h2.8v1.3h-2.8z" fill="none" stroke="#800000" stroke-width=".2"/>
<path d="M112.4 115.8h2.8v1.3h-2.8z" fill-rule="evenodd" fill="#800000"/>
<path d="M112.4 115.8h2.8v1.3h-2.8z" fill="none" stroke="#800000" stroke-width=".2"/>
<path d="M155.9 66.9h3.5v3h-3.5z" fill-rule="evenodd" fill="#800000"/>
<path d="M155.9 66.9h3.5v3h-3.5z" fill="none" stroke="#800000" stroke-width=".2"/>
<path d="M155.9 71.3h3.5v3.1h-3.5z" fill-rule="evenodd" fill="#800000"/>
<path d="M155.9 71.3h3.5v3.1h-3.5z" fill="none" stroke="#800000" stroke-width=".2"/>
<path d="M160 77h3v3.5h-3z" fill-rule="evenodd" fill="#800000"/>
<path d="M160 77h3v3.5h-3z" fill="none" stroke="#800000" stroke-width=".2"/>
<path d="M155.5 77h3.1v3.5h-3.1z" fill-rule="evenodd" fill="#800000"/>
<path d="M155.5 77h3.1v3.5h-3.1z" fill="none" stroke="#800000" stroke-width=".2"/>
<path d="M105.2 72h3.5v3.1h-3.5z" fill-rule="evenodd" fill="#800000"/>
<path d="M105.2 72h3.5v3.1h-3.5z" fill="none" stroke="#800000" stroke-width=".2"/>
<path d="M105.2 67.6h3.5v3h-3.5z" fill-rule="evenodd" fill="#800000"/>
<path d="M105.2 67.6h3.5v3h-3.5z" fill="none" stroke="#800000" stroke-width=".2"/>
<path d="M109.8 72h3.5v3.1h-3.5z" fill-rule="evenodd" fill="#800000"/>
<path d="M109.8 72h3.5v3.1h-3.5z" fill="none" stroke="#800000" stroke-width=".2"/>
<path d="M109.8 67.6h3.5v3h-3.5z" fill-rule="evenodd" fill="#800000"/>
<path d="M109.8 67.6h3.5v3h-3.5z" fill="none" stroke="#800000" stroke-width=".2"/>
<path d="M83.3 64.9h3.5v3h-3.5z" fill-rule="evenodd" fill="#800000"/>
<path d="M83.3 64.9h3.5v3h-3.5z" fill="none" stroke="#800000" stroke-width=".2"/>
<path d="M83.3 69.3h3.5v3h-3.5z" fill-rule="evenodd" fill="#800000"/>
<path d="M83.3 69.3h3.5v3h-3.5z" fill="none" stroke="#800000" stroke-width=".2"/>
<path d="M104.6 110.3h3.5v3.1h-3.5z" fill-rule="evenodd" fill="#800000"/>
<path d="M104.6 110.3h3.5v3.1h-3.5z" fill="none" stroke="#800000" stroke-width=".2"/>
<path d="M104.6 114.8h3.5v3h-3.5z" fill-rule="evenodd" fill="#800000"/>
<path d="M104.6 114.8h3.5v3h-3.5z" fill="none" stroke="#800000" stroke-width=".2"/>
<path d="M97.2 110.3h3.5v3.1h-3.5z" fill-rule="evenodd" fill="#800000"/>
<path d="M97.2 110.3h3.5v3.1h-3.5z" fill="none" stroke="#800000" stroke-width=".2"/>
<path d="M97.2 114.8h3.5v3h-3.5z" fill-rule="evenodd" fill="#800000"/>
<path d="M97.2 114.8h3.5v3h-3.5z" fill="none" stroke="#800000" stroke-width=".2"/>
<path d="M106.3 169h1.3v2.7h-1.3z" fill-rule="evenodd" fill="#800000"/>
<path d="M106.3 169h1.3v2.7h-1.3z" fill="none" stroke="#800000" stroke-width=".2"/>
<path d="M104.1 169h1.2v2.7h-1.2z" fill-rule="evenodd" fill="#800000"/>
<path d="M104.1 169h1.2v2.7h-1.2z" fill="none" stroke="#800000" stroke-width=".2"/>
<path d="M101.9 169h1.2v2.7h-1.2z" fill-rule="evenodd" fill="#800000"/>
<path d="M101.9 169h1.2v2.7h-1.2z" fill="none" stroke="#800000" stroke-width=".2"/>
<path d="M101.9 175h1.2v2.8h-1.2z" fill-rule="evenodd" fill="#800000"/>
<path d="M101.9 175h1.2v2.8h-1.2z" fill="none" stroke="#800000" stroke-width=".2"/>
<path d="M106.3 175h1.3v2.8h-1.3z" fill-rule="evenodd" fill="#800000"/>
<path d="M106.3 175h1.3v2.8h-1.3z" fill="none" stroke="#800000" stroke-width=".2"/>
<path d="M72.3 170.3h1.3v2.8h-1.3z" fill-rule="evenodd" fill="#800000"/>
<path d="M72.3 170.3h1.3v2.8h-1.3z" fill="none" stroke="#800000" stroke-width=".2"/>
<path d="M70.1 170.3h1.3v2.8h-1.3z" fill-rule="evenodd" fill="#800000"/>
<path d="M70.1 170.3h1.3v2.8h-1.3z" fill="none" stroke="#800000" stroke-width=".2"/>
<path d="M67.9 170.3h1.3v2.8h-1.3z" fill-rule="evenodd" fill="#800000"/>
<path d="M67.9 170.3h1.3v2.8h-1.3z" fill="none" stroke="#800000" stroke-width=".2"/>
<path d="M67.9 176.4h1.3v2.8h-1.3z" fill-rule="evenodd" fill="#800000"/>
<path d="M67.9 176.4h1.3v2.8h-1.3z" fill="none" stroke="#800000" stroke-width=".2"/>
<path d="M72.3 176.4h1.3v2.8h-1.3z" fill-rule="evenodd" fill="#800000"/>
<path d="M72.3 176.4h1.3v2.8h-1.3z" fill="none" stroke="#800000" stroke-width=".2"/>
<g fill="none" stroke="#800000" stroke-width=".97">
<path d="M87.7 37.9l-3 3h-10l-1.9 1.9v26.5l11.7 11.7v9.4l2.7 2.7h5.8M19.1 58h6M22.1 55.8v2.2M25.1 52.7v.1M31.1 46.8h6l3 2.9M32.2 52.7h.1M40.1 49.8l-2.9 2.9h-5M43.1 59.1l-1.1 1M43.1 59.1h.1M46.1 49.7l3 3v4.5l-1.9 1.9h-4.1M46.1 49.8l-3 2.9v6.4M52 49.7l3.1 3.1v20.5"/>
<path d="M63.9 49.7l-2.9 3v20.6M75.8 49.7l3 3v7.4l12.6 12.7v1M87.7 43.8l3 3.1h35.6l2.9-3.1M87.7 49.7l-3.1 3h-5.9M99.5 49.7h-2.9v7.8l-2.9 3-2.9-2.9v-5.1l2.7-2.7h.2M105.5 49.7v.2l-2.9 2.9v4l3 3 2.9-2.8v-7.2M135.2 49.7l-3.3 3.3v10.2l-5.4 5.4M141.1 49.7l-3-3v-12h-105.9l-3.5 3.5v2.8l-4.7 4.6h-8.3l-7.1 7v5.4h7.5M197.4 51.1v7.5M8.6 64.6h.2v6.4l6.7 6.6M15.4 62.9h1.9l3.3 3.4M16.1 71.6h9"/>
<path d="M20.6 66.3l1.5 1.4v3.9M25.8 62.9h-2l-3.2 3.4M58 62.7v10.6M76.5 61v8.6l11.3 11.3v6.8l2.4 2.4h2.8M84.7 60.7l2.6 2.6h2.2l4.9 4.8v8.4l5.8 5.8v7.8l2.9 3h4.8l3.7 3.7h-.5M85 70.8v.7l3.2 3.1M100.5 60.5v5.9l-3 3M106.9 69.1h.1M111.5 69.1h-7.2l-2.1 2.1h-4.2l-.5 .4M120.5 73.8l-.3-.3h-13.3l-.3 .3h-9.1M135.2 61v.4M176.5 68.6l2.4 2.4h2.7"/>
<path d="M197.4 65.1v4.3M23.4 97.3h6M27.9 89l-3.3 3.2h-1.9M27.9 89l3.3 3.2h1.9M32.4 83.7h-9l4.5 4.4v.9M32.4 97.3l15.4 15.4v42l1.8 1.7M39.7 97.3h6M44.2 89l3.3 3.2h1.9M45.7 83.7v3.8l-4.8 4.7h-1.9M48.6 97.3l2.9 2.8v50.8M55.1 82.2l-.1 78.5 11.1 11h2.4M58 82.2v67.3l3.7 3.7h14.3l4.4 4.4"/>
<path d="M61 82.2v65.4l2.8 2.8h22l4.1 4.1v5.9l10 9.9h2.6M64 89.3v55.5l3 3h20.8l8.7 8.7v3.9M93 81.6v5.5M102.4 80.9v6.6l2.6 2.6h8.8l2.2 2.3 .1 4.4M116 94.1h.1M116.7 87l6.4 6.5v2.5M116.7 82.6h.1M116.7 87v.1M116.7 82.6h-3.4l-1.6 1.6h-4.3M116.7 87l-9.3 .1M123.2 82.6h-6.5M135.2 92.9v3.1h-.2v10l.2 .1"/>
<path d="M146 96.6l-.9 .9h-3.3M147.5 92v6.2M152.7 96.8l1.4 1.4M192.7 99h.1M207.6 99h.1M74.2 116.7h3.7l4.1 4 1.2-1.2M81.1 119.9l1.3 1.3h20.3M98.9 116.3h7.4l.3 .3h2.9M98.9 111.8h10.1l2.3-2.2h7l1.6 1.7v.7h2.1l.8 .7v2.8l-1 .9h-1.9M109.5 116.6v18.3M113.8 116.4h1.8l1.9 1.9h8.8l1.4 1.4v6l-1.1 1.1h-6.6M119.9 114.2h-8l-2.4 2.4"/>
<path d="M135.1 119.4l.4 .5M175.6 100.7l.1 5.3M175.6 114.2v10.6l2.7 2.7v6.4M179 110.4v14.4l1.3 1.4h9.5l2.6 2.5M187.7 108.1h8.9M190.7 108.1v1.5l-.8 .8v.8l2.3 2.3M190.7 108.1h.1M192.2 113.5l-3.3 3.2h-2M192.2 113.5l3.2 3.2h2M207.6 111.4l.3 .4v23M74.2 123.2v3.2l-1.6 1.7M82 127.3v.4l15.3 15.4h4.1v-8.2h14.3"/>
<path d="M91.1 125.7h11.6M93.3 123.8l.5 .4h8.9M98.7 131.7v.1h4M102.7 130.3h-1.7l-1.2-1.2h-6.8l-1.6 1.5M102.7 122.7h2.5l.8 .8v1.6M102.7 127.3v1.5h6.8M102.7 133.4l-2.2-.1-2.2 2.3h-1.1l-1.1-1.2M109.5 131.9h6.2M109.5 130.3h6.2M109.5 124.2h6.2M109.5 121.2h6.2M112.2 138.8l4.4 4.3"/>
<path d="M115.7 125.7l-6.2 .1M120 126.8l-.5 .5h-3.8v1.5M120 126.8v5.2l-1.4 1.4h-2.9M124.6 122.4h-4.6l-.3 .3h-10.2M175.3 129.2h-16.1l-.6 .6M184.8 133.9v6.3h4.6M187.6 129.2l2.3 2.3h5.5M192.4 131.5v3.4M193.6 121.7h-5.9l-.5 .5M193.9 134.9v7.3l2 1.9 7.6-.1M193.9 125.6v3.2M195.4 134.9v3.1l2.2 2.2"/>
<path d="M195.5 128.8l-.1 2.7M196.6 121.7l.3 .3v6.7M199.9 120.6h3.6M203.5 131.4l-8.1 .1M207.9 134.8v10.4M207.9 134.8l-11 .1M51.5 147.5h.1M58 147.7h.1M66.4 157.1l6.6 6.6v8M106 152.7l2.9 2.9v12.8l-2 1.9M113.7 140.3l-2.9 2.8h-2.9M130.4 142.7h-7.3v.4"/>
<path d="M142.6 153.7h8.9M145.5 153.7v3.9l1.5 1.4M147 159l-3.2 3.3h-2M147 159l3.3 3.3h1.9M151.5 146.8v.1M158.6 146.8h.1M184.8 146.8l8.3 8.2h14.9v-3.4M195.9 150.7l7.6 .9M207.9 144h.1M207.9 144l.1 7.6M58.8 179l.8-.9h4.2l2 2.1M58.8 168.8v3.6"/>
<path d="M61.6 160.7l6.4 6.5M68.5 177.8l-2.3 2.4h-.4M70.7 171.7v11.4l1.6 1.6h.3M79.2 178.1h.1M79.3 178.1l-6.7 6.6M84.3 171.8v4.8l-1.5 1.5h-3.6M89.6 171.9v-3.8h-8.7l-1.6 1.6v4h-2.1l-4.2 4.1M96.5 160.4h4.7v5.3M96.5 160.4h.1M99 178.3v.2h-9.4M102.5 176.4h-1.9l-1.6 1.6v6.2M104.7 170.3v13l.9 .9"/>
<path d="M112.5 178l-6.2 6.2h-.7M112.6 168.4v5.1h-4.7l-1 1v1.9M135.2 162.5l.9 .9-.9 .9v19M142.6 167.3h5.9v3.1l.6 .6h10.7l2.3-2.3M162.1 162.2h-2.2l-5.2 5.1h-3.2M175.4 173.4v7.4M47.1 196.2h15.8l7.2 7.2M47.1 196.2h.1M54.8 199.9l2.8 2.8h3.4M65.8 180.2v4.5M85.9 195.9h15.4l2.4 2.4M103.7 198.3l4.8 4.8"/>
<path d="M103.7 198.3h4M105.6 184.2v1.8l-2.9 2.8h-26l-4.1-4.1M121.9 196.6v16.3l2.7 2.8M131.6 198.7v1.9l3.3 3.3M175.4 188.7v8.4l2.7 2.7v8.4M179.1 183.9v11.5l2.7 2.8h6.4l4 3.9M186.1 189.9h10.5M186.9 181.3h8.9M189.9 181.3l1.6 2.1-.2 6.5M191.3 186.6v3.3M192.8 181.3v1l-1.3 1.4M193.7 199v3.1"/>
<path d="M195.8 194.9l.9 .5v6.7M199.8 192.9l3.8 .1M203.5 192.9l.1 .1M207.7 184.4v8.2l.3 .3-.1 39.3h-14.1l-9.4-9.4M47.1 202.7v9.2M47.1 202.7l.1 .1M47.1 202.7l.2 1h6.5l3.8 3.7M57.6 215.2h.1M57.6 216.4v1l3.3 3.3M57.6 212.9h.1M57.6 215.2h-7.3l-3.2 3.2M63.7 216.4v1.5l-2.8 2.8"/>
<path d="M65.5 219.2h5.7M66.3 214.1l1.6 1.5M67.6 200.9l-1 2M67.9 208.1h-10.3M70.1 203.4v6.7l-1.6 1.6M70.1 203.4h3.7M73.8 209.9v3M85.9 202.4h.1M85.9 202.4h5.4l4.9 5.1-.1-.2h10.2M85.9 202.4v9.7M90.8 215.7v.1M95.2 202.4h4.8"/>
<path d="M96.1 218l3.1 3M96.1 215.8h-7.3l-2.9 2.8M102.2 218.3l-2.6 2.6v1.1M104 219.8h6.3M108.5 203.1v7.2l-2 2M108.5 203.1h4M112.5 209.6v3.8M124.6 215.7h.1M124.6 215.7l4 3.9M126.6 202.4v3M126.6 208.4l2 2v2.7h4.2M134.9 203.9l-3.3 3.3v1.9"/>
<path d="M134.9 203.9l1.5 1.5h3.8M158.7 203.3h16.9M184.7 208.2v7.2h-1.1l2.2-2.3h3.1M187 203.3l1.8 1.8h14.7M192.2 208.2v6.9l-7.8 7.7M193.7 208.2v9.7l2.1 2.1 7.7-2.3M195.2 202.1v3M195.2 208.2v2.2l2.7 2.7M208 205.1h.1M208 208.2h-11.3M60.9 220.7l-.2 .2M99.2 221v.7"/>
<path d="M99.2 221h.4M183.6 222l.8 .8M195.8 226.5l7.7 1.6M207.9 228.1h.1"/>
</g>
<g fill="none" stroke="#800000" stroke-width="3">
<path d="M43.1 59.1l-13.1 13.1M81.7 43.8h6M93.6 49.7h5.9M105.5 49.7h5.9M105.6 59.8h8.3l2.2 2.3v7.7l4 4h8.9M19.2 85.4l3.5 3.6h21.5M23.4 97.3v2.4l3 3M45.7 97.3v4.2l-1.8 1.7M192.7 99l-5.6-4.3h-7l-4.5 6M207.6 99v12.4M158.6 110.4h31.3M185.9 100.7v5.6l1.8 1.8"/>
<path d="M158.6 129.8v17M170.6 137.6v6.2l2.9 3M141.2 146.9v5.5l1.4 1.3M151.5 146.8h7.2M192.8 170.7l-4.5-4.5h-5.8l-7.1 7.2M207.7 170.7v13.7M140.2 199.4l.1 22M158.7 183.9h32.8M158.7 203.3v18.1l-8.2-.1M170.7 212.5v6l2.9 2.9"/>
</g>
<path d="M117.3 55.7l2.8 2.8v10.1M130.4 109.8v71.6l-13.2 13.2v24.6l-4.6 4.5h-11.3M126.6 191.9v10.5M60.7 220.9l-1.8 1.8h-4" fill="none" stroke="#800000" stroke-width="2.4"/>
<g fill="none" stroke="#800000" stroke-width=".72">
<path d="M165.3 68.2v-1.7l.9-.9h2.8l.8 .8v1.8M165.4 68.2h-7.5l-.3 .2h-8.9l-7.9 7.9v13.1l-3.5 3.5h-2.1M167.6 68.2v1.9l1.1 1.2M169.8 74.3v1.8l2.6 2.6-.1 .1h-10.8M178.9 71l-1.3 1.3v5.8l-7.3 7.4h-14.8M181.6 77.6v5h-5.6l-4.1 4.1h-6.1M191.1 71h-9.5l-.3 .3h-22.1l-1.6 1.6v5.3l-.5 .6M191.1 77.6v5h-3l-3.3 3.3h-8.4l-2 1.9h-8.6M39.7 83.7h8.9M146 96.6l1.5 1.6M155.5 90.2h-1.4l-1.4 1.5v5.1M155.5 89h-5l-3 3"/>
<path d="M155.5 86.7h2.9l.9 .9v5.2l2.9 3h9.5M165.8 90.2h1.7l2.3 2.2h4.1l.9-.8M165.8 89l25.3 .1M166.9 82.7h-13.3l-1.1 1.1v3.2l.8 .8h2.2M178.9 158.9h-13.5l-3.3 3.3M186.5 194.5l.4 .4h5.9M54.8 212.9h2.8M57.6 207.4v4.3M57.6 214.1v1.1M63.7 216.4h.1M63.7 211.7h4.8M63.7 215.2h1.8v4"/>
<path d="M63.7 212.9h10.1M63.7 214.1h2.6M91.9 213.4h4.2M96.1 207.4v4.9M96.1 214.6v1.2M96.1 216.9v1.1M102.2 213.4h10.3M102.2 214.6h2.5l1.6 1.6M102.2 212.3h4.3M102.2 215.8h1.8v4M102.2 216.9v1.4"/>
</g>
<path d="M31.1 46.8l-6 5.9h7.1M66.6 63l-2.6 2.6v7.7M64 82.2v1.7l3.4 3.3v52.7l3.1 3.1h18.9l5.6 5.6h19.7l11.9 11.9v10.6M144.2 173.3l31.2 .1M175.4 173.4h.1M73.8 198.2v5.2M126.6 199.4v.1M99.6 220.9v1.2l1.7 1.6" fill="none" stroke="#800000" stroke-width="1.9"/>
<path d="M154.1 98.2l2.5 2.5h19M182.5 122.2h4.7M185.7 173.4v6.7l1.2 1.2M182 194.5h4.5M47.1 218.4v3l6 5.9h24.1l8.7-8.7" fill="none" stroke="#800000" stroke-width="3.3"/>
<path d="M129.7 96h5.3M129.8 82.6h5.5M96.1 216.9l.1 .1" fill="none" stroke="#800000" stroke-width=".63"/>
<path d="M182.7 37.9l6.9 6.8v12l-4.8 4.7h-49.6M25.1 52.7l-3 3.1M34.2 55.7v5.6l-4.9 5h-8.7M135.2 55.7v30.7M15.5 77.6h56.2l5.8 5.8v15.1l6.5 6.5h51M146 76.7v19.9M135.2 92.9l-.1 26.5M135.2 119.6v63.7l-13.3 13.3M136.1 163.4l4 3.9h2.5" fill="none" stroke="#800000" stroke-width="3.9"/>
<circle cx="34.2" cy="43.8" r="1.78" fill="#008000"/>
<circle cx="34.2" cy="43.8" r="1.78" fill="none" stroke="#008000" stroke-width=".2"/>
<circle cx="34.2" cy="43.8" r="1.18" fill="#fff"/>
<circle cx="34.2" cy="43.8" r="1.18" fill="none" stroke="#000" stroke-width=".2"/>
<circle cx="34.2" cy="37.9" r="1.78" fill="#008000"/>
<circle cx="34.2" cy="37.9" r="1.78" fill="none" stroke="#008000" stroke-width=".2"/>
<circle cx="34.2" cy="37.9" r="1.18" fill="#fff"/>
<circle cx="34.2" cy="37.9" r="1.18" fill="none" stroke="#000" stroke-width=".2"/>
<circle cx="40.1" cy="43.8" r="1.78" fill="#008000"/>
<circle cx="40.1" cy="43.8" r="1.78" fill="none" stroke="#008000" stroke-width=".2"/>
<circle cx="40.1" cy="43.8" r="1.18" fill="#fff"/>
<circle cx="40.1" cy="43.8" r="1.18" fill="none" stroke="#000" stroke-width=".2"/>
<circle cx="40.1" cy="37.9" r="1.78" fill="#008000"/>
<circle cx="40.1" cy="37.9" r="1.78" fill="none" stroke="#008000" stroke-width=".2"/>
<circle cx="40.1" cy="37.9" r="1.18" fill="#fff"/>
<circle cx="40.1" cy="37.9" r="1.18" fill="none" stroke="#000" stroke-width=".2"/>
<circle cx="46.1" cy="43.8" r="1.78" fill="#008000"/>
<circle cx="46.1" cy="43.8" r="1.78" fill="none" stroke="#008000" stroke-width=".2"/>
<circle cx="46.1" cy="43.8" r="1.18" fill="#fff"/>
<circle cx="46.1" cy="43.8" r="1.18" fill="none" stroke="#000" stroke-width=".2"/>
<circle cx="46.1" cy="37.9" r="1.78" fill="#008000"/>
<circle cx="46.1" cy="37.9" r="1.78" fill="none" stroke="#008000" stroke-width=".2"/>
<circle cx="46.1" cy="37.9" r="1.18" fill="#fff"/>
<circle cx="46.1" cy="37.9" r="1.18" fill="none" stroke="#000" stroke-width=".2"/>
<circle cx="52" cy="43.8" r="1.78" fill="#008000"/>
<circle cx="52" cy="43.8" r="1.78" fill="none" stroke="#008000" stroke-width=".2"/>
<circle cx="52" cy="43.8" r="1.18" fill="#fff"/>
<circle cx="52" cy="43.8" r="1.18" fill="none" stroke="#000" stroke-width=".2"/>
<circle cx="52" cy="37.9" r="1.78" fill="#008000"/>
<circle cx="52" cy="37.9" r="1.78" fill="none" stroke="#008000" stroke-width=".2"/>
<circle cx="52" cy="37.9" r="1.18" fill="#fff"/>
<circle cx="52" cy="37.9" r="1.18" fill="none" stroke="#000" stroke-width=".2"/>
<circle cx="58" cy="43.8" r="1.78" fill="#008000"/>
<circle cx="58" cy="43.8" r="1.78" fill="none" stroke="#008000" stroke-width=".2"/>
<circle cx="58" cy="43.8" r="1.18" fill="#fff"/>
<circle cx="58" cy="43.8" r="1.18" fill="none" stroke="#000" stroke-width=".2"/>
<circle cx="58" cy="37.9" r="1.78" fill="#008000"/>
<circle cx="58" cy="37.9" r="1.78" fill="none" stroke="#008000" stroke-width=".2"/>
<circle cx="58" cy="37.9" r="1.18" fill="#fff"/>
<circle cx="58" cy="37.9" r="1.18" fill="none" stroke="#000" stroke-width=".2"/>
<circle cx="63.9" cy="43.8" r="1.78" fill="#008000"/>
<circle cx="63.9" cy="43.8" r="1.78" fill="none" stroke="#008000" stroke-width=".2"/>
<circle cx="63.9" cy="43.8" r="1.18" fill="#fff"/>
<circle cx="63.9" cy="43.8" r="1.18" fill="none" stroke="#000" stroke-width=".2"/>
<circle cx="63.9" cy="37.9" r="1.78" fill="#008000"/>
<circle cx="63.9" cy="37.9" r="1.78" fill="none" stroke="#008000" stroke-width=".2"/>
<circle cx="63.9" cy="37.9" r="1.18" fill="#fff"/>
<circle cx="63.9" cy="37.9" r="1.18" fill="none" stroke="#000" stroke-width=".2"/>
<circle cx="69.9" cy="43.8" r="1.78" fill="#008000"/>
<circle cx="69.9" cy="43.8" r="1.78" fill="none" stroke="#008000" stroke-width=".2"/>
<circle cx="69.9" cy="43.8" r="1.18" fill="#fff"/>
<circle cx="69.9" cy="43.8" r="1.18" fill="none" stroke="#000" stroke-width=".2"/>
<circle cx="69.9" cy="37.9" r="1.78" fill="#008000"/>
<circle cx="69.9" cy="37.9" r="1.78" fill="none" stroke="#008000" stroke-width=".2"/>
<circle cx="69.9" cy="37.9" r="1.18" fill="#fff"/>
<circle cx="69.9" cy="37.9" r="1.18" fill="none" stroke="#000" stroke-width=".2"/>
<circle cx="75.8" cy="43.8" r="1.78" fill="#008000"/>
<circle cx="75.8" cy="43.8" r="1.78" fill="none" stroke="#008000" stroke-width=".2"/>
<circle cx="75.8" cy="43.8" r="1.18" fill="#fff"/>
<circle cx="75.8" cy="43.8" r="1.18" fill="none" stroke="#000" stroke-width=".2"/>
<circle cx="75.8" cy="37.9" r="1.78" fill="#008000"/>
<circle cx="75.8" cy="37.9" r="1.78" fill="none" stroke="#008000" stroke-width=".2"/>
<circle cx="75.8" cy="37.9" r="1.18" fill="#fff"/>
<circle cx="75.8" cy="37.9" r="1.18" fill="none" stroke="#000" stroke-width=".2"/>
<circle cx="81.7" cy="43.8" r="1.78" fill="#008000"/>
<circle cx="81.7" cy="43.8" r="1.78" fill="none" stroke="#008000" stroke-width=".2"/>
<circle cx="81.8" cy="43.8" r="1.18" fill="#fff"/>
<circle cx="81.8" cy="43.8" r="1.18" fill="none" stroke="#000" stroke-width=".2"/>
<circle cx="81.7" cy="37.9" r="1.78" fill="#008000"/>
<circle cx="81.7" cy="37.9" r="1.78" fill="none" stroke="#008000" stroke-width=".2"/>
<circle cx="81.8" cy="37.9" r="1.18" fill="#fff"/>
<circle cx="81.8" cy="37.9" r="1.18" fill="none" stroke="#000" stroke-width=".2"/>
<circle cx="87.7" cy="43.8" r="1.78" fill="#008000"/>
<circle cx="87.7" cy="43.8" r="1.78" fill="none" stroke="#008000" stroke-width=".2"/>
<circle cx="87.7" cy="43.8" r="1.18" fill="#fff"/>
<circle cx="87.7" cy="43.8" r="1.18" fill="none" stroke="#000" stroke-width=".2"/>
<circle cx="87.7" cy="37.9" r="1.78" fill="#008000"/>
<circle cx="87.7" cy="37.9" r="1.78" fill="none" stroke="#008000" stroke-width=".2"/>
<circle cx="87.7" cy="37.9" r="1.18" fill="#fff"/>
<circle cx="87.7" cy="37.9" r="1.18" fill="none" stroke="#000" stroke-width=".2"/>
<circle cx="93.6" cy="43.8" r="1.78" fill="#008000"/>
<circle cx="93.6" cy="43.8" r="1.78" fill="none" stroke="#008000" stroke-width=".2"/>
<circle cx="93.6" cy="43.8" r="1.18" fill="#fff"/>
<circle cx="93.6" cy="43.8" r="1.18" fill="none" stroke="#000" stroke-width=".2"/>
<circle cx="93.6" cy="37.9" r="1.78" fill="#008000"/>
<circle cx="93.6" cy="37.9" r="1.78" fill="none" stroke="#008000" stroke-width=".2"/>
<circle cx="93.6" cy="37.9" r="1.18" fill="#fff"/>
<circle cx="93.6" cy="37.9" r="1.18" fill="none" stroke="#000" stroke-width=".2"/>
<circle cx="99.6" cy="43.8" r="1.78" fill="#008000"/>
<circle cx="99.6" cy="43.8" r="1.78" fill="none" stroke="#008000" stroke-width=".2"/>
<circle cx="99.6" cy="43.8" r="1.18" fill="#fff"/>
<circle cx="99.6" cy="43.8" r="1.18" fill="none" stroke="#000" stroke-width=".2"/>
<circle cx="99.6" cy="37.9" r="1.78" fill="#008000"/>
<circle cx="99.6" cy="37.9" r="1.78" fill="none" stroke="#008000" stroke-width=".2"/>
<circle cx="99.6" cy="37.9" r="1.18" fill="#fff"/>
<circle cx="99.6" cy="37.9" r="1.18" fill="none" stroke="#000" stroke-width=".2"/>
<circle cx="105.5" cy="43.8" r="1.78" fill="#008000"/>
<circle cx="105.5" cy="43.8" r="1.78" fill="none" stroke="#008000" stroke-width=".2"/>
<circle cx="105.5" cy="43.8" r="1.18" fill="#fff"/>
<circle cx="105.5" cy="43.8" r="1.18" fill="none" stroke="#000" stroke-width=".2"/>
<circle cx="105.5" cy="37.9" r="1.78" fill="#008000"/>
<circle cx="105.5" cy="37.9" r="1.78" fill="none" stroke="#008000" stroke-width=".2"/>
<circle cx="105.5" cy="37.9" r="1.18" fill="#fff"/>
<circle cx="105.5" cy="37.9" r="1.18" fill="none" stroke="#000" stroke-width=".2"/>
<circle cx="111.4" cy="43.8" r="1.78" fill="#008000"/>
<circle cx="111.4" cy="43.8" r="1.78" fill="none" stroke="#008000" stroke-width=".2"/>
<circle cx="111.4" cy="43.8" r="1.18" fill="#fff"/>
<circle cx="111.4" cy="43.8" r="1.18" fill="none" stroke="#000" stroke-width=".2"/>
<circle cx="111.4" cy="37.9" r="1.78" fill="#008000"/>
<circle cx="111.4" cy="37.9" r="1.78" fill="none" stroke="#008000" stroke-width=".2"/>
<circle cx="111.4" cy="37.9" r="1.18" fill="#fff"/>
<circle cx="111.4" cy="37.9" r="1.18" fill="none" stroke="#000" stroke-width=".2"/>
<circle cx="117.4" cy="43.8" r="1.78" fill="#008000"/>
<circle cx="117.4" cy="43.8" r="1.78" fill="none" stroke="#008000" stroke-width=".2"/>
<circle cx="117.4" cy="43.8" r="1.18" fill="#fff"/>
<circle cx="117.4" cy="43.8" r="1.18" fill="none" stroke="#000" stroke-width=".2"/>
<circle cx="117.4" cy="37.9" r="1.78" fill="#008000"/>
<circle cx="117.4" cy="37.9" r="1.78" fill="none" stroke="#008000" stroke-width=".2"/>
<circle cx="117.4" cy="37.9" r="1.18" fill="#fff"/>
<circle cx="117.4" cy="37.9" r="1.18" fill="none" stroke="#000" stroke-width=".2"/>
<circle cx="123.3" cy="43.8" r="1.78" fill="#008000"/>
<circle cx="123.3" cy="43.8" r="1.78" fill="none" stroke="#008000" stroke-width=".2"/>
<circle cx="123.3" cy="43.8" r="1.18" fill="#fff"/>
<circle cx="123.3" cy="43.8" r="1.18" fill="none" stroke="#000" stroke-width=".2"/>
<circle cx="123.3" cy="37.9" r="1.78" fill="#008000"/>
<circle cx="123.3" cy="37.9" r="1.78" fill="none" stroke="#008000" stroke-width=".2"/>
<circle cx="123.3" cy="37.9" r="1.18" fill="#fff"/>
<circle cx="123.3" cy="37.9" r="1.18" fill="none" stroke="#000" stroke-width=".2"/>
<circle cx="129.2" cy="43.8" r="1.78" fill="#008000"/>
<circle cx="129.2" cy="43.8" r="1.78" fill="none" stroke="#008000" stroke-width=".2"/>
<circle cx="129.2" cy="43.8" r="1.18" fill="#fff"/>
<circle cx="129.2" cy="43.8" r="1.18" fill="none" stroke="#000" stroke-width=".2"/>
<circle cx="129.2" cy="37.9" r="1.78" fill="#008000"/>
<circle cx="129.2" cy="37.9" r="1.78" fill="none" stroke="#008000" stroke-width=".2"/>
<circle cx="129.2" cy="37.9" r="1.18" fill="#fff"/>
<circle cx="129.2" cy="37.9" r="1.18" fill="none" stroke="#000" stroke-width=".2"/>
<circle cx="135.2" cy="43.8" r="1.78" fill="#008000"/>
<circle cx="135.2" cy="43.8" r="1.78" fill="none" stroke="#008000" stroke-width=".2"/>
<circle cx="135.2" cy="43.8" r="1.18" fill="#fff"/>
<circle cx="135.2" cy="43.8" r="1.18" fill="none" stroke="#000" stroke-width=".2"/>
<circle cx="135.2" cy="37.9" r="1.78" fill="#008000"/>
<circle cx="135.2" cy="37.9" r="1.78" fill="none" stroke="#008000" stroke-width=".2"/>
<circle cx="135.2" cy="37.9" r="1.18" fill="#fff"/>
<circle cx="135.2" cy="37.9" r="1.18" fill="none" stroke="#000" stroke-width=".2"/>
<circle cx="141.1" cy="43.8" r="1.78" fill="#008000"/>
<circle cx="141.1" cy="43.8" r="1.78" fill="none" stroke="#008000" stroke-width=".2"/>
<circle cx="141.1" cy="43.8" r="1.18" fill="#fff"/>
<circle cx="141.1" cy="43.8" r="1.18" fill="none" stroke="#000" stroke-width=".2"/>
<circle cx="141.1" cy="37.9" r="1.78" fill="#008000"/>
<circle cx="141.1" cy="37.9" r="1.78" fill="none" stroke="#008000" stroke-width=".2"/>
<circle cx="141.1" cy="37.9" r="1.18" fill="#fff"/>
<circle cx="141.1" cy="37.9" r="1.18" fill="none" stroke="#000" stroke-width=".2"/>
<circle cx="147.1" cy="43.8" r="1.78" fill="#008000"/>
<circle cx="147.1" cy="43.8" r="1.78" fill="none" stroke="#008000" stroke-width=".2"/>
<circle cx="147.1" cy="43.8" r="1.18" fill="#fff"/>
<circle cx="147.1" cy="43.8" r="1.18" fill="none" stroke="#000" stroke-width=".2"/>
<circle cx="147.1" cy="37.9" r="1.78" fill="#008000"/>
<circle cx="147.1" cy="37.9" r="1.78" fill="none" stroke="#008000" stroke-width=".2"/>
<circle cx="147.1" cy="37.9" r="1.18" fill="#fff"/>
<circle cx="147.1" cy="37.9" r="1.18" fill="none" stroke="#000" stroke-width=".2"/>
<circle cx="153" cy="43.8" r="1.78" fill="#008000"/>
<circle cx="153" cy="43.8" r="1.78" fill="none" stroke="#008000" stroke-width=".2"/>
<circle cx="153" cy="43.8" r="1.18" fill="#fff"/>
<circle cx="153" cy="43.8" r="1.18" fill="none" stroke="#000" stroke-width=".2"/>
<circle cx="153" cy="37.9" r="1.78" fill="#008000"/>
<circle cx="153" cy="37.9" r="1.78" fill="none" stroke="#008000" stroke-width=".2"/>
<circle cx="153" cy="37.9" r="1.18" fill="#fff"/>
<circle cx="153" cy="37.9" r="1.18" fill="none" stroke="#000" stroke-width=".2"/>
<circle cx="159" cy="43.8" r="1.78" fill="#008000"/>
<circle cx="159" cy="43.8" r="1.78" fill="none" stroke="#008000" stroke-width=".2"/>
<circle cx="159" cy="43.8" r="1.18" fill="#fff"/>
<circle cx="159" cy="43.8" r="1.18" fill="none" stroke="#000" stroke-width=".2"/>
<circle cx="159" cy="37.9" r="1.78" fill="#008000"/>
<circle cx="159" cy="37.9" r="1.78" fill="none" stroke="#008000" stroke-width=".2"/>
<circle cx="159" cy="37.9" r="1.18" fill="#fff"/>
<circle cx="159" cy="37.9" r="1.18" fill="none" stroke="#000" stroke-width=".2"/>
<circle cx="164.9" cy="43.8" r="1.78" fill="#008000"/>
<circle cx="164.9" cy="43.8" r="1.78" fill="none" stroke="#008000" stroke-width=".2"/>
<circle cx="164.9" cy="43.8" r="1.18" fill="#fff"/>
<circle cx="164.9" cy="43.8" r="1.18" fill="none" stroke="#000" stroke-width=".2"/>
<circle cx="164.9" cy="37.9" r="1.78" fill="#008000"/>
<circle cx="164.9" cy="37.9" r="1.78" fill="none" stroke="#008000" stroke-width=".2"/>
<circle cx="164.9" cy="37.9" r="1.18" fill="#fff"/>
<circle cx="164.9" cy="37.9" r="1.18" fill="none" stroke="#000" stroke-width=".2"/>
<circle cx="170.9" cy="43.8" r="1.78" fill="#008000"/>
<circle cx="170.9" cy="43.8" r="1.78" fill="none" stroke="#008000" stroke-width=".2"/>
<circle cx="170.9" cy="43.8" r="1.18" fill="#fff"/>
<circle cx="170.9" cy="43.8" r="1.18" fill="none" stroke="#000" stroke-width=".2"/>
<circle cx="170.9" cy="37.9" r="1.78" fill="#008000"/>
<circle cx="170.9" cy="37.9" r="1.78" fill="none" stroke="#008000" stroke-width=".2"/>
<circle cx="170.9" cy="37.9" r="1.18" fill="#fff"/>
<circle cx="170.9" cy="37.9" r="1.18" fill="none" stroke="#000" stroke-width=".2"/>
<circle cx="176.8" cy="43.8" r="1.78" fill="#008000"/>
<circle cx="176.8" cy="43.8" r="1.78" fill="none" stroke="#008000" stroke-width=".2"/>
<circle cx="176.8" cy="43.8" r="1.18" fill="#fff"/>
<circle cx="176.8" cy="43.8" r="1.18" fill="none" stroke="#000" stroke-width=".2"/>
<circle cx="176.8" cy="37.9" r="1.78" fill="#008000"/>
<circle cx="176.8" cy="37.9" r="1.78" fill="none" stroke="#008000" stroke-width=".2"/>
<circle cx="176.8" cy="37.9" r="1.18" fill="#fff"/>
<circle cx="176.8" cy="37.9" r="1.18" fill="none" stroke="#000" stroke-width=".2"/>
<circle cx="182.7" cy="43.8" r="1.78" fill="#008000"/>
<circle cx="182.7" cy="43.8" r="1.78" fill="none" stroke="#008000" stroke-width=".2"/>
<circle cx="182.7" cy="43.8" r="1.18" fill="#fff"/>
<circle cx="182.7" cy="43.8" r="1.18" fill="none" stroke="#000" stroke-width=".2"/>
<circle cx="182.7" cy="37.9" r="1.78" fill="#008000"/>
<circle cx="182.7" cy="37.9" r="1.78" fill="none" stroke="#008000" stroke-width=".2"/>
<circle cx="182.7" cy="37.9" r="1.18" fill="#fff"/>
<circle cx="182.7" cy="37.9" r="1.18" fill="none" stroke="#000" stroke-width=".2"/>
<circle cx="34.2" cy="55.7" r="1.78" fill="#008000"/>
<circle cx="34.2" cy="55.7" r="1.78" fill="none" stroke="#008000" stroke-width=".2"/>
<circle cx="34.2" cy="55.7" r="1.18" fill="#fff"/>
<circle cx="34.2" cy="55.7" r="1.18" fill="none" stroke="#000" stroke-width=".2"/>
<circle cx="34.2" cy="49.7" r="1.78" fill="#008000"/>
<circle cx="34.2" cy="49.7" r="1.78" fill="none" stroke="#008000" stroke-width=".2"/>
<circle cx="34.2" cy="49.7" r="1.18" fill="#fff"/>
<circle cx="34.2" cy="49.7" r="1.18" fill="none" stroke="#000" stroke-width=".2"/>
<circle cx="40.1" cy="55.7" r="1.78" fill="#008000"/>
<circle cx="40.1" cy="55.7" r="1.78" fill="none" stroke="#008000" stroke-width=".2"/>
<circle cx="40.1" cy="55.7" r="1.18" fill="#fff"/>
<circle cx="40.1" cy="55.7" r="1.18" fill="none" stroke="#000" stroke-width=".2"/>
<circle cx="40.1" cy="49.7" r="1.78" fill="#008000"/>
<circle cx="40.1" cy="49.7" r="1.78" fill="none" stroke="#008000" stroke-width=".2"/>
<circle cx="40.1" cy="49.7" r="1.18" fill="#fff"/>
<circle cx="40.1" cy="49.7" r="1.18" fill="none" stroke="#000" stroke-width=".2"/>
<circle cx="46.1" cy="55.7" r="1.78" fill="#008000"/>
<circle cx="46.1" cy="55.7" r="1.78" fill="none" stroke="#008000" stroke-width=".2"/>
<circle cx="46.1" cy="55.7" r="1.18" fill="#fff"/>
<circle cx="46.1" cy="55.7" r="1.18" fill="none" stroke="#000" stroke-width=".2"/>
<circle cx="46.1" cy="49.7" r="1.78" fill="#008000"/>
<circle cx="46.1" cy="49.7" r="1.78" fill="none" stroke="#008000" stroke-width=".2"/>
<circle cx="46.1" cy="49.7" r="1.18" fill="#fff"/>
<circle cx="46.1" cy="49.7" r="1.18" fill="none" stroke="#000" stroke-width=".2"/>
<circle cx="52" cy="55.7" r="1.78" fill="#008000"/>
<circle cx="52" cy="55.7" r="1.78" fill="none" stroke="#008000" stroke-width=".2"/>
<circle cx="52" cy="55.7" r="1.18" fill="#fff"/>
<circle cx="52" cy="55.7" r="1.18" fill="none" stroke="#000" stroke-width=".2"/>
<circle cx="52" cy="49.7" r="1.78" fill="#008000"/>
<circle cx="52" cy="49.7" r="1.78" fill="none" stroke="#008000" stroke-width=".2"/>
<circle cx="52" cy="49.7" r="1.18" fill="#fff"/>
<circle cx="52" cy="49.7" r="1.18" fill="none" stroke="#000" stroke-width=".2"/>
<circle cx="58" cy="55.7" r="1.78" fill="#008000"/>
<circle cx="58" cy="55.7" r="1.78" fill="none" stroke="#008000" stroke-width=".2"/>
<circle cx="58" cy="55.7" r="1.18" fill="#fff"/>
<circle cx="58" cy="55.7" r="1.18" fill="none" stroke="#000" stroke-width=".2"/>
<circle cx="58" cy="49.7" r="1.78" fill="#008000"/>
<circle cx="58" cy="49.7" r="1.78" fill="none" stroke="#008000" stroke-width=".2"/>
<circle cx="58" cy="49.7" r="1.18" fill="#fff"/>
<circle cx="58" cy="49.7" r="1.18" fill="none" stroke="#000" stroke-width=".2"/>
<circle cx="63.9" cy="55.7" r="1.78" fill="#008000"/>
<circle cx="63.9" cy="55.7" r="1.78" fill="none" stroke="#008000" stroke-width=".2"/>
<circle cx="63.9" cy="55.7" r="1.18" fill="#fff"/>
<circle cx="63.9" cy="55.7" r="1.18" fill="none" stroke="#000" stroke-width=".2"/>
<circle cx="63.9" cy="49.7" r="1.78" fill="#008000"/>
<circle cx="63.9" cy="49.7" r="1.78" fill="none" stroke="#008000" stroke-width=".2"/>
<circle cx="63.9" cy="49.7" r="1.18" fill="#fff"/>
<circle cx="63.9" cy="49.7" r="1.18" fill="none" stroke="#000" stroke-width=".2"/>
<circle cx="69.9" cy="55.7" r="1.78" fill="#008000"/>
<circle cx="69.9" cy="55.7" r="1.78" fill="none" stroke="#008000" stroke-width=".2"/>
<circle cx="69.9" cy="55.7" r="1.18" fill="#fff"/>
<circle cx="69.9" cy="55.7" r="1.18" fill="none" stroke="#000" stroke-width=".2"/>
<circle cx="69.9" cy="49.7" r="1.78" fill="#008000"/>
<circle cx="69.9" cy="49.7" r="1.78" fill="none" stroke="#008000" stroke-width=".2"/>
<circle cx="69.9" cy="49.7" r="1.18" fill="#fff"/>
<circle cx="69.9" cy="49.7" r="1.18" fill="none" stroke="#000" stroke-width=".2"/>
<circle cx="75.8" cy="55.7" r="1.78" fill="#008000"/>
<circle cx="75.8" cy="55.7" r="1.78" fill="none" stroke="#008000" stroke-width=".2"/>
<circle cx="75.8" cy="55.7" r="1.18" fill="#fff"/>
<circle cx="75.8" cy="55.7" r="1.18" fill="none" stroke="#000" stroke-width=".2"/>
<circle cx="75.8" cy="49.7" r="1.78" fill="#008000"/>
<circle cx="75.8" cy="49.7" r="1.78" fill="none" stroke="#008000" stroke-width=".2"/>
<circle cx="75.8" cy="49.7" r="1.18" fill="#fff"/>
<circle cx="75.8" cy="49.7" r="1.18" fill="none" stroke="#000" stroke-width=".2"/>
<circle cx="81.7" cy="55.7" r="1.78" fill="#008000"/>
<circle cx="81.7" cy="55.7" r="1.78" fill="none" stroke="#008000" stroke-width=".2"/>
<circle cx="81.7" cy="55.7" r="1.18" fill="#fff"/>
<circle cx="81.7" cy="55.7" r="1.18" fill="none" stroke="#000" stroke-width=".2"/>
<circle cx="81.7" cy="49.7" r="1.78" fill="#008000"/>
<circle cx="81.7" cy="49.7" r="1.78" fill="none" stroke="#008000" stroke-width=".2"/>
<circle cx="81.7" cy="49.7" r="1.18" fill="#fff"/>
<circle cx="81.7" cy="49.7" r="1.18" fill="none" stroke="#000" stroke-width=".2"/>
<circle cx="87.7" cy="55.7" r="1.78" fill="#008000"/>
<circle cx="87.7" cy="55.7" r="1.78" fill="none" stroke="#008000" stroke-width=".2"/>
<circle cx="87.7" cy="55.7" r="1.18" fill="#fff"/>
<circle cx="87.7" cy="55.7" r="1.18" fill="none" stroke="#000" stroke-width=".2"/>
<circle cx="87.7" cy="49.7" r="1.78" fill="#008000"/>
<circle cx="87.7" cy="49.7" r="1.78" fill="none" stroke="#008000" stroke-width=".2"/>
<circle cx="87.7" cy="49.7" r="1.18" fill="#fff"/>
<circle cx="87.7" cy="49.7" r="1.18" fill="none" stroke="#000" stroke-width=".2"/>
<circle cx="93.6" cy="55.7" r="1.78" fill="#008000"/>
<circle cx="93.6" cy="55.7" r="1.78" fill="none" stroke="#008000" stroke-width=".2"/>
<circle cx="93.6" cy="55.7" r="1.18" fill="#fff"/>
<circle cx="93.6" cy="55.7" r="1.18" fill="none" stroke="#000" stroke-width=".2"/>
<circle cx="93.6" cy="49.7" r="1.78" fill="#008000"/>
<circle cx="93.6" cy="49.7" r="1.78" fill="none" stroke="#008000" stroke-width=".2"/>
<circle cx="93.6" cy="49.7" r="1.18" fill="#fff"/>
<circle cx="93.6" cy="49.7" r="1.18" fill="none" stroke="#000" stroke-width=".2"/>
<circle cx="99.5" cy="55.7" r="1.78" fill="#008000"/>
<circle cx="99.5" cy="55.7" r="1.78" fill="none" stroke="#008000" stroke-width=".2"/>
<circle cx="99.5" cy="55.7" r="1.18" fill="#fff"/>
<circle cx="99.5" cy="55.7" r="1.18" fill="none" stroke="#000" stroke-width=".2"/>
<circle cx="99.5" cy="49.7" r="1.78" fill="#008000"/>
<circle cx="99.5" cy="49.7" r="1.78" fill="none" stroke="#008000" stroke-width=".2"/>
<circle cx="99.5" cy="49.7" r="1.18" fill="#fff"/>
<circle cx="99.5" cy="49.7" r="1.18" fill="none" stroke="#000" stroke-width=".2"/>
<circle cx="105.5" cy="55.7" r="1.78" fill="#008000"/>
<circle cx="105.5" cy="55.7" r="1.78" fill="none" stroke="#008000" stroke-width=".2"/>
<circle cx="105.5" cy="55.7" r="1.18" fill="#fff"/>
<circle cx="105.5" cy="55.7" r="1.18" fill="none" stroke="#000" stroke-width=".2"/>
<circle cx="105.5" cy="49.7" r="1.78" fill="#008000"/>
<circle cx="105.5" cy="49.7" r="1.78" fill="none" stroke="#008000" stroke-width=".2"/>
<circle cx="105.5" cy="49.7" r="1.18" fill="#fff"/>
<circle cx="105.5" cy="49.7" r="1.18" fill="none" stroke="#000" stroke-width=".2"/>
<circle cx="111.4" cy="55.7" r="1.78" fill="#008000"/>
<circle cx="111.4" cy="55.7" r="1.78" fill="none" stroke="#008000" stroke-width=".2"/>
<circle cx="111.4" cy="55.7" r="1.18" fill="#fff"/>
<circle cx="111.4" cy="55.7" r="1.18" fill="none" stroke="#000" stroke-width=".2"/>
<circle cx="111.4" cy="49.7" r="1.78" fill="#008000"/>
<circle cx="111.4" cy="49.7" r="1.78" fill="none" stroke="#008000" stroke-width=".2"/>
<circle cx="111.4" cy="49.7" r="1.18" fill="#fff"/>
<circle cx="111.4" cy="49.7" r="1.18" fill="none" stroke="#000" stroke-width=".2"/>
<circle cx="117.4" cy="55.7" r="1.78" fill="#008000"/>
<circle cx="117.4" cy="55.7" r="1.78" fill="none" stroke="#008000" stroke-width=".2"/>
<circle cx="117.4" cy="55.7" r="1.18" fill="#fff"/>
<circle cx="117.4" cy="55.7" r="1.18" fill="none" stroke="#000" stroke-width=".2"/>
<circle cx="117.4" cy="49.7" r="1.78" fill="#008000"/>
<circle cx="117.4" cy="49.7" r="1.78" fill="none" stroke="#008000" stroke-width=".2"/>
<circle cx="117.4" cy="49.7" r="1.18" fill="#fff"/>
<circle cx="117.4" cy="49.7" r="1.18" fill="none" stroke="#000" stroke-width=".2"/>
<circle cx="123.3" cy="55.7" r="1.78" fill="#008000"/>
<circle cx="123.3" cy="55.7" r="1.78" fill="none" stroke="#008000" stroke-width=".2"/>
<circle cx="123.3" cy="55.7" r="1.18" fill="#fff"/>
<circle cx="123.3" cy="55.7" r="1.18" fill="none" stroke="#000" stroke-width=".2"/>
<circle cx="123.3" cy="49.7" r="1.78" fill="#008000"/>
<circle cx="123.3" cy="49.7" r="1.78" fill="none" stroke="#008000" stroke-width=".2"/>
<circle cx="123.3" cy="49.7" r="1.18" fill="#fff"/>
<circle cx="123.3" cy="49.7" r="1.18" fill="none" stroke="#000" stroke-width=".2"/>
<circle cx="129.2" cy="55.7" r="1.78" fill="#008000"/>
<circle cx="129.2" cy="55.7" r="1.78" fill="none" stroke="#008000" stroke-width=".2"/>
<circle cx="129.2" cy="55.7" r="1.18" fill="#fff"/>
<circle cx="129.2" cy="55.7" r="1.18" fill="none" stroke="#000" stroke-width=".2"/>
<circle cx="129.2" cy="49.7" r="1.78" fill="#008000"/>
<circle cx="129.2" cy="49.7" r="1.78" fill="none" stroke="#008000" stroke-width=".2"/>
<circle cx="129.2" cy="49.7" r="1.18" fill="#fff"/>
<circle cx="129.2" cy="49.7" r="1.18" fill="none" stroke="#000" stroke-width=".2"/>
<circle cx="135.2" cy="55.7" r="1.78" fill="#008000"/>
<circle cx="135.2" cy="55.7" r="1.78" fill="none" stroke="#008000" stroke-width=".2"/>
<circle cx="135.2" cy="55.7" r="1.18" fill="#fff"/>
<circle cx="135.2" cy="55.7" r="1.18" fill="none" stroke="#000" stroke-width=".2"/>
<circle cx="135.2" cy="49.7" r="1.78" fill="#008000"/>
<circle cx="135.2" cy="49.7" r="1.78" fill="none" stroke="#008000" stroke-width=".2"/>
<circle cx="135.2" cy="49.7" r="1.18" fill="#fff"/>
<circle cx="135.2" cy="49.7" r="1.18" fill="none" stroke="#000" stroke-width=".2"/>
<circle cx="141.1" cy="55.7" r="1.78" fill="#008000"/>
<circle cx="141.1" cy="55.7" r="1.78" fill="none" stroke="#008000" stroke-width=".2"/>
<circle cx="141.1" cy="55.7" r="1.18" fill="#fff"/>
<circle cx="141.1" cy="55.7" r="1.18" fill="none" stroke="#000" stroke-width=".2"/>
<circle cx="141.1" cy="49.7" r="1.78" fill="#008000"/>
<circle cx="141.1" cy="49.7" r="1.78" fill="none" stroke="#008000" stroke-width=".2"/>
<circle cx="141.1" cy="49.7" r="1.18" fill="#fff"/>
<circle cx="141.1" cy="49.7" r="1.18" fill="none" stroke="#000" stroke-width=".2"/>
<circle cx="147.1" cy="55.7" r="1.78" fill="#008000"/>
<circle cx="147.1" cy="55.7" r="1.78" fill="none" stroke="#008000" stroke-width=".2"/>
<circle cx="147.1" cy="55.7" r="1.18" fill="#fff"/>
<circle cx="147.1" cy="55.7" r="1.18" fill="none" stroke="#000" stroke-width=".2"/>
<circle cx="147.1" cy="49.7" r="1.78" fill="#008000"/>
<circle cx="147.1" cy="49.7" r="1.78" fill="none" stroke="#008000" stroke-width=".2"/>
<circle cx="147.1" cy="49.7" r="1.18" fill="#fff"/>
<circle cx="147.1" cy="49.7" r="1.18" fill="none" stroke="#000" stroke-width=".2"/>
<circle cx="153" cy="55.7" r="1.78" fill="#008000"/>
<circle cx="153" cy="55.7" r="1.78" fill="none" stroke="#008000" stroke-width=".2"/>
<circle cx="153" cy="55.7" r="1.18" fill="#fff"/>
<circle cx="153" cy="55.7" r="1.18" fill="none" stroke="#000" stroke-width=".2"/>
<circle cx="153" cy="49.7" r="1.78" fill="#008000"/>
<circle cx="153" cy="49.7" r="1.78" fill="none" stroke="#008000" stroke-width=".2"/>
<circle cx="153" cy="49.7" r="1.18" fill="#fff"/>
<circle cx="153" cy="49.7" r="1.18" fill="none" stroke="#000" stroke-width=".2"/>
<circle cx="159" cy="55.7" r="1.78" fill="#008000"/>
<circle cx="159" cy="55.7" r="1.78" fill="none" stroke="#008000" stroke-width=".2"/>
<circle cx="159" cy="55.7" r="1.18" fill="#fff"/>
<circle cx="159" cy="55.7" r="1.18" fill="none" stroke="#000" stroke-width=".2"/>
<circle cx="159" cy="49.7" r="1.78" fill="#008000"/>
<circle cx="159" cy="49.7" r="1.78" fill="none" stroke="#008000" stroke-width=".2"/>
<circle cx="159" cy="49.7" r="1.18" fill="#fff"/>
<circle cx="159" cy="49.7" r="1.18" fill="none" stroke="#000" stroke-width=".2"/>
<circle cx="164.9" cy="55.7" r="1.78" fill="#008000"/>
<circle cx="164.9" cy="55.7" r="1.78" fill="none" stroke="#008000" stroke-width=".2"/>
<circle cx="164.9" cy="55.7" r="1.18" fill="#fff"/>
<circle cx="164.9" cy="55.7" r="1.18" fill="none" stroke="#000" stroke-width=".2"/>
<circle cx="164.9" cy="49.7" r="1.78" fill="#008000"/>
<circle cx="164.9" cy="49.7" r="1.78" fill="none" stroke="#008000" stroke-width=".2"/>
<circle cx="164.9" cy="49.7" r="1.18" fill="#fff"/>
<circle cx="164.9" cy="49.7" r="1.18" fill="none" stroke="#000" stroke-width=".2"/>
<circle cx="170.8" cy="55.7" r="1.78" fill="#008000"/>
<circle cx="170.8" cy="55.7" r="1.78" fill="none" stroke="#008000" stroke-width=".2"/>
<circle cx="170.8" cy="55.7" r="1.18" fill="#fff"/>
<circle cx="170.8" cy="55.7" r="1.18" fill="none" stroke="#000" stroke-width=".2"/>
<circle cx="170.8" cy="49.7" r="1.78" fill="#008000"/>
<circle cx="170.8" cy="49.7" r="1.78" fill="none" stroke="#008000" stroke-width=".2"/>
<circle cx="170.8" cy="49.7" r="1.18" fill="#fff"/>
<circle cx="170.8" cy="49.7" r="1.18" fill="none" stroke="#000" stroke-width=".2"/>
<circle cx="176.8" cy="55.7" r="1.78" fill="#008000"/>
<circle cx="176.8" cy="55.7" r="1.78" fill="none" stroke="#008000" stroke-width=".2"/>
<circle cx="176.8" cy="55.7" r="1.18" fill="#fff"/>
<circle cx="176.8" cy="55.7" r="1.18" fill="none" stroke="#000" stroke-width=".2"/>
<circle cx="176.8" cy="49.7" r="1.78" fill="#008000"/>
<circle cx="176.8" cy="49.7" r="1.78" fill="none" stroke="#008000" stroke-width=".2"/>
<circle cx="176.8" cy="49.7" r="1.18" fill="#fff"/>
<circle cx="176.8" cy="49.7" r="1.18" fill="none" stroke="#000" stroke-width=".2"/>
<circle cx="182.7" cy="55.7" r="1.78" fill="#008000"/>
<circle cx="182.7" cy="55.7" r="1.78" fill="none" stroke="#008000" stroke-width=".2"/>
<circle cx="182.7" cy="55.7" r="1.18" fill="#fff"/>
<circle cx="182.7" cy="55.7" r="1.18" fill="none" stroke="#000" stroke-width=".2"/>
<circle cx="182.7" cy="49.7" r="1.78" fill="#008000"/>
<circle cx="182.7" cy="49.7" r="1.78" fill="none" stroke="#008000" stroke-width=".2"/>
<circle cx="182.7" cy="49.7" r="1.18" fill="#fff"/>
<circle cx="182.7" cy="49.7" r="1.18" fill="none" stroke="#000" stroke-width=".2"/>
<circle cx="197.6" cy="140.2" r="1.18" fill="#008000"/>
<circle cx="197.6" cy="140.2" r="1.18" fill="none" stroke="#008000" stroke-width=".2"/>
<circle cx="197.6" cy="140.2" r=".72" fill="#fff"/>
<circle cx="197.6" cy="140.2" r=".72" fill="none" stroke="#000" stroke-width=".2"/>
<circle cx="189.4" cy="140.2" r="1.18" fill="#008000"/>
<circle cx="189.4" cy="140.2" r="1.18" fill="none" stroke="#008000" stroke-width=".2"/>
<circle cx="189.4" cy="140.2" r=".72" fill="#fff"/>
<circle cx="189.4" cy="140.2" r=".72" fill="none" stroke="#000" stroke-width=".2"/>
<circle cx="193.7" cy="199" r="1.18" fill="#008000"/>
<circle cx="193.7" cy="199" r="1.18" fill="none" stroke="#008000" stroke-width=".2"/>
<circle cx="193.7" cy="199" r=".72" fill="#fff"/>
<circle cx="193.7" cy="199" r=".72" fill="none" stroke="#000" stroke-width=".2"/>
<circle cx="199.8" cy="192.9" r="1.18" fill="#008000"/>
<circle cx="199.8" cy="192.9" r="1.18" fill="none" stroke="#008000" stroke-width=".2"/>
<circle cx="199.8" cy="192.9" r=".72" fill="#fff"/>
<circle cx="199.8" cy="192.9" r=".72" fill="none" stroke="#000" stroke-width=".2"/>
<circle cx="197.9" cy="213.2" r="1.18" fill="#008000"/>
<circle cx="197.9" cy="213.2" r="1.18" fill="none" stroke="#008000" stroke-width=".2"/>
<circle cx="197.9" cy="213.1" r=".72" fill="#fff"/>
<circle cx="197.9" cy="213.1" r=".72" fill="none" stroke="#000" stroke-width=".2"/>
<circle cx="188.9" cy="213.2" r="1.18" fill="#008000"/>
<circle cx="188.9" cy="213.2" r="1.18" fill="none" stroke="#008000" stroke-width=".2"/>
<circle cx="188.9" cy="213.1" r=".72" fill="#fff"/>
<circle cx="188.9" cy="213.1" r=".72" fill="none" stroke="#000" stroke-width=".2"/>
<circle cx="175.6" cy="203.3" r="1.18" fill="#008000"/>
<circle cx="175.6" cy="203.3" r="1.18" fill="none" stroke="#008000" stroke-width=".2"/>
<circle cx="175.6" cy="203.3" r=".72" fill="#fff"/>
<circle cx="175.6" cy="203.3" r=".72" fill="none" stroke="#000" stroke-width=".2"/>
<circle cx="187" cy="203.3" r="1.18" fill="#008000"/>
<circle cx="187" cy="203.3" r="1.18" fill="none" stroke="#008000" stroke-width=".2"/>
<circle cx="187" cy="203.3" r=".72" fill="#fff"/>
<circle cx="187" cy="203.3" r=".72" fill="none" stroke="#000" stroke-width=".2"/>
<circle cx="100.5" cy="60.5" r="1.18" fill="#008000"/>
<circle cx="100.5" cy="60.5" r="1.18" fill="none" stroke="#008000" stroke-width=".2"/>
<circle cx="100.5" cy="60.5" r=".72" fill="#fff"/>
<circle cx="100.5" cy="60.5" r=".72" fill="none" stroke="#000" stroke-width=".2"/>
<circle cx="54.9" cy="222.7" r="1.18" fill="#008000"/>
<circle cx="54.9" cy="222.7" r="1.18" fill="none" stroke="#008000" stroke-width=".2"/>
<circle cx="54.9" cy="222.7" r=".72" fill="#fff"/>
<circle cx="54.9" cy="222.7" r=".72" fill="none" stroke="#000" stroke-width=".2"/>
<circle cx="72.6" cy="128.1" r="1.18" fill="#008000"/>
<circle cx="72.6" cy="128.1" r="1.18" fill="none" stroke="#008000" stroke-width=".2"/>
<circle cx="72.6" cy="128.1" r=".72" fill="#fff"/>
<circle cx="72.6" cy="128.1" r=".72" fill="none" stroke="#000" stroke-width=".2"/>
<circle cx="92" cy="213.4" r="1.18" fill="#008000"/>
<circle cx="92" cy="213.4" r="1.18" fill="none" stroke="#008000" stroke-width=".2"/>
<circle cx="92" cy="213.4" r=".72" fill="#fff"/>
<circle cx="92" cy="213.4" r=".72" fill="none" stroke="#000" stroke-width=".2"/>
<circle cx="95.2" cy="202.4" r="1.18" fill="#008000"/>
<circle cx="95.2" cy="202.4" r="1.18" fill="none" stroke="#008000" stroke-width=".2"/>
<circle cx="95.2" cy="202.4" r=".72" fill="#fff"/>
<circle cx="95.2" cy="202.4" r=".72" fill="none" stroke="#000" stroke-width=".2"/>
<circle cx="106.3" cy="216.2" r="1.18" fill="#008000"/>
<circle cx="106.3" cy="216.2" r="1.18" fill="none" stroke="#008000" stroke-width=".2"/>
<circle cx="106.3" cy="216.2" r=".72" fill="#fff"/>
<circle cx="106.3" cy="216.2" r=".72" fill="none" stroke="#000" stroke-width=".2"/>
<circle cx="106.3" cy="207.3" r="1.18" fill="#008000"/>
<circle cx="106.3" cy="207.3" r="1.18" fill="none" stroke="#008000" stroke-width=".2"/>
<circle cx="106.3" cy="207.3" r=".72" fill="#fff"/>
<circle cx="106.3" cy="207.3" r=".72" fill="none" stroke="#000" stroke-width=".2"/>
<circle cx="182.5" cy="122.2" r="1.18" fill="#008000"/>
<circle cx="182.5" cy="122.2" r="1.18" fill="none" stroke="#008000" stroke-width=".2"/>
<circle cx="182.5" cy="122.2" r=".72" fill="#fff"/>
<circle cx="182.5" cy="122.2" r=".72" fill="none" stroke="#000" stroke-width=".2"/>
<circle cx="170.6" cy="137.6" r="1.18" fill="#008000"/>
<circle cx="170.6" cy="137.6" r="1.18" fill="none" stroke="#008000" stroke-width=".2"/>
<circle cx="170.6" cy="137.6" r=".72" fill="#fff"/>
<circle cx="170.6" cy="137.6" r=".72" fill="none" stroke="#000" stroke-width=".2"/>
<circle cx="207.6" cy="111.4" r="1.18" fill="#008000"/>
<circle cx="207.6" cy="111.4" r="1.18" fill="none" stroke="#008000" stroke-width=".2"/>
<circle cx="207.6" cy="111.4" r=".72" fill="#fff"/>
<circle cx="207.6" cy="111.4" r=".72" fill="none" stroke="#000" stroke-width=".2"/>
<circle cx="116" cy="92.2" r="1.18" fill="#008000"/>
<circle cx="116" cy="92.2" r="1.18" fill="none" stroke="#008000" stroke-width=".2"/>
<circle cx="116" cy="92.2" r=".72" fill="#fff"/>
<circle cx="116" cy="92.2" r=".72" fill="none" stroke="#000" stroke-width=".2"/>
<circle cx="71.2" cy="219.2" r="1.18" fill="#008000"/>
<circle cx="71.2" cy="219.2" r="1.18" fill="none" stroke="#008000" stroke-width=".2"/>
<circle cx="71.2" cy="219.2" r=".72" fill="#fff"/>
<circle cx="71.2" cy="219.2" r=".72" fill="none" stroke="#000" stroke-width=".2"/>
<circle cx="66.6" cy="202.9" r="1.18" fill="#008000"/>
<circle cx="66.6" cy="202.9" r="1.18" fill="none" stroke="#008000" stroke-width=".2"/>
<circle cx="66.6" cy="202.9" r=".72" fill="#fff"/>
<circle cx="66.6" cy="202.9" r=".72" fill="none" stroke="#000" stroke-width=".2"/>
<circle cx="110.3" cy="219.8" r="1.18" fill="#008000"/>
<circle cx="110.3" cy="219.8" r="1.18" fill="none" stroke="#008000" stroke-width=".2"/>
<circle cx="110.3" cy="219.8" r=".72" fill="#fff"/>
<circle cx="110.3" cy="219.8" r=".72" fill="none" stroke="#000" stroke-width=".2"/>
<circle cx="107.7" cy="198.3" r="1.18" fill="#008000"/>
<circle cx="107.7" cy="198.3" r="1.18" fill="none" stroke="#008000" stroke-width=".2"/>
<circle cx="107.7" cy="198.3" r=".72" fill="#fff"/>
<circle cx="107.7" cy="198.3" r=".72" fill="none" stroke="#000" stroke-width=".2"/>
<circle cx="58" cy="62.7" r="1.18" fill="#008000"/>
<circle cx="58" cy="62.7" r="1.18" fill="none" stroke="#008000" stroke-width=".2"/>
<circle cx="58" cy="62.7" r=".72" fill="#fff"/>
<circle cx="58" cy="62.7" r=".72" fill="none" stroke="#000" stroke-width=".2"/>
<circle cx="58" cy="73.3" r="1.18" fill="#008000"/>
<circle cx="58" cy="73.3" r="1.18" fill="none" stroke="#008000" stroke-width=".2"/>
<circle cx="58" cy="73.3" r=".72" fill="#fff"/>
<circle cx="58" cy="73.3" r=".72" fill="none" stroke="#000" stroke-width=".2"/>
<circle cx="182" cy="194.5" r="1.18" fill="#008000"/>
<circle cx="182" cy="194.5" r="1.18" fill="none" stroke="#008000" stroke-width=".2"/>
<circle cx="182" cy="194.5" r=".72" fill="#fff"/>
<circle cx="182" cy="194.5" r=".72" fill="none" stroke="#000" stroke-width=".2"/>
<circle cx="207.7" cy="184.4" r="1.18" fill="#008000"/>
<circle cx="207.7" cy="184.4" r="1.18" fill="none" stroke="#008000" stroke-width=".2"/>
<circle cx="207.7" cy="184.4" r=".72" fill="#fff"/>
<circle cx="207.7" cy="184.4" r=".72" fill="none" stroke="#000" stroke-width=".2"/>
<circle cx="170.7" cy="212.5" r="1.18" fill="#008000"/>
<circle cx="170.7" cy="212.5" r="1.18" fill="none" stroke="#008000" stroke-width=".2"/>
<circle cx="170.7" cy="212.5" r=".72" fill="#fff"/>
<circle cx="170.7" cy="212.5" r=".72" fill="none" stroke="#000" stroke-width=".2"/>
<circle cx="73.8" cy="198.2" r="1.18" fill="#008000"/>
<circle cx="73.8" cy="198.2" r="1.18" fill="none" stroke="#008000" stroke-width=".2"/>
<circle cx="73.8" cy="198.2" r=".72" fill="#fff"/>
<circle cx="73.8" cy="198.2" r=".72" fill="none" stroke="#000" stroke-width=".2"/>
<circle cx="58" cy="82.2" r="1.18" fill="#008000"/>
<circle cx="58" cy="82.2" r="1.18" fill="none" stroke="#008000" stroke-width=".2"/>
<circle cx="58" cy="82.2" r=".72" fill="#fff"/>
<circle cx="58" cy="82.2" r=".72" fill="none" stroke="#000" stroke-width=".2"/>
<circle cx="93" cy="81.6" r="1.18" fill="#008000"/>
<circle cx="93" cy="81.6" r="1.18" fill="none" stroke="#008000" stroke-width=".2"/>
<circle cx="93" cy="81.6" r=".72" fill="#fff"/>
<circle cx="93" cy="81.6" r=".72" fill="none" stroke="#000" stroke-width=".2"/>
<circle cx="102.4" cy="80.9" r="1.18" fill="#008000"/>
<circle cx="102.4" cy="80.9" r="1.18" fill="none" stroke="#008000" stroke-width=".2"/>
<circle cx="102.4" cy="80.9" r=".72" fill="#fff"/>
<circle cx="102.4" cy="80.9" r=".72" fill="none" stroke="#000" stroke-width=".2"/>
<circle cx="102.2" cy="71.2" r="1.18" fill="#008000"/>
<circle cx="102.2" cy="71.2" r="1.18" fill="none" stroke="#008000" stroke-width=".2"/>
<circle cx="102.2" cy="71.2" r=".72" fill="#fff"/>
<circle cx="102.2" cy="71.2" r=".72" fill="none" stroke="#000" stroke-width=".2"/>
<circle cx="102.7" cy="188.8" r="1.18" fill="#008000"/>
<circle cx="102.7" cy="188.8" r="1.18" fill="none" stroke="#008000" stroke-width=".2"/>
<circle cx="102.7" cy="188.8" r=".72" fill="#fff"/>
<circle cx="102.7" cy="188.8" r=".72" fill="none" stroke="#000" stroke-width=".2"/>
<circle cx="80.4" cy="157.6" r="1.18" fill="#008000"/>
<circle cx="80.4" cy="157.6" r="1.18" fill="none" stroke="#008000" stroke-width=".2"/>
<circle cx="80.4" cy="157.6" r=".72" fill="#fff"/>
<circle cx="80.4" cy="157.6" r=".72" fill="none" stroke="#000" stroke-width=".2"/>
<circle cx="84.3" cy="171.8" r="1.18" fill="#008000"/>
<circle cx="84.3" cy="171.8" r="1.18" fill="none" stroke="#008000" stroke-width=".2"/>
<circle cx="84.3" cy="171.8" r=".72" fill="#fff"/>
<circle cx="84.3" cy="171.8" r=".72" fill="none" stroke="#000" stroke-width=".2"/>
<circle cx="26.4" cy="102.7" r="1.18" fill="#008000"/>
<circle cx="26.4" cy="102.7" r="1.18" fill="none" stroke="#008000" stroke-width=".2"/>
<circle cx="26.4" cy="102.7" r=".72" fill="#fff"/>
<circle cx="26.4" cy="102.7" r=".72" fill="none" stroke="#000" stroke-width=".2"/>
<circle cx="43.9" cy="103.2" r="1.18" fill="#008000"/>
<circle cx="43.9" cy="103.2" r="1.18" fill="none" stroke="#008000" stroke-width=".2"/>
<circle cx="43.9" cy="103.2" r=".72" fill="#fff"/>
<circle cx="43.9" cy="103.2" r=".72" fill="none" stroke="#000" stroke-width=".2"/>
<circle cx="176.5" cy="68.6" r="1.18" fill="#008000"/>
<circle cx="176.5" cy="68.6" r="1.18" fill="none" stroke="#008000" stroke-width=".2"/>
<circle cx="176.5" cy="68.6" r=".72" fill="#fff"/>
<circle cx="176.5" cy="68.6" r=".72" fill="none" stroke="#000" stroke-width=".2"/>
<circle cx="88.2" cy="74.6" r="1.18" fill="#008000"/>
<circle cx="88.2" cy="74.6" r="1.18" fill="none" stroke="#008000" stroke-width=".2"/>
<circle cx="88.2" cy="74.6" r=".72" fill="#fff"/>
<circle cx="88.2" cy="74.6" r=".72" fill="none" stroke="#000" stroke-width=".2"/>
<circle cx="110.1" cy="116" r="1.18" fill="#008000"/>
<circle cx="110.1" cy="116" r="1.18" fill="none" stroke="#008000" stroke-width=".2"/>
<circle cx="110.1" cy="116" r=".72" fill="#fff"/>
<circle cx="110.1" cy="116" r=".72" fill="none" stroke="#000" stroke-width=".2"/>
<circle cx="54.8" cy="199.9" r="1.18" fill="#008000"/>
<circle cx="54.8" cy="199.9" r="1.18" fill="none" stroke="#008000" stroke-width=".2"/>
<circle cx="54.8" cy="199.9" r=".72" fill="#fff"/>
<circle cx="54.8" cy="199.9" r=".72" fill="none" stroke="#000" stroke-width=".2"/>
<circle cx="54.8" cy="212.9" r="1.18" fill="#008000"/>
<circle cx="54.8" cy="212.9" r="1.18" fill="none" stroke="#008000" stroke-width=".2"/>
<circle cx="54.8" cy="212.9" r=".72" fill="#fff"/>
<circle cx="54.8" cy="212.9" r=".72" fill="none" stroke="#000" stroke-width=".2"/>
<circle cx="67.9" cy="215.6" r="1.18" fill="#008000"/>
<circle cx="67.9" cy="215.6" r="1.18" fill="none" stroke="#008000" stroke-width=".2"/>
<circle cx="67.9" cy="215.6" r=".72" fill="#fff"/>
<circle cx="67.9" cy="215.6" r=".72" fill="none" stroke="#000" stroke-width=".2"/>
<circle cx="67.9" cy="208.1" r="1.18" fill="#008000"/>
<circle cx="67.9" cy="208.1" r="1.18" fill="none" stroke="#008000" stroke-width=".2"/>
<circle cx="67.9" cy="208.1" r=".72" fill="#fff"/>
<circle cx="67.9" cy="208.1" r=".72" fill="none" stroke="#000" stroke-width=".2"/>
<circle cx="120.1" cy="68.6" r="1.18" fill="#008000"/>
<circle cx="120.1" cy="68.6" r="1.18" fill="none" stroke="#008000" stroke-width=".2"/>
<circle cx="120.1" cy="68.6" r=".72" fill="#fff"/>
<circle cx="120.1" cy="68.6" r=".72" fill="none" stroke="#000" stroke-width=".2"/>
<circle cx="130.4" cy="109.8" r="1.18" fill="#008000"/>
<circle cx="130.4" cy="109.8" r="1.18" fill="none" stroke="#008000" stroke-width=".2"/>
<circle cx="130.4" cy="109.8" r=".72" fill="#fff"/>
<circle cx="130.4" cy="109.8" r=".72" fill="none" stroke="#000" stroke-width=".2"/>
<circle cx="93.7" cy="60.5" r="1.18" fill="#008000"/>
<circle cx="93.7" cy="60.5" r="1.18" fill="none" stroke="#008000" stroke-width=".2"/>
<circle cx="93.7" cy="60.5" r=".72" fill="#fff"/>
<circle cx="93.7" cy="60.5" r=".72" fill="none" stroke="#000" stroke-width=".2"/>
<circle cx="64" cy="73.3" r="1.18" fill="#008000"/>
<circle cx="64" cy="73.3" r="1.18" fill="none" stroke="#008000" stroke-width=".2"/>
<circle cx="64" cy="73.3" r=".72" fill="#fff"/>
<circle cx="64" cy="73.3" r=".72" fill="none" stroke="#000" stroke-width=".2"/>
<circle cx="64" cy="82.2" r="1.18" fill="#008000"/>
<circle cx="64" cy="82.2" r="1.18" fill="none" stroke="#008000" stroke-width=".2"/>
<circle cx="64" cy="82.2" r=".72" fill="#fff"/>
<circle cx="64" cy="82.2" r=".72" fill="none" stroke="#000" stroke-width=".2"/>
<circle cx="175.4" cy="180.9" r="1.18" fill="#008000"/>
<circle cx="175.4" cy="180.9" r="1.18" fill="none" stroke="#008000" stroke-width=".2"/>
<circle cx="175.4" cy="180.8" r=".72" fill="#fff"/>
<circle cx="175.4" cy="180.8" r=".72" fill="none" stroke="#000" stroke-width=".2"/>
<circle cx="175.4" cy="188.7" r="1.18" fill="#008000"/>
<circle cx="175.4" cy="188.7" r="1.18" fill="none" stroke="#008000" stroke-width=".2"/>
<circle cx="175.4" cy="188.7" r=".72" fill="#fff"/>
<circle cx="175.4" cy="188.7" r=".72" fill="none" stroke="#000" stroke-width=".2"/>
<circle cx="126.6" cy="171.1" r="1.18" fill="#008000"/>
<circle cx="126.6" cy="171.1" r="1.18" fill="none" stroke="#008000" stroke-width=".2"/>
<circle cx="126.6" cy="171.1" r=".72" fill="#fff"/>
<circle cx="126.6" cy="171.1" r=".72" fill="none" stroke="#000" stroke-width=".2"/>
<circle cx="144.2" cy="173.3" r="1.18" fill="#008000"/>
<circle cx="144.2" cy="173.3" r="1.18" fill="none" stroke="#008000" stroke-width=".2"/>
<circle cx="144.2" cy="173.3" r=".72" fill="#fff"/>
<circle cx="144.2" cy="173.3" r=".72" fill="none" stroke="#000" stroke-width=".2"/>
<circle cx="66.6" cy="63" r="1.18" fill="#008000"/>
<circle cx="66.6" cy="63" r="1.18" fill="none" stroke="#008000" stroke-width=".2"/>
<circle cx="66.6" cy="63" r=".72" fill="#fff"/>
<circle cx="66.6" cy="63" r=".72" fill="none" stroke="#000" stroke-width=".2"/>
<circle cx="93.7" cy="60.5" r="1.18" fill="#008000"/>
<circle cx="93.7" cy="60.5" r="1.18" fill="none" stroke="#008000" stroke-width=".2"/>
<circle cx="93.7" cy="60.5" r=".72" fill="#fff"/>
<circle cx="93.7" cy="60.5" r=".72" fill="none" stroke="#000" stroke-width=".2"/>
<circle cx="76.5" cy="61" r="1.18" fill="#008000"/>
<circle cx="76.5" cy="61" r="1.18" fill="none" stroke="#008000" stroke-width=".2"/>
<circle cx="76.5" cy="61" r=".72" fill="#fff"/>
<circle cx="76.5" cy="61" r=".72" fill="none" stroke="#000" stroke-width=".2"/>
<circle cx="98.7" cy="131.7" r="1.18" fill="#008000"/>
<circle cx="98.7" cy="131.7" r="1.18" fill="none" stroke="#008000" stroke-width=".2"/>
<circle cx="98.7" cy="131.7" r=".72" fill="#fff"/>
<circle cx="98.7" cy="131.7" r=".72" fill="none" stroke="#000" stroke-width=".2"/>
<circle cx="87.8" cy="87.7" r="1.18" fill="#008000"/>
<circle cx="87.8" cy="87.7" r="1.18" fill="none" stroke="#008000" stroke-width=".2"/>
<circle cx="87.8" cy="87.7" r=".72" fill="#fff"/>
<circle cx="87.8" cy="87.7" r=".72" fill="none" stroke="#000" stroke-width=".2"/>
<circle cx="84.5" cy="90.4" r="1.18" fill="#008000"/>
<circle cx="84.5" cy="90.4" r="1.18" fill="none" stroke="#008000" stroke-width=".2"/>
<circle cx="84.5" cy="90.4" r=".72" fill="#fff"/>
<circle cx="84.5" cy="90.4" r=".72" fill="none" stroke="#000" stroke-width=".2"/>
<circle cx="96.1" cy="134.4" r="1.18" fill="#008000"/>
<circle cx="96.1" cy="134.4" r="1.18" fill="none" stroke="#008000" stroke-width=".2"/>
<circle cx="96.1" cy="134.4" r=".72" fill="#fff"/>
<circle cx="96.1" cy="134.4" r=".72" fill="none" stroke="#000" stroke-width=".2"/>
<circle cx="55.1" cy="73.3" r="1.18" fill="#008000"/>
<circle cx="55.1" cy="73.3" r="1.18" fill="none" stroke="#008000" stroke-width=".2"/>
<circle cx="55.1" cy="73.3" r=".72" fill="#fff"/>
<circle cx="55.1" cy="73.3" r=".72" fill="none" stroke="#000" stroke-width=".2"/>
<circle cx="55.1" cy="82.2" r="1.18" fill="#008000"/>
<circle cx="55.1" cy="82.2" r="1.18" fill="none" stroke="#008000" stroke-width=".2"/>
<circle cx="55.1" cy="82.2" r=".72" fill="#fff"/>
<circle cx="55.1" cy="82.2" r=".72" fill="none" stroke="#000" stroke-width=".2"/>
<circle cx="55.1" cy="120.7" r="1.18" fill="#008000"/>
<circle cx="55.1" cy="120.7" r="1.18" fill="none" stroke="#008000" stroke-width=".2"/>
<circle cx="55.1" cy="120.7" r=".72" fill="#fff"/>
<circle cx="55.1" cy="120.7" r=".72" fill="none" stroke="#000" stroke-width=".2"/>
<circle cx="93.3" cy="123.8" r="1.18" fill="#008000"/>
<circle cx="93.3" cy="123.8" r="1.18" fill="none" stroke="#008000" stroke-width=".2"/>
<circle cx="93.3" cy="123.8" r=".72" fill="#fff"/>
<circle cx="93.3" cy="123.8" r=".72" fill="none" stroke="#000" stroke-width=".2"/>
<circle cx="30" cy="72.2" r="1.18" fill="#008000"/>
<circle cx="30" cy="72.2" r="1.18" fill="none" stroke="#008000" stroke-width=".2"/>
<circle cx="30" cy="72.2" r=".72" fill="#fff"/>
<circle cx="30" cy="72.2" r=".72" fill="none" stroke="#000" stroke-width=".2"/>
<circle cx="19.2" cy="85.4" r="1.18" fill="#008000"/>
<circle cx="19.2" cy="85.4" r="1.18" fill="none" stroke="#008000" stroke-width=".2"/>
<circle cx="19.2" cy="85.4" r=".72" fill="#fff"/>
<circle cx="19.2" cy="85.4" r=".72" fill="none" stroke="#000" stroke-width=".2"/>
<circle cx="106" cy="152.7" r="1.18" fill="#008000"/>
<circle cx="106" cy="152.7" r="1.18" fill="none" stroke="#008000" stroke-width=".2"/>
<circle cx="106" cy="152.7" r=".72" fill="#fff"/>
<circle cx="106" cy="152.7" r=".72" fill="none" stroke="#000" stroke-width=".2"/>
<circle cx="51.5" cy="150.9" r="1.18" fill="#008000"/>
<circle cx="51.5" cy="150.9" r="1.18" fill="none" stroke="#008000" stroke-width=".2"/>
<circle cx="51.5" cy="150.9" r=".72" fill="#fff"/>
<circle cx="51.5" cy="150.9" r=".72" fill="none" stroke="#000" stroke-width=".2"/>
<circle cx="61" cy="73.3" r="1.18" fill="#008000"/>
<circle cx="61" cy="73.3" r="1.18" fill="none" stroke="#008000" stroke-width=".2"/>
<circle cx="61" cy="73.3" r=".72" fill="#fff"/>
<circle cx="61" cy="73.3" r=".72" fill="none" stroke="#000" stroke-width=".2"/>
<circle cx="61" cy="82.2" r="1.18" fill="#008000"/>
<circle cx="61" cy="82.2" r="1.18" fill="none" stroke="#008000" stroke-width=".2"/>
<circle cx="61" cy="82.2" r=".72" fill="#fff"/>
<circle cx="61" cy="82.2" r=".72" fill="none" stroke="#000" stroke-width=".2"/>
<circle cx="91.1" cy="125.7" r="1.18" fill="#008000"/>
<circle cx="91.1" cy="125.7" r="1.18" fill="none" stroke="#008000" stroke-width=".2"/>
<circle cx="91.1" cy="125.7" r=".72" fill="#fff"/>
<circle cx="91.1" cy="125.7" r=".72" fill="none" stroke="#000" stroke-width=".2"/>
<circle cx="61" cy="133.2" r="1.18" fill="#008000"/>
<circle cx="61" cy="133.2" r="1.18" fill="none" stroke="#008000" stroke-width=".2"/>
<circle cx="61" cy="133.2" r=".72" fill="#fff"/>
<circle cx="61" cy="133.2" r=".72" fill="none" stroke="#000" stroke-width=".2"/>
<circle cx="106" cy="125.1" r="1.18" fill="#008000"/>
<circle cx="106" cy="125.1" r="1.18" fill="none" stroke="#008000" stroke-width=".2"/>
<circle cx="106" cy="125.1" r=".72" fill="#fff"/>
<circle cx="106" cy="125.1" r=".72" fill="none" stroke="#000" stroke-width=".2"/>
<circle cx="112.2" cy="138.8" r="1.18" fill="#008000"/>
<circle cx="112.2" cy="138.8" r="1.18" fill="none" stroke="#008000" stroke-width=".2"/>
<circle cx="112.2" cy="138.8" r=".72" fill="#fff"/>
<circle cx="112.2" cy="138.8" r=".72" fill="none" stroke="#000" stroke-width=".2"/>
<circle cx="174.8" cy="91.6" r="1.18" fill="#008000"/>
<circle cx="174.8" cy="91.6" r="1.18" fill="none" stroke="#008000" stroke-width=".2"/>
<circle cx="174.8" cy="91.6" r=".72" fill="#fff"/>
<circle cx="174.8" cy="91.6" r=".72" fill="none" stroke="#000" stroke-width=".2"/>
<circle cx="172.3" cy="78.8" r="1.18" fill="#008000"/>
<circle cx="172.3" cy="78.8" r="1.18" fill="none" stroke="#008000" stroke-width=".2"/>
<circle cx="172.3" cy="78.8" r=".72" fill="#fff"/>
<circle cx="172.3" cy="78.8" r=".72" fill="none" stroke="#000" stroke-width=".2"/>
<circle cx="193.9" cy="125.6" r="1.18" fill="#008000"/>
<circle cx="193.9" cy="125.6" r="1.18" fill="none" stroke="#008000" stroke-width=".2"/>
<circle cx="193.9" cy="125.6" r=".72" fill="#fff"/>
<circle cx="193.9" cy="125.6" r=".72" fill="none" stroke="#000" stroke-width=".2"/>
<circle cx="199.9" cy="120.6" r="1.18" fill="#008000"/>
<circle cx="199.9" cy="120.6" r="1.18" fill="none" stroke="#008000" stroke-width=".2"/>
<circle cx="199.9" cy="120.6" r=".72" fill="#fff"/>
<circle cx="199.9" cy="120.6" r=".72" fill="none" stroke="#000" stroke-width=".2"/>
<circle cx="175.3" cy="129.2" r="1.18" fill="#008000"/>
<circle cx="175.3" cy="129.2" r="1.18" fill="none" stroke="#008000" stroke-width=".2"/>
<circle cx="175.3" cy="129.2" r=".72" fill="#fff"/>
<circle cx="175.3" cy="129.2" r=".72" fill="none" stroke="#000" stroke-width=".2"/>
<circle cx="187.6" cy="129.2" r="1.18" fill="#008000"/>
<circle cx="187.6" cy="129.2" r="1.18" fill="none" stroke="#008000" stroke-width=".2"/>
<circle cx="187.6" cy="129.2" r=".72" fill="#fff"/>
<circle cx="187.6" cy="129.2" r=".72" fill="none" stroke="#000" stroke-width=".2"/>
<circle cx="171.7" cy="95.8" r="1.18" fill="#008000"/>
<circle cx="171.7" cy="95.8" r="1.18" fill="none" stroke="#008000" stroke-width=".2"/>
<circle cx="171.7" cy="95.8" r=".72" fill="#fff"/>
<circle cx="171.7" cy="95.8" r=".72" fill="none" stroke="#000" stroke-width=".2"/>
<circle cx="178.9" cy="158.9" r="1.18" fill="#008000"/>
<circle cx="178.9" cy="158.9" r="1.18" fill="none" stroke="#008000" stroke-width=".2"/>
<circle cx="178.9" cy="158.9" r=".72" fill="#fff"/>
<circle cx="178.9" cy="158.9" r=".72" fill="none" stroke="#000" stroke-width=".2"/>
<circle cx="84.7" cy="60.7" r="1.18" fill="#008000"/>
<circle cx="84.7" cy="60.7" r="1.18" fill="none" stroke="#008000" stroke-width=".2"/>
<circle cx="84.7" cy="60.7" r=".72" fill="#fff"/>
<circle cx="84.7" cy="60.7" r=".72" fill="none" stroke="#000" stroke-width=".2"/>
<circle cx="100.2" cy="90.1" r="1.18" fill="#008000"/>
<circle cx="100.2" cy="90.1" r="1.18" fill="none" stroke="#008000" stroke-width=".2"/>
<circle cx="100.2" cy="90.1" r=".72" fill="#fff"/>
<circle cx="100.2" cy="90.1" r=".72" fill="none" stroke="#000" stroke-width=".2"/>
<circle cx="197.4" cy="51.1" r="1.18" fill="#008000"/>
<circle cx="197.4" cy="51.1" r="1.18" fill="none" stroke="#008000" stroke-width=".2"/>
<circle cx="197.4" cy="51.1" r=".72" fill="#fff"/>
<circle cx="197.4" cy="51.1" r=".72" fill="none" stroke="#000" stroke-width=".2"/>
<circle cx="175.6" cy="106" r="1.18" fill="#008000"/>
<circle cx="175.6" cy="106" r="1.18" fill="none" stroke="#008000" stroke-width=".2"/>
<circle cx="175.6" cy="106" r=".72" fill="#fff"/>
<circle cx="175.6" cy="106" r=".72" fill="none" stroke="#000" stroke-width=".2"/>
<circle cx="175.6" cy="114.2" r="1.18" fill="#008000"/>
<circle cx="175.6" cy="114.2" r="1.18" fill="none" stroke="#008000" stroke-width=".2"/>
<circle cx="175.6" cy="114.2" r=".72" fill="#fff"/>
<circle cx="175.6" cy="114.2" r=".72" fill="none" stroke="#000" stroke-width=".2"/>
<circle cx="25.2" cy="52.7" r="1.18" fill="#008000"/>
<circle cx="25.2" cy="52.7" r="1.18" fill="none" stroke="#008000" stroke-width=".2"/>
<circle cx="25.2" cy="52.7" r=".72" fill="#fff"/>
<circle cx="25.2" cy="52.7" r=".72" fill="none" stroke="#000" stroke-width=".2"/>
<circle cx="15.5" cy="77.6" r="1.18" fill="#008000"/>
<circle cx="15.5" cy="77.6" r="1.18" fill="none" stroke="#008000" stroke-width=".2"/>
<circle cx="15.5" cy="77.6" r=".72" fill="#fff"/>
<circle cx="15.5" cy="77.6" r=".72" fill="none" stroke="#000" stroke-width=".2"/>
<circle cx="166.9" cy="82.7" r="1.18" fill="#008000"/>
<circle cx="166.9" cy="82.7" r="1.18" fill="none" stroke="#008000" stroke-width=".2"/>
<circle cx="166.9" cy="82.7" r=".72" fill="#fff"/>
<circle cx="166.9" cy="82.7" r=".72" fill="none" stroke="#000" stroke-width=".2"/>
<circle cx="197.4" cy="69.4" r="1.18" fill="#008000"/>
<circle cx="197.4" cy="69.4" r="1.18" fill="none" stroke="#008000" stroke-width=".2"/>
<circle cx="197.4" cy="69.4" r=".72" fill="#fff"/>
<circle cx="197.4" cy="69.4" r=".72" fill="none" stroke="#000" stroke-width=".2"/>
<circle cx="194.1" cy="38.1" r="5" fill="#008000"/>
<circle cx="194.1" cy="38.1" r="5" fill="none" stroke="#008000" stroke-width=".2"/>
<circle cx="194.1" cy="38.1" r="3.8" fill="#fff"/>
<circle cx="194.1" cy="38.1" r="3.8" fill="none" stroke="#000" stroke-width=".2"/>
<circle cx="21.8" cy="38.1" r="5" fill="#008000"/>
<circle cx="21.8" cy="38.1" r="5" fill="none" stroke="#008000" stroke-width=".2"/>
<circle cx="21.8" cy="38.1" r="3.8" fill="#fff"/>
<circle cx="21.8" cy="38.1" r="3.8" fill="none" stroke="#000" stroke-width=".2"/>
<circle cx="12.8" cy="238.6" r="5" fill="#008000"/>
<circle cx="12.8" cy="238.6" r="5" fill="none" stroke="#008000" stroke-width=".2"/>
<circle cx="12.8" cy="238.6" r="3.8" fill="#fff"/>
<circle cx="12.8" cy="238.6" r="3.8" fill="none" stroke="#000" stroke-width=".2"/>
<circle cx="200" cy="238.6" r="5" fill="#008000"/>
<circle cx="200" cy="238.6" r="5" fill="none" stroke="#008000" stroke-width=".2"/>
<circle cx="200" cy="238.6" r="3.8" fill="#fff"/>
<circle cx="200" cy="238.6" r="3.8" fill="none" stroke="#000" stroke-width=".2"/>
<circle cx="26.3" cy="234.2" r="1.18" fill="#008000"/>
<circle cx="26.3" cy="234.2" r="1.18" fill="none" stroke="#008000" stroke-width=".2"/>
<circle cx="26.3" cy="234.2" r=".72" fill="#fff"/>
<circle cx="26.3" cy="234.2" r=".72" fill="none" stroke="#000" stroke-width=".2"/>
<circle cx="42.6" cy="238.9" r="1.18" fill="#008000"/>
<circle cx="42.6" cy="238.9" r="1.18" fill="none" stroke="#008000" stroke-width=".2"/>
<circle cx="42.6" cy="238.9" r=".72" fill="#fff"/>
<circle cx="42.6" cy="238.9" r=".72" fill="none" stroke="#000" stroke-width=".2"/>
<circle cx="59" cy="234.2" r="1.18" fill="#008000"/>
<circle cx="59" cy="234.2" r="1.18" fill="none" stroke="#008000" stroke-width=".2"/>
<circle cx="59" cy="234.2" r=".72" fill="#fff"/>
<circle cx="59" cy="234.2" r=".72" fill="none" stroke="#000" stroke-width=".2"/>
<circle cx="75.4" cy="238.9" r="1.18" fill="#008000"/>
<circle cx="75.4" cy="238.9" r="1.18" fill="none" stroke="#008000" stroke-width=".2"/>
<circle cx="75.4" cy="238.9" r=".72" fill="#fff"/>
<circle cx="75.4" cy="238.9" r=".72" fill="none" stroke="#000" stroke-width=".2"/>
<circle cx="91.8" cy="234.2" r="1.18" fill="#008000"/>
<circle cx="91.8" cy="234.2" r="1.18" fill="none" stroke="#008000" stroke-width=".2"/>
<circle cx="91.8" cy="234.2" r=".72" fill="#fff"/>
<circle cx="91.8" cy="234.2" r=".72" fill="none" stroke="#000" stroke-width=".2"/>
<circle cx="108.1" cy="238.9" r="1.18" fill="#008000"/>
<circle cx="108.1" cy="238.9" r="1.18" fill="none" stroke="#008000" stroke-width=".2"/>
<circle cx="108.1" cy="238.9" r=".72" fill="#fff"/>
<circle cx="108.1" cy="238.9" r=".72" fill="none" stroke="#000" stroke-width=".2"/>
<circle cx="124.5" cy="234.2" r="1.18" fill="#008000"/>
<circle cx="124.5" cy="234.2" r="1.18" fill="none" stroke="#008000" stroke-width=".2"/>
<circle cx="124.5" cy="234.2" r=".72" fill="#fff"/>
<circle cx="124.5" cy="234.2" r=".72" fill="none" stroke="#000" stroke-width=".2"/>
<circle cx="140.9" cy="238.9" r="1.18" fill="#008000"/>
<circle cx="140.9" cy="238.9" r="1.18" fill="none" stroke="#008000" stroke-width=".2"/>
<circle cx="140.9" cy="238.9" r=".72" fill="#fff"/>
<circle cx="140.9" cy="238.9" r=".72" fill="none" stroke="#000" stroke-width=".2"/>
<circle cx="157.3" cy="234.2" r="1.18" fill="#008000"/>
<circle cx="157.3" cy="234.2" r="1.18" fill="none" stroke="#008000" stroke-width=".2"/>
<circle cx="157.3" cy="234.2" r=".72" fill="#fff"/>
<circle cx="157.3" cy="234.2" r=".72" fill="none" stroke="#000" stroke-width=".2"/>
<circle cx="61.3" cy="215.6" r="1.18" fill="#008000"/>
<circle cx="61.3" cy="215.6" r="1.18" fill="none" stroke="#008000" stroke-width=".2"/>
<circle cx="61.3" cy="215.6" r=".72" fill="#fff"/>
<circle cx="61.3" cy="215.6" r=".72" fill="none" stroke="#000" stroke-width=".2"/>
<circle cx="59.9" cy="212.6" r="1.18" fill="#008000"/>
<circle cx="59.9" cy="212.6" r="1.18" fill="none" stroke="#008000" stroke-width=".2"/>
<circle cx="59.9" cy="212.6" r=".72" fill="#fff"/>
<circle cx="59.9" cy="212.6" r=".72" fill="none" stroke="#000" stroke-width=".2"/>
<circle cx="98.5" cy="213.1" r="1.18" fill="#008000"/>
<circle cx="98.5" cy="213.1" r="1.18" fill="none" stroke="#008000" stroke-width=".2"/>
<circle cx="98.5" cy="213.1" r=".72" fill="#fff"/>
<circle cx="98.5" cy="213.1" r=".72" fill="none" stroke="#000" stroke-width=".2"/>
<circle cx="99.9" cy="216.1" r="1.18" fill="#008000"/>
<circle cx="99.9" cy="216.1" r="1.18" fill="none" stroke="#008000" stroke-width=".2"/>
<circle cx="99.9" cy="216.1" r=".72" fill="#fff"/>
<circle cx="99.9" cy="216.1" r=".72" fill="none" stroke="#000" stroke-width=".2"/>
<circle cx="79.3" cy="169.7" r="1.18" fill="#008000"/>
<circle cx="79.3" cy="169.7" r="1.18" fill="none" stroke="#008000" stroke-width=".2"/>
<circle cx="79.3" cy="169.7" r=".72" fill="#fff"/>
<circle cx="79.3" cy="169.7" r=".72" fill="none" stroke="#000" stroke-width=".2"/>
<circle cx="112.6" cy="168.4" r="1.18" fill="#008000"/>
<circle cx="112.6" cy="168.4" r="1.18" fill="none" stroke="#008000" stroke-width=".2"/>
<circle cx="112.6" cy="168.4" r=".72" fill="#fff"/>
<circle cx="112.6" cy="168.4" r=".72" fill="none" stroke="#000" stroke-width=".2"/>
<circle cx="101.2" cy="165.7" r="1.18" fill="#008000"/>
<circle cx="101.2" cy="165.7" r="1.18" fill="none" stroke="#008000" stroke-width=".2"/>
<circle cx="101.2" cy="165.7" r=".72" fill="#fff"/>
<circle cx="101.2" cy="165.7" r=".72" fill="none" stroke="#000" stroke-width=".2"/>
<circle cx="89.6" cy="168.1" r="1.18" fill="#008000"/>
<circle cx="89.6" cy="168.1" r="1.18" fill="none" stroke="#008000" stroke-width=".2"/>
<circle cx="89.6" cy="168.1" r=".72" fill="#fff"/>
<circle cx="89.6" cy="168.1" r=".72" fill="none" stroke="#000" stroke-width=".2"/>
<circle cx="68" cy="167.2" r="1.18" fill="#008000"/>
<circle cx="68" cy="167.2" r="1.18" fill="none" stroke="#008000" stroke-width=".2"/>
<circle cx="68" cy="167.2" r=".72" fill="#fff"/>
<circle cx="68" cy="167.2" r=".72" fill="none" stroke="#000" stroke-width=".2"/>
<circle cx="58.8" cy="168.8" r="1.18" fill="#008000"/>
<circle cx="58.8" cy="168.8" r="1.18" fill="none" stroke="#008000" stroke-width=".2"/>
<circle cx="58.8" cy="168.8" r=".72" fill="#fff"/>
<circle cx="58.8" cy="168.8" r=".72" fill="none" stroke="#000" stroke-width=".2"/>
<circle cx="64" cy="89.3" r="1.18" fill="#008000"/>
<circle cx="64" cy="89.3" r="1.18" fill="none" stroke="#008000" stroke-width=".2"/>
<circle cx="64" cy="89.3" r=".72" fill="#fff"/>
<circle cx="64" cy="89.3" r=".72" fill="none" stroke="#000" stroke-width=".2"/>
<circle cx="129" cy="73.8" r="1.18" fill="#008000"/>
<circle cx="129" cy="73.8" r="1.18" fill="none" stroke="#008000" stroke-width=".2"/>
<circle cx="129" cy="73.8" r=".72" fill="#fff"/>
<circle cx="129" cy="73.8" r=".72" fill="none" stroke="#000" stroke-width=".2"/>
<circle cx="146" cy="76.7" r="1.18" fill="#008000"/>
<circle cx="146" cy="76.7" r="1.18" fill="none" stroke="#008000" stroke-width=".2"/>
<circle cx="146" cy="76.7" r=".72" fill="#fff"/>
<circle cx="146" cy="76.7" r=".72" fill="none" stroke="#000" stroke-width=".2"/>
<circle cx="101.4" cy="73.8" r="1.18" fill="#008000"/>
<circle cx="101.4" cy="73.8" r="1.18" fill="none" stroke="#008000" stroke-width=".2"/>
<circle cx="101.4" cy="73.8" r=".72" fill="#fff"/>
<circle cx="101.4" cy="73.8" r=".72" fill="none" stroke="#000" stroke-width=".2"/>
<circle cx="122.8" cy="112.7" r="1.18" fill="#008000"/>
<circle cx="122.8" cy="112.7" r="1.18" fill="none" stroke="#008000" stroke-width=".2"/>
<circle cx="122.8" cy="112.7" r=".72" fill="#fff"/>
<circle cx="122.8" cy="112.7" r=".72" fill="none" stroke="#000" stroke-width=".2"/>
<circle cx="141.8" cy="97.5" r="1.18" fill="#008000"/>
<circle cx="141.8" cy="97.5" r="1.18" fill="none" stroke="#008000" stroke-width=".2"/>
<circle cx="141.8" cy="97.5" r=".72" fill="#fff"/>
<circle cx="141.8" cy="97.5" r=".72" fill="none" stroke="#000" stroke-width=".2"/>
<circle cx="66.4" cy="157.1" r="1.18" fill="#008000"/>
<circle cx="66.4" cy="157.1" r="1.18" fill="none" stroke="#008000" stroke-width=".2"/>
<circle cx="66.4" cy="157.1" r=".72" fill="#fff"/>
<circle cx="66.4" cy="157.1" r=".72" fill="none" stroke="#000" stroke-width=".2"/>
<circle cx="49.6" cy="156.4" r="1.18" fill="#008000"/>
<circle cx="49.6" cy="156.4" r="1.18" fill="none" stroke="#008000" stroke-width=".2"/>
<circle cx="49.6" cy="156.4" r=".72" fill="#fff"/>
<circle cx="49.6" cy="156.4" r=".72" fill="none" stroke="#000" stroke-width=".2"/>
<circle cx="126.5" cy="68.6" r="1.18" fill="#008000"/>
<circle cx="126.5" cy="68.6" r="1.18" fill="none" stroke="#008000" stroke-width=".2"/>
<circle cx="126.5" cy="68.6" r=".72" fill="#fff"/>
<circle cx="126.5" cy="68.6" r=".72" fill="none" stroke="#000" stroke-width=".2"/>
<circle cx="132.8" cy="213.1" r="1.18" fill="#008000"/>
<circle cx="132.8" cy="213.1" r="1.18" fill="none" stroke="#008000" stroke-width=".2"/>
<circle cx="132.8" cy="213.1" r=".72" fill="#fff"/>
<circle cx="132.8" cy="213.1" r=".72" fill="none" stroke="#000" stroke-width=".2"/>
<circle cx="50.5" cy="224.7" r="1.18" fill="#008000"/>
<circle cx="50.5" cy="224.7" r="1.18" fill="none" stroke="#008000" stroke-width=".2"/>
<circle cx="50.5" cy="224.7" r=".72" fill="#fff"/>
<circle cx="50.5" cy="224.7" r=".72" fill="none" stroke="#000" stroke-width=".2"/>
<path d="M95.7 211.1h7v7h-7z" fill="none" stroke="#808080" stroke-width=".34"/>
<path d="M96.1 211.4h.4v.4h-.4z" fill-rule="evenodd" fill="#808080"/>
<path d="M96.1 211.4h.4v.4h-.4z" fill="none" stroke="#808080" stroke-width=".2"/>
<path d="M57.1 210.6h7v7h-7z" fill="none" stroke="#808080" stroke-width=".34"/>
<path d="M57.5 210.8h.4v.4h-.4z" fill-rule="evenodd" fill="#808080"/>
<path d="M57.5 210.8h.4v.4h-.4z" fill="none" stroke="#808080" stroke-width=".2"/>
<path d="M186.9 120.9l.2-.1 .2 .1 .2 .3-.2 .2h-.4l-.1-.2h.4h-.4z" fill-rule="evenodd" fill="#808080"/>
<path d="M186.9 120.9l.2-.1 .2 .1 .2 .3-.2 .2h-.4l-.1-.2h.4h-.4z" fill="none" stroke="#808080" stroke-width=".2"/>
<path d="M186.1 194.1h.5v.5h-.5l-.1-.2h.4h-.4z" fill-rule="evenodd" fill="#808080"/>
<path d="M186.1 194.1h.5v.5h-.5l-.1-.2h.4h-.4z" fill="none" stroke="#808080" stroke-width=".2"/>
<path d="M25.4 58.3l.3-.1 .2 .1 .1 .2-.1 .3h-.5l-.1-.3h.4h-.4z" fill-rule="evenodd" fill="#808080"/>
<path d="M25.4 58.3l.3-.1 .2 .1 .1 .2-.1 .3h-.5l-.1-.3h.4h-.4z" fill="none" stroke="#808080" stroke-width=".2"/>
<path d="M126.9 198.6h.5v.5h-.5l-.1-.3h.4h-.4z" fill-rule="evenodd" fill="#808080"/>
<path d="M126.9 198.6h.5v.5h-.5l-.1-.3h.4h-.4z" fill="none" stroke="#808080" stroke-width=".2"/>
<path d="M176.3 97.9h8.9v5.6h-8.9zM178 98.2v5.1M144 105.5h29.2v29.2h-29.2zM191.3 129.8h6.7v4.1h-6.7zM141.9 144h8.9v5.6h-8.9zM149.2 144.3v5.1M144.1 178.9h29.3v29.3h-29.3zM176.1 170.6h8.9v5.5h-8.9zM177.7 170.8v5.1M140.9 218.5h8.9v5.7h-8.9zM148.2 218.8v5.1" fill="none" stroke="#808080" stroke-width=".34"/>
<path d="M192 132.4l.2-.2 .6 .2v.6l-.3 .2h-.3l-.3-.5h.3l.1-.2 .3 .2-.2 .2-.5-.2z" fill-rule="evenodd" fill="#808080"/>
<path d="M192 132.4l.2-.2 .6 .2v.6l-.3 .2h-.3l-.3-.5h.3l.1-.2 .3 .2-.2 .2-.5-.2z" fill="none" stroke="#808080" stroke-width=".2"/>
<path d="M191.1 203.2h6.7v4h-6.7z" fill="none" stroke="#808080" stroke-width=".34"/>
<path d="M191.8 205.8l.2-.2 .6 .2 .1 .3-.1 .3-.3 .2h-.3l-.3-.5h.3l.1-.2 .3 .2-.3 .2-.1-.2h-.3z" fill-rule="evenodd" fill="#808080"/>
<path d="M96.4 82.7v11.9M191.8 205.8l.2-.2 .6 .2 .1 .3-.1 .3-.3 .2h-.3l-.3-.5h.3l.1-.2 .3 .2-.3 .2-.1-.2h-.3z" fill="none" stroke="#808080" stroke-width=".2"/>
<path d="M95.9 82.9l.6-.2h7.4a.87 .87 0 0 1 .9 .9v10.1a.87 .87 0 0 1-.9 .9h-7.4a.87 .87 0 0 1-.9-.9v-10.1zM99 82.7a1.19 1.19 0 0 0 1.2 1.2 1.19 1.19 0 0 0 1.2-1.2" fill="none" stroke="#808080" stroke-width=".38"/>
<path d="M22.6 96.5l.3-.1 .2 .1 .1 .2-.1 .2h-.5l-.1-.2h.4h-.4z" fill-rule="evenodd" fill="#808080"/>
<path d="M22.6 96.5l.3-.1 .2 .1 .1 .2-.1 .2h-.5l-.1-.2h.4h-.4z" fill="none" stroke="#808080" stroke-width=".2"/>
<path d="M92.6 68.5v-.2h3.8v.2M92.6 74.7v.2h3.8v-.2M92.6 70.4v2.4M96.4 70.4v.2M96.4 72.6v.2" fill="none" stroke="#808080" stroke-width=".38"/>
<path d="M38.9 96.5l.3-.1 .2 .1v.4h-.5l-.1-.2 .4-.1-.4 .1z" fill-rule="evenodd" fill="#808080"/>
<path d="M38.9 96.5l.3-.1 .2 .1v.4h-.5l-.1-.2 .4-.1-.4 .1z" fill="none" stroke="#808080" stroke-width=".2"/>
<path d="M104 120.4h10.3v15.2h-10.3z" fill="none" stroke="#808080" stroke-width=".34"/>
<path d="M112.7 134.3l.6-.2 .3 .5-.1 .3-.2 .1-.6-.1-.1-.3 .7-.1v.2h-.2l-.2-.1h-.3z" fill-rule="evenodd" fill="#808080"/>
<path d="M112.7 134.3l.6-.2 .3 .5-.1 .3-.2 .1-.6-.1-.1-.3 .7-.1v.2h-.2l-.2-.1h-.3z" fill="none" stroke="#808080" stroke-width=".2"/>
<path d="M157.2 84.3h7v7.1h-7z" fill="none" stroke="#808080" stroke-width=".34"/>
<path d="M162.3 89.3a.81 .81 0 0 1 1.2 .4 .81 .81 0 0 1-.6 1.1 .81 .81 0 0 1-.9-.9h.3a.51 .51 0 0 1 .6-.5 .51 .51 0 0 1 .3 .8 .51 .51 0 0 1-.9 0v-.3h-.3z" fill-rule="evenodd" fill="#808080"/>
<path d="M162.3 89.3a.81 .81 0 0 1 1.2 .4 .81 .81 0 0 1-.6 1.1 .81 .81 0 0 1-.9-.9h.3a.51 .51 0 0 1 .6-.5 .51 .51 0 0 1 .3 .8 .51 .51 0 0 1-.9 0v-.3h-.3z" fill="none" stroke="#808080" stroke-width=".2"/>
<path d="M164.5 69.3h-.2v3.8h.2M166.3 73.1h2.5M166.3 69.3h.3M168.6 69.3h.2M170.7 69.3h.2v3.8h-.2" fill="none" stroke="#808080" stroke-width=".38"/>
<path d="M141.7 166.5l.3-.1 .2 .1v.5h-.5l-.1-.2h.4h-.4z" fill-rule="evenodd" fill="#808080"/>
<path d="M141.7 166.5l.3-.1 .2 .1v.5h-.5l-.1-.2h.4h-.4z" fill="none" stroke="#808080" stroke-width=".2"/>
<g fill="none" stroke="#808080" stroke-width=".38">
<path d="M115 111.1v-.2h3.7v.2M115 117.3v.2h3.7v-.2M115 113v2.4M118.7 113v.2M118.7 115.2v.2M193.9 144.7v5.4M197.8 144.7v5.4M67.6 172.9h-.2v3.8h.2M69.5 176.7h2.5M69.5 172.9h.2M71.8 172.9h.2M73.8 172.9h.3v3.8h-.3"/>
<path d="M101.6 171.5h-.2v3.8h.2M103.5 175.3h2.4M103.5 171.5h.2M105.7 171.5h.2M107.8 171.5h.2v3.8h-.2"/>
</g>
<path d="M193.7 150h4.3v1.4h-4.3z" fill-rule="evenodd" fill="#808080"/>
<path d="M193.7 150h4.3v1.4h-4.3z" fill="none" stroke="#808080" stroke-width=".2"/>
<path d="M193.7 143.4h4.3v1.4h-4.3z" fill-rule="evenodd" fill="#808080"/>
<path d="M193.7 143.4h4.3v1.4h-4.3z" fill="none" stroke="#808080" stroke-width=".2"/>
<path d="M182.9 140.8v5.4M186.8 140.8v5.4" fill="none" stroke="#808080" stroke-width=".38"/>
<path d="M182.7 146.1h4.3v1.3h-4.3z" fill-rule="evenodd" fill="#808080"/>
<path d="M182.7 146.1h4.3v1.3h-4.3z" fill="none" stroke="#808080" stroke-width=".2"/>
<path d="M182.7 139.5h4.3v1.4h-4.3z" fill-rule="evenodd" fill="#808080"/>
<path d="M182.7 139.5h4.3v1.4h-4.3z" fill="none" stroke="#808080" stroke-width=".2"/>
<path d="M193.8 220.6v5.3M197.7 220.6v5.3" fill="none" stroke="#808080" stroke-width=".38"/>
<path d="M193.6 225.8h4.4v1.4h-4.4z" fill-rule="evenodd" fill="#808080"/>
<path d="M193.6 225.8h4.4v1.4h-4.4z" fill="none" stroke="#808080" stroke-width=".2"/>
<path d="M193.6 219.2h4.4v1.4h-4.4z" fill-rule="evenodd" fill="#808080"/>
<path d="M193.6 219.2h4.4v1.4h-4.4z" fill="none" stroke="#808080" stroke-width=".2"/>
<path d="M181.6 216v5.4M185.5 216v5.4" fill="none" stroke="#808080" stroke-width=".38"/>
<path d="M181.4 221.3h4.4v1.4h-4.4z" fill-rule="evenodd" fill="#808080"/>
<path d="M181.4 221.3h4.4v1.4h-4.4z" fill="none" stroke="#808080" stroke-width=".2"/>
<path d="M181.4 214.7h4.4v1.4h-4.4z" fill-rule="evenodd" fill="#808080"/>
<path d="M181.4 214.7h4.4v1.4h-4.4z" fill="none" stroke="#808080" stroke-width=".2"/>
<path d="M178.7 210.1h5.4M178.7 206.2h5.4" fill="none" stroke="#808080" stroke-width=".38"/>
<path d="M184 206h1.4v4.3h-1.4z" fill-rule="evenodd" fill="#808080"/>
<path d="M184 206h1.4v4.3h-1.4z" fill="none" stroke="#808080" stroke-width=".2"/>
<path d="M177.4 206h1.4v4.3h-1.4z" fill-rule="evenodd" fill="#808080"/>
<path d="M177.4 206h1.4v4.3h-1.4z" fill="none" stroke="#808080" stroke-width=".2"/>
<path d="M178.9 135.8h5.3M178.9 132h5.3" fill="none" stroke="#808080" stroke-width=".38"/>
<path d="M184.1 131.7h1.4v4.4h-1.4z" fill-rule="evenodd" fill="#808080"/>
<path d="M184.1 131.7h1.4v4.4h-1.4z" fill="none" stroke="#808080" stroke-width=".2"/>
<path d="M177.5 131.7h1.4v4.4h-1.4z" fill-rule="evenodd" fill="#808080"/>
<path d="M177.5 131.7h1.4v4.4h-1.4z" fill="none" stroke="#808080" stroke-width=".2"/>
<path d="M110.5 203.7v5.3M114.4 203.7v5.3" fill="none" stroke="#808080" stroke-width=".38"/>
<path d="M110.3 202.4h4.3v1.4h-4.3z" fill-rule="evenodd" fill="#808080"/>
<path d="M110.3 202.4h4.3v1.4h-4.3z" fill="none" stroke="#808080" stroke-width=".2"/>
<path d="M110.3 209h4.3v1.4h-4.3z" fill-rule="evenodd" fill="#808080"/>
<path d="M110.3 209h4.3v1.4h-4.3z" fill="none" stroke="#808080" stroke-width=".2"/>
<path d="M98 196.5v5.3M101.9 196.5v5.3" fill="none" stroke="#808080" stroke-width=".38"/>
<path d="M97.8 195.2h4.4v1.4h-4.4z" fill-rule="evenodd" fill="#808080"/>
<path d="M97.8 195.2h4.4v1.4h-4.4z" fill="none" stroke="#808080" stroke-width=".2"/>
<path d="M97.8 201.8h4.4v1.4h-4.4z" fill-rule="evenodd" fill="#808080"/>
<path d="M97.8 201.8h4.4v1.4h-4.4z" fill="none" stroke="#808080" stroke-width=".2"/>
<path d="M84 212.7v5.3M87.9 212.7v5.3" fill="none" stroke="#808080" stroke-width=".38"/>
<path d="M83.8 211.4h4.3v1.3h-4.3z" fill-rule="evenodd" fill="#808080"/>
<path d="M83.8 211.4h4.3v1.3h-4.3z" fill="none" stroke="#808080" stroke-width=".2"/>
<path d="M83.8 218h4.3v1.3h-4.3z" fill-rule="evenodd" fill="#808080"/>
<path d="M83.8 218h4.3v1.3h-4.3z" fill="none" stroke="#808080" stroke-width=".2"/>
<path d="M83.9 196.5v5.3M87.9 196.5v5.3" fill="none" stroke="#808080" stroke-width=".38"/>
<path d="M83.7 195.2h4.4v1.3h-4.4z" fill-rule="evenodd" fill="#808080"/>
<path d="M83.7 195.2h4.4v1.3h-4.4z" fill="none" stroke="#808080" stroke-width=".2"/>
<path d="M83.7 201.8h4.4v1.3h-4.4z" fill-rule="evenodd" fill="#808080"/>
<path d="M83.7 201.8h4.4v1.3h-4.4z" fill="none" stroke="#808080" stroke-width=".2"/>
<path d="M71.9 204v5.3M75.8 204v5.3" fill="none" stroke="#808080" stroke-width=".38"/>
<path d="M71.7 202.7h4.3v1.3h-4.3z" fill-rule="evenodd" fill="#808080"/>
<path d="M71.7 202.7h4.3v1.3h-4.3z" fill="none" stroke="#808080" stroke-width=".2"/>
<path d="M71.7 209.3h4.3v1.4h-4.3z" fill-rule="evenodd" fill="#808080"/>
<path d="M71.7 209.3h4.3v1.4h-4.3z" fill="none" stroke="#808080" stroke-width=".2"/>
<path d="M59.1 196.8v5.3M63 196.8v5.3" fill="none" stroke="#808080" stroke-width=".38"/>
<path d="M58.9 195.5h4.3v1.4h-4.3z" fill-rule="evenodd" fill="#808080"/>
<path d="M58.9 195.5h4.3v1.4h-4.3z" fill="none" stroke="#808080" stroke-width=".2"/>
<path d="M58.9 202.1h4.3v1.3h-4.3z" fill-rule="evenodd" fill="#808080"/>
<path d="M58.9 202.1h4.3v1.3h-4.3z" fill="none" stroke="#808080" stroke-width=".2"/>
<path d="M45.2 212.5v5.3M49.1 212.5v5.3" fill="none" stroke="#808080" stroke-width=".38"/>
<path d="M45 211.2h4.3v1.3h-4.3z" fill-rule="evenodd" fill="#808080"/>
<path d="M45 211.2h4.3v1.3h-4.3z" fill="none" stroke="#808080" stroke-width=".2"/>
<path d="M45 217.8h4.3v1.3h-4.3z" fill-rule="evenodd" fill="#808080"/>
<path d="M45 217.8h4.3v1.3h-4.3z" fill="none" stroke="#808080" stroke-width=".2"/>
<path d="M45.2 196.8v5.3M49.1 196.8v5.3" fill="none" stroke="#808080" stroke-width=".38"/>
<path d="M45 195.5h4.3v1.3h-4.3z" fill-rule="evenodd" fill="#808080"/>
<path d="M45 195.5h4.3v1.3h-4.3z" fill="none" stroke="#808080" stroke-width=".2"/>
<path d="M45 202.1h4.3v1.3h-4.3z" fill-rule="evenodd" fill="#808080"/>
<path d="M45 202.1h4.3v1.3h-4.3z" fill="none" stroke="#808080" stroke-width=".2"/>
<path d="M6.7 58.6v5.3M10.6 58.6v5.3" fill="none" stroke="#808080" stroke-width=".38"/>
<path d="M6.5 57.3h4.3v1.3h-4.3z" fill-rule="evenodd" fill="#808080"/>
<path d="M6.5 57.3h4.3v1.3h-4.3z" fill="none" stroke="#808080" stroke-width=".2"/>
<path d="M6.5 63.9h4.3v1.3h-4.3z" fill-rule="evenodd" fill="#808080"/>
<path d="M6.5 63.9h4.3v1.3h-4.3z" fill="none" stroke="#808080" stroke-width=".2"/>
<path d="M204.9 150h1.7M204.9 153.1h1.7" fill="none" stroke="#808080" stroke-width=".25"/>
<path d="M203.2 149.9h1.7v3.3h-1.7z" fill-rule="evenodd" fill="#808080"/>
<path d="M203.2 149.9h1.7v3.3h-1.7z" fill="none" stroke="#808080" stroke-width=".2"/>
<path d="M206.5 149.9h1.8v3.3h-1.8z" fill-rule="evenodd" fill="#808080"/>
<path d="M206.5 149.9h1.8v3.3h-1.8z" fill="none" stroke="#808080" stroke-width=".2"/>
<path d="M204.8 142.5h1.7M204.9 145.5h1.6" fill="none" stroke="#808080" stroke-width=".25"/>
<path d="M203.1 142.3h1.8v3.4h-1.8z" fill-rule="evenodd" fill="#808080"/>
<path d="M203.1 142.3h1.8v3.4h-1.8z" fill="none" stroke="#808080" stroke-width=".2"/>
<path d="M206.5 142.3h1.8v3.4h-1.8z" fill-rule="evenodd" fill="#808080"/>
<path d="M206.5 142.3h1.8v3.4h-1.8z" fill="none" stroke="#808080" stroke-width=".2"/>
<path d="M204.8 119h1.8M204.9 122.1h1.7" fill="none" stroke="#808080" stroke-width=".25"/>
<path d="M203.2 118.9h1.7v3.4h-1.7z" fill-rule="evenodd" fill="#808080"/>
<path d="M203.2 118.9h1.7v3.4h-1.7z" fill="none" stroke="#808080" stroke-width=".2"/>
<path d="M206.5 118.9h1.8v3.4h-1.8z" fill-rule="evenodd" fill="#808080"/>
<path d="M191.6 96.2h.4v5.6h-.4zM208.4 96.2h.3v5.6h-.3zM206.5 118.9h1.8v3.4h-1.8z" fill="none" stroke="#808080" stroke-width=".2"/>
<path d="M192.1 94.1h16.1v9.8h-16.1z" fill="none" stroke="#808080" stroke-width=".25"/>
<path d="M191.8 96.2v5.6M208.5 96.2v5.6" fill="none" stroke="#808080" stroke-width=".34"/>
<path d="M192.8 94h1.1v9.9h-1.1z" fill-rule="evenodd" fill="#808080"/>
<path d="M192.8 94h1.1v9.9h-1.1z" fill="none" stroke="#808080" stroke-width=".2"/>
<path d="M186.4 108.2h11.5v13.8h-11.5zM185.6 181.4h11.5v13.8h-11.5z" fill="none" stroke="#808080" stroke-width=".34"/>
<path d="M204.8 226.6h1.8M204.9 229.7h1.7" fill="none" stroke="#808080" stroke-width=".25"/>
<path d="M203.1 226.4h1.8v3.4h-1.8z" fill-rule="evenodd" fill="#808080"/>
<path d="M203.1 226.4h1.8v3.4h-1.8z" fill="none" stroke="#808080" stroke-width=".2"/>
<path d="M206.5 226.4h1.8v3.4h-1.8z" fill-rule="evenodd" fill="#808080"/>
<path d="M206.5 226.4h1.8v3.4h-1.8z" fill="none" stroke="#808080" stroke-width=".2"/>
<path d="M204.9 216.2h1.7M204.9 219.2h1.7" fill="none" stroke="#808080" stroke-width=".25"/>
<path d="M203.2 216h1.7v3.4h-1.7z" fill-rule="evenodd" fill="#808080"/>
<path d="M203.2 216h1.7v3.4h-1.7z" fill="none" stroke="#808080" stroke-width=".2"/>
<path d="M206.5 216h1.8v3.4h-1.8z" fill-rule="evenodd" fill="#808080"/>
<path d="M206.5 216h1.8v3.4h-1.8z" fill="none" stroke="#808080" stroke-width=".2"/>
<path d="M204.9 191.4h1.8M204.9 194.5h1.8" fill="none" stroke="#808080" stroke-width=".25"/>
<path d="M203.2 191.2h1.8v3.4h-1.8z" fill-rule="evenodd" fill="#808080"/>
<path d="M203.2 191.2h1.8v3.4h-1.8z" fill="none" stroke="#808080" stroke-width=".2"/>
<path d="M206.6 191.2h1.8v3.4h-1.8z" fill-rule="evenodd" fill="#808080"/>
<path d="M191.7 167.9h.4v5.6h-.4zM208.4 167.9h.4v5.6h-.4zM206.6 191.2h1.8v3.4h-1.8z" fill="none" stroke="#808080" stroke-width=".2"/>
<path d="M192.2 165.8h16.1v9.8h-16.1z" fill="none" stroke="#808080" stroke-width=".25"/>
<path d="M191.9 167.9v5.6M208.6 167.9v5.6" fill="none" stroke="#808080" stroke-width=".34"/>
<path d="M192.9 165.8h1.1v9.9h-1.1z" fill-rule="evenodd" fill="#808080"/>
<path d="M192.9 165.8h1.1v9.9h-1.1z" fill="none" stroke="#808080" stroke-width=".2"/>
<path d="M14.9 57.7h11.4v13.8h-11.4zM126.4 198.2h13.7v11.4h-13.7z" fill="none" stroke="#808080" stroke-width=".34"/>
<path d="M126.6 213.7v5.3M130.6 213.7v5.3" fill="none" stroke="#808080" stroke-width=".38"/>
<path d="M126.4 212.4h4.4v1.3h-4.4z" fill-rule="evenodd" fill="#808080"/>
<path d="M126.4 212.4h4.4v1.3h-4.4z" fill="none" stroke="#808080" stroke-width=".2"/>
<path d="M126.4 219h4.4v1.3h-4.4z" fill-rule="evenodd" fill="#808080"/>
<path d="M126.4 219h4.4v1.3h-4.4z" fill="none" stroke="#808080" stroke-width=".2"/>
<path d="M204.9 203.5h1.8M204.9 206.6h1.8" fill="none" stroke="#808080" stroke-width=".25"/>
<path d="M203.2 203.4h1.8v3.4h-1.8z" fill-rule="evenodd" fill="#808080"/>
<path d="M203.2 203.4h1.8v3.4h-1.8z" fill="none" stroke="#808080" stroke-width=".2"/>
<path d="M206.6 203.4h1.8v3.4h-1.8z" fill-rule="evenodd" fill="#808080"/>
<path d="M206.6 203.4h1.8v3.4h-1.8z" fill="none" stroke="#808080" stroke-width=".2"/>
<path d="M204.8 129.9h1.7M204.9 133h1.6" fill="none" stroke="#808080" stroke-width=".25"/>
<path d="M203.1 129.8h1.8v3.3h-1.8z" fill-rule="evenodd" fill="#808080"/>
<path d="M203.1 129.8h1.8v3.3h-1.8z" fill="none" stroke="#808080" stroke-width=".2"/>
<path d="M206.5 129.8h1.8v3.3h-1.8z" fill-rule="evenodd" fill="#808080"/>
<path d="M206.5 129.8h1.8v3.3h-1.8zM157.6 144h.3v5.6h-.3zM174.3 144h.3v5.6h-.3z" fill="none" stroke="#808080" stroke-width=".2"/>
<path d="M158 141.9h16.2v9.8h-16.2z" fill="none" stroke="#808080" stroke-width=".25"/>
<path d="M157.7 144v5.6M174.5 144v5.6" fill="none" stroke="#808080" stroke-width=".34"/>
<path d="M158.7 141.9h1.1v9.9h-1.1z" fill-rule="evenodd" fill="#808080"/>
<path d="M158.7 141.9h1.1v9.9h-1.1zM157.6 218.6h.3v5.6h-.3zM174.3 218.6h.4v5.6h-.4z" fill="none" stroke="#808080" stroke-width=".2"/>
<path d="M158.1 216.5h16.1v9.8h-16.1z" fill="none" stroke="#808080" stroke-width=".25"/>
<path d="M157.8 218.6v5.6M174.5 218.6v5.6" fill="none" stroke="#808080" stroke-width=".34"/>
<path d="M158.8 216.4h1.1v9.9h-1.1z" fill-rule="evenodd" fill="#808080"/>
<path d="M158.8 216.4h1.1v9.9h-1.1z" fill="none" stroke="#808080" stroke-width=".2"/>
<path d="M104.7 92.5h2.7v1.2h-2.7z" fill-rule="evenodd" fill="#808080"/>
<path d="M104.7 92.5h2.7v1.2h-2.7z" fill="none" stroke="#808080" stroke-width=".2"/>
<path d="M92.9 83.6h2.7v1.2h-2.7z" fill-rule="evenodd" fill="#808080"/>
<path d="M92.9 83.6h2.7v1.2h-2.7z" fill="none" stroke="#808080" stroke-width=".2"/>
<path d="M92.9 86.5h2.7v1.2h-2.7z" fill-rule="evenodd" fill="#808080"/>
<path d="M92.9 86.5h2.7v1.2h-2.7z" fill="none" stroke="#808080" stroke-width=".2"/>
<path d="M93 89.5h2.7v1.2h-2.7z" fill-rule="evenodd" fill="#808080"/>
<path d="M93 89.5h2.7v1.2h-2.7z" fill="none" stroke="#808080" stroke-width=".2"/>
<path d="M92.9 92.5h2.7v1.2h-2.7z" fill-rule="evenodd" fill="#808080"/>
<path d="M92.9 92.5h2.7v1.2h-2.7z" fill="none" stroke="#808080" stroke-width=".2"/>
<path d="M104.7 89.5h2.7v1.2h-2.7z" fill-rule="evenodd" fill="#808080"/>
<path d="M104.7 89.5h2.7v1.2h-2.7z" fill="none" stroke="#808080" stroke-width=".2"/>
<path d="M104.7 86.5h2.7v1.2h-2.7z" fill-rule="evenodd" fill="#808080"/>
<path d="M104.7 86.5h2.7v1.2h-2.7z" fill="none" stroke="#808080" stroke-width=".2"/>
<path d="M104.7 83.6h2.7v1.2h-2.7z" fill-rule="evenodd" fill="#808080"/>
<path d="M104.7 83.6h2.7v1.2h-2.7z" fill="none" stroke="#808080" stroke-width=".2"/>
<path d="M133.3 87v5.3M137.2 87v5.3" fill="none" stroke="#808080" stroke-width=".38"/>
<path d="M133.1 85.6h4.3v1.4h-4.3z" fill-rule="evenodd" fill="#808080"/>
<path d="M133.1 85.6h4.3v1.4h-4.3z" fill="none" stroke="#808080" stroke-width=".2"/>
<path d="M133.1 92.2h4.3v1.4h-4.3z" fill-rule="evenodd" fill="#808080"/>
<path d="M133.1 92.2h4.3v1.4h-4.3z" fill="none" stroke="#808080" stroke-width=".2"/>
<path d="M123.7 94.1h5.4M123.7 98h5.4" fill="none" stroke="#808080" stroke-width=".38"/>
<path d="M122.4 93.9h1.4v4.3h-1.4z" fill-rule="evenodd" fill="#808080"/>
<path d="M122.4 93.9h1.4v4.3h-1.4z" fill="none" stroke="#808080" stroke-width=".2"/>
<path d="M129 93.9h1.4v4.3h-1.4z" fill-rule="evenodd" fill="#808080"/>
<path d="M129 93.9h1.4v4.3h-1.4z" fill="none" stroke="#808080" stroke-width=".2"/>
<path d="M123.8 80.6h5.4M123.8 84.5h5.4" fill="none" stroke="#808080" stroke-width=".38"/>
<path d="M122.5 80.4h1.4v4.3h-1.4z" fill-rule="evenodd" fill="#808080"/>
<path d="M122.5 80.4h1.4v4.3h-1.4z" fill="none" stroke="#808080" stroke-width=".2"/>
<path d="M129.1 80.4h1.4v4.3h-1.4z" fill-rule="evenodd" fill="#808080"/>
<path d="M129.1 80.4h1.4v4.3h-1.4z" fill="none" stroke="#808080" stroke-width=".2"/>
<path d="M115.1 83.9v1.8M118.2 83.9v1.7" fill="none" stroke="#808080" stroke-width=".25"/>
<path d="M115 85.6h3.4v1.8h-3.4z" fill-rule="evenodd" fill="#808080"/>
<path d="M115 85.6h3.4v1.8h-3.4z" fill="none" stroke="#808080" stroke-width=".2"/>
<path d="M115 82.2h3.4v1.8h-3.4z" fill-rule="evenodd" fill="#808080"/>
<path d="M115 82.2h3.4v1.8h-3.4z" fill="none" stroke="#808080" stroke-width=".2"/>
<path d="M112.9 95.3h1.8M113 98.3h1.7" fill="none" stroke="#808080" stroke-width=".25"/>
<path d="M111.3 95.1h1.7v3.4h-1.7z" fill-rule="evenodd" fill="#808080"/>
<path d="M111.3 95.1h1.7v3.4h-1.7z" fill="none" stroke="#808080" stroke-width=".2"/>
<path d="M114.6 95.1h1.8v3.4h-1.8z" fill-rule="evenodd" fill="#808080"/>
<path d="M114.6 95.1h1.8v3.4h-1.8z" fill="none" stroke="#808080" stroke-width=".2"/>
<path d="M55.6 158.8h5.4M55.6 162.6h5.4" fill="none" stroke="#808080" stroke-width=".38"/>
<path d="M54.3 158.5h1.4v4.4h-1.4z" fill-rule="evenodd" fill="#808080"/>
<path d="M54.3 158.5h1.4v4.4h-1.4z" fill="none" stroke="#808080" stroke-width=".2"/>
<path d="M60.9 158.5h1.4v4.4h-1.4z" fill-rule="evenodd" fill="#808080"/>
<path d="M60.9 158.5h1.4v4.4h-1.4z" fill="none" stroke="#808080" stroke-width=".2"/>
<path d="M56.8 173v5.4M60.7 173v5.4" fill="none" stroke="#808080" stroke-width=".38"/>
<path d="M56.6 178.3h4.3v1.4h-4.3z" fill-rule="evenodd" fill="#808080"/>
<path d="M56.6 178.3h4.3v1.4h-4.3z" fill="none" stroke="#808080" stroke-width=".2"/>
<path d="M56.6 171.7h4.3v1.4h-4.3z" fill-rule="evenodd" fill="#808080"/>
<path d="M56.6 171.7h4.3v1.4h-4.3z" fill="none" stroke="#808080" stroke-width=".2"/>
<path d="M66.4 186.7h5.4M66.4 182.8h5.4" fill="none" stroke="#808080" stroke-width=".38"/>
<path d="M71.7 182.6h1.4v4.3h-1.4z" fill-rule="evenodd" fill="#808080"/>
<path d="M71.7 182.6h1.4v4.3h-1.4z" fill="none" stroke="#808080" stroke-width=".2"/>
<path d="M65.1 182.6h1.4v4.3h-1.4z" fill-rule="evenodd" fill="#808080"/>
<path d="M65.1 182.6h1.4v4.3h-1.4z" fill="none" stroke="#808080" stroke-width=".2"/>
<path d="M22.2 83.7h11.4v13.8h-11.4z" fill="none" stroke="#808080" stroke-width=".34"/>
<path d="M77.8 175v1.7M80.9 175v1.7" fill="none" stroke="#808080" stroke-width=".25"/>
<path d="M77.6 173.3h3.4v1.8h-3.4z" fill-rule="evenodd" fill="#808080"/>
<path d="M77.6 173.3h3.4v1.8h-3.4z" fill="none" stroke="#808080" stroke-width=".2"/>
<path d="M77.6 176.7h3.4v1.8h-3.4z" fill-rule="evenodd" fill="#808080"/>
<path d="M77.6 176.7h3.4v1.8h-3.4z" fill="none" stroke="#808080" stroke-width=".2"/>
<path d="M92.6 68.3v6.6M96.4 68.3v6.6" fill="none" stroke="#808080" stroke-width=".38"/>
<path d="M96.5 73.2h1.5v1.2h-1.5z" fill-rule="evenodd" fill="#808080"/>
<path d="M96.5 73.2h1.5v1.2h-1.5z" fill="none" stroke="#808080" stroke-width=".2"/>
<path d="M96.5 71h1.5v1.2h-1.5z" fill-rule="evenodd" fill="#808080"/>
<path d="M96.5 71h1.5v1.2h-1.5z" fill="none" stroke="#808080" stroke-width=".2"/>
<path d="M96.5 68.8h1.5v1.2h-1.5z" fill-rule="evenodd" fill="#808080"/>
<path d="M96.5 68.8h1.5v1.2h-1.5z" fill="none" stroke="#808080" stroke-width=".2"/>
<path d="M91 68.8h1.5v1.2h-1.5z" fill-rule="evenodd" fill="#808080"/>
<path d="M91 68.8h1.5v1.2h-1.5z" fill="none" stroke="#808080" stroke-width=".2"/>
<path d="M91 73.2h1.5v1.2h-1.5z" fill-rule="evenodd" fill="#808080"/>
<path d="M91 73.2h1.5v1.2h-1.5z" fill="none" stroke="#808080" stroke-width=".2"/>
<path d="M90.5 158.4h5.4M90.5 162.3h5.4" fill="none" stroke="#808080" stroke-width=".38"/>
<path d="M89.2 158.2h1.4v4.3h-1.4z" fill-rule="evenodd" fill="#808080"/>
<path d="M89.2 158.2h1.4v4.3h-1.4z" fill="none" stroke="#808080" stroke-width=".2"/>
<path d="M95.8 158.2h1.4v4.3h-1.4z" fill-rule="evenodd" fill="#808080"/>
<path d="M95.8 158.2h1.4v4.3h-1.4z" fill="none" stroke="#808080" stroke-width=".2"/>
<path d="M87.6 172.5v5.4M91.5 172.5v5.4" fill="none" stroke="#808080" stroke-width=".38"/>
<path d="M87.4 177.8h4.3v1.4h-4.3z" fill-rule="evenodd" fill="#808080"/>
<path d="M87.4 177.8h4.3v1.4h-4.3z" fill="none" stroke="#808080" stroke-width=".2"/>
<path d="M87.4 171.2h4.3v1.4h-4.3z" fill-rule="evenodd" fill="#808080"/>
<path d="M87.4 171.2h4.3v1.4h-4.3z" fill="none" stroke="#808080" stroke-width=".2"/>
<path d="M99.7 186.2h5.3M99.7 182.2h5.3" fill="none" stroke="#808080" stroke-width=".38"/>
<path d="M104.9 182.1h1.4v4.3h-1.4z" fill-rule="evenodd" fill="#808080"/>
<path d="M104.9 182.1h1.4v4.3h-1.4z" fill="none" stroke="#808080" stroke-width=".2"/>
<path d="M98.3 182.1h1.4v4.3h-1.4z" fill-rule="evenodd" fill="#808080"/>
<path d="M98.3 182.1h1.4v4.3h-1.4z" fill="none" stroke="#808080" stroke-width=".2"/>
<path d="M38.5 83.7h11.4v13.8h-11.4z" fill="none" stroke="#808080" stroke-width=".34"/>
<path d="M111 174.9v1.7M114.1 174.8v1.8" fill="none" stroke="#808080" stroke-width=".25"/>
<path d="M110.9 173.2h3.4v1.8h-3.4z" fill-rule="evenodd" fill="#808080"/>
<path d="M110.9 173.2h3.4v1.8h-3.4z" fill="none" stroke="#808080" stroke-width=".2"/>
<path d="M110.9 176.6h3.4v1.8h-3.4z" fill-rule="evenodd" fill="#808080"/>
<path d="M110.9 176.6h3.4v1.8h-3.4z" fill="none" stroke="#808080" stroke-width=".2"/>
<path d="M123.1 123.7v1.8M126.2 123.7v1.7" fill="none" stroke="#808080" stroke-width=".25"/>
<path d="M122.9 125.4h3.4v1.8h-3.4z" fill-rule="evenodd" fill="#808080"/>
<path d="M122.9 125.4h3.4v1.8h-3.4z" fill="none" stroke="#808080" stroke-width=".2"/>
<path d="M122.9 122h3.4v1.8h-3.4z" fill-rule="evenodd" fill="#808080"/>
<path d="M122.9 122h3.4v1.8h-3.4z" fill="none" stroke="#808080" stroke-width=".2"/>
<path d="M118.4 123.7v1.8M121.5 123.7v1.7" fill="none" stroke="#808080" stroke-width=".25"/>
<path d="M118.3 125.4h3.4v1.8h-3.4z" fill-rule="evenodd" fill="#808080"/>
<path d="M118.3 125.4h3.4v1.8h-3.4z" fill="none" stroke="#808080" stroke-width=".2"/>
<path d="M118.3 122h3.4v1.8h-3.4z" fill-rule="evenodd" fill="#808080"/>
<path d="M118.3 122h3.4v1.8h-3.4z" fill="none" stroke="#808080" stroke-width=".2"/>
<path d="M89.5 131.3v5.3M93.4 131.3v5.3" fill="none" stroke="#808080" stroke-width=".38"/>
<path d="M89.3 136.6h4.3v1.3h-4.3z" fill-rule="evenodd" fill="#808080"/>
<path d="M89.3 136.6h4.3v1.3h-4.3z" fill="none" stroke="#808080" stroke-width=".2"/>
<path d="M89.3 130h4.3v1.3h-4.3z" fill-rule="evenodd" fill="#808080"/>
<path d="M89.3 130h4.3v1.3h-4.3z" fill="none" stroke="#808080" stroke-width=".2"/>
<path d="M179.6 83.2v5.3M183.5 83.2v5.3" fill="none" stroke="#808080" stroke-width=".38"/>
<path d="M179.4 81.9h4.3v1.3h-4.3z" fill-rule="evenodd" fill="#808080"/>
<path d="M179.4 81.9h4.3v1.3h-4.3z" fill="none" stroke="#808080" stroke-width=".2"/>
<path d="M179.4 88.5h4.3v1.3h-4.3z" fill-rule="evenodd" fill="#808080"/>
<path d="M179.4 88.5h4.3v1.3h-4.3z" fill="none" stroke="#808080" stroke-width=".2"/>
<path d="M189.1 83.2v5.3M193 83.2v5.3" fill="none" stroke="#808080" stroke-width=".38"/>
<path d="M188.9 81.9h4.3v1.3h-4.3z" fill-rule="evenodd" fill="#808080"/>
<path d="M188.9 81.9h4.3v1.3h-4.3z" fill="none" stroke="#808080" stroke-width=".2"/>
<path d="M188.9 88.5h4.3v1.3h-4.3z" fill-rule="evenodd" fill="#808080"/>
<path d="M188.9 88.5h4.3v1.3h-4.3z" fill="none" stroke="#808080" stroke-width=".2"/>
<path d="M189.1 71.6v5.4M193 71.6v5.4" fill="none" stroke="#808080" stroke-width=".38"/>
<path d="M188.9 70.3h4.3v1.4h-4.3z" fill-rule="evenodd" fill="#808080"/>
<path d="M188.9 70.3h4.3v1.4h-4.3z" fill="none" stroke="#808080" stroke-width=".2"/>
<path d="M188.9 76.9h4.3v1.4h-4.3z" fill-rule="evenodd" fill="#808080"/>
<path d="M188.9 76.9h4.3v1.4h-4.3z" fill="none" stroke="#808080" stroke-width=".2"/>
<path d="M179.6 71.6v5.4M183.5 71.6v5.4" fill="none" stroke="#808080" stroke-width=".38"/>
<path d="M179.4 70.3h4.3v1.4h-4.3z" fill-rule="evenodd" fill="#808080"/>
<path d="M179.4 70.3h4.3v1.4h-4.3z" fill="none" stroke="#808080" stroke-width=".2"/>
<path d="M179.4 76.9h4.3v1.4h-4.3z" fill-rule="evenodd" fill="#808080"/>
<path d="M179.4 76.9h4.3v1.4h-4.3z" fill="none" stroke="#808080" stroke-width=".2"/>
<path d="M102 145.1h5.3M102 141.1h5.3" fill="none" stroke="#808080" stroke-width=".38"/>
<path d="M107.3 140.9h1.3v4.3h-1.3z" fill-rule="evenodd" fill="#808080"/>
<path d="M107.3 140.9h1.3v4.3h-1.3z" fill="none" stroke="#808080" stroke-width=".2"/>
<path d="M100.7 140.9h1.3v4.3h-1.3z" fill-rule="evenodd" fill="#808080"/>
<path d="M100.7 140.9h1.3v4.3h-1.3z" fill="none" stroke="#808080" stroke-width=".2"/>
<path d="M117.2 145.1h5.3M117.2 141.1h5.3" fill="none" stroke="#808080" stroke-width=".38"/>
<path d="M122.5 141h1.3v4.3h-1.3z" fill-rule="evenodd" fill="#808080"/>
<path d="M122.5 141h1.3v4.3h-1.3z" fill="none" stroke="#808080" stroke-width=".2"/>
<path d="M115.9 141h1.3v4.3h-1.3z" fill-rule="evenodd" fill="#808080"/>
<path d="M115.9 141h1.3v4.3h-1.3z" fill="none" stroke="#808080" stroke-width=".2"/>
<path d="M80 121.3v5.4M83.9 121.3v5.4" fill="none" stroke="#808080" stroke-width=".38"/>
<path d="M79.8 120h4.3v1.4h-4.3z" fill-rule="evenodd" fill="#808080"/>
<path d="M79.8 120h4.3v1.4h-4.3z" fill="none" stroke="#808080" stroke-width=".2"/>
<path d="M79.8 126.6h4.3v1.4h-4.3z" fill-rule="evenodd" fill="#808080"/>
<path d="M79.8 126.6h4.3v1.4h-4.3z" fill="none" stroke="#808080" stroke-width=".2"/>
<path d="M72.3 117.3v5.3M76.2 117.3v5.3" fill="none" stroke="#808080" stroke-width=".38"/>
<path d="M72.1 122.6h4.3v1.3h-4.3z" fill-rule="evenodd" fill="#808080"/>
<path d="M72.1 122.6h4.3v1.3h-4.3z" fill="none" stroke="#808080" stroke-width=".2"/>
<path d="M72.1 116h4.3v1.3h-4.3z" fill-rule="evenodd" fill="#808080"/>
<path d="M72.1 116h4.3v1.3h-4.3z" fill="none" stroke="#808080" stroke-width=".2"/>
<path d="M164.3 69.3h6.6M164.3 73.1h6.6" fill="none" stroke="#808080" stroke-width=".38"/>
<path d="M169.2 67.7h1.2v1.5h-1.2z" fill-rule="evenodd" fill="#808080"/>
<path d="M169.2 67.7h1.2v1.5h-1.2z" fill="none" stroke="#808080" stroke-width=".2"/>
<path d="M167 67.7h1.1v1.5h-1.1z" fill-rule="evenodd" fill="#808080"/>
<path d="M167 67.7h1.1v1.5h-1.1z" fill="none" stroke="#808080" stroke-width=".2"/>
<path d="M164.8 67.7h1.1v1.5h-1.1z" fill-rule="evenodd" fill="#808080"/>
<path d="M164.8 67.7h1.1v1.5h-1.1z" fill="none" stroke="#808080" stroke-width=".2"/>
<path d="M164.8 73.2h1.1v1.5h-1.1z" fill-rule="evenodd" fill="#808080"/>
<path d="M164.8 73.2h1.1v1.5h-1.1z" fill="none" stroke="#808080" stroke-width=".2"/>
<path d="M169.2 73.2h1.2v1.5h-1.2z" fill-rule="evenodd" fill="#808080"/>
<path d="M169.2 73.2h1.2v1.5h-1.2z" fill="none" stroke="#808080" stroke-width=".2"/>
<path d="M148.2 96.2h5.3M148.2 100.2h5.3" fill="none" stroke="#808080" stroke-width=".38"/>
<path d="M146.9 96.1h1.3v4.3h-1.3z" fill-rule="evenodd" fill="#808080"/>
<path d="M146.9 96.1h1.3v4.3h-1.3z" fill="none" stroke="#808080" stroke-width=".2"/>
<path d="M153.5 96.1h1.3v4.3h-1.3z" fill-rule="evenodd" fill="#808080"/>
<path d="M153.5 96.1h1.3v4.3h-1.3z" fill="none" stroke="#808080" stroke-width=".2"/>
<path d="M195.5 59.2v5.3M199.3 59.2v5.3" fill="none" stroke="#808080" stroke-width=".38"/>
<path d="M195.2 64.5h4.4v1.3h-4.4z" fill-rule="evenodd" fill="#808080"/>
<path d="M195.2 64.5h4.4v1.3h-4.4z" fill="none" stroke="#808080" stroke-width=".2"/>
<path d="M195.2 57.9h4.4v1.3h-4.4z" fill-rule="evenodd" fill="#808080"/>
<path d="M195.2 57.9h4.4v1.3h-4.4z" fill="none" stroke="#808080" stroke-width=".2"/>
<path d="M141.3 153.8h11.5v13.8h-11.5z" fill="none" stroke="#808080" stroke-width=".34"/>
<path d="M160.2 162.8v5.3M164.1 162.8v5.3" fill="none" stroke="#808080" stroke-width=".38"/>
<path d="M160 161.5h4.3v1.3h-4.3z" fill-rule="evenodd" fill="#808080"/>
<path d="M160 161.5h4.3v1.3h-4.3z" fill="none" stroke="#808080" stroke-width=".2"/>
<path d="M160 168.1h4.3v1.3h-4.3z" fill-rule="evenodd" fill="#808080"/>
<path d="M160 168.1h4.3v1.3h-4.3z" fill="none" stroke="#808080" stroke-width=".2"/>
<path d="M115 110.9v6.6M118.7 110.9v6.6" fill="none" stroke="#808080" stroke-width=".38"/>
<path d="M118.8 115.8h1.6v1.2h-1.6z" fill-rule="evenodd" fill="#808080"/>
<path d="M118.8 115.8h1.6v1.2h-1.6z" fill="none" stroke="#808080" stroke-width=".2"/>
<path d="M118.8 113.6h1.6v1.2h-1.6z" fill-rule="evenodd" fill="#808080"/>
<path d="M118.8 113.6h1.6v1.2h-1.6z" fill="none" stroke="#808080" stroke-width=".2"/>
<path d="M118.8 111.4h1.6v1.2h-1.6z" fill-rule="evenodd" fill="#808080"/>
<path d="M118.8 111.4h1.6v1.2h-1.6z" fill="none" stroke="#808080" stroke-width=".2"/>
<path d="M113.4 111.4h1.5v1.2h-1.5z" fill-rule="evenodd" fill="#808080"/>
<path d="M113.4 111.4h1.5v1.2h-1.5z" fill="none" stroke="#808080" stroke-width=".2"/>
<path d="M113.4 115.8h1.5v1.2h-1.5z" fill-rule="evenodd" fill="#808080"/>
<path d="M113.4 115.8h1.5v1.2h-1.5z" fill="none" stroke="#808080" stroke-width=".2"/>
<path d="M156.1 69.8v1.7M159.2 69.7v1.8" fill="none" stroke="#808080" stroke-width=".25"/>
<path d="M156 68.1h3.3v1.8h-3.3z" fill-rule="evenodd" fill="#808080"/>
<path d="M156 68.1h3.3v1.8h-3.3z" fill="none" stroke="#808080" stroke-width=".2"/>
<path d="M156 71.5h3.3v1.7h-3.3z" fill-rule="evenodd" fill="#808080"/>
<path d="M156 71.5h3.3v1.7h-3.3z" fill="none" stroke="#808080" stroke-width=".2"/>
<path d="M158.4 77.2h1.7M158.4 80.3h1.8" fill="none" stroke="#808080" stroke-width=".25"/>
<path d="M160.1 77.1h1.7v3.4h-1.7z" fill-rule="evenodd" fill="#808080"/>
<path d="M160.1 77.1h1.7v3.4h-1.7z" fill="none" stroke="#808080" stroke-width=".2"/>
<path d="M156.7 77.1h1.8v3.4h-1.8z" fill-rule="evenodd" fill="#808080"/>
<path d="M156.7 77.1h1.8v3.4h-1.8z" fill="none" stroke="#808080" stroke-width=".2"/>
<path d="M105.4 70.4v1.8M108.5 70.4v1.7" fill="none" stroke="#808080" stroke-width=".25"/>
<path d="M105.2 72.1h3.4v1.8h-3.4z" fill-rule="evenodd" fill="#808080"/>
<path d="M105.2 72.1h3.4v1.8h-3.4z" fill="none" stroke="#808080" stroke-width=".2"/>
<path d="M105.2 68.7h3.4v1.8h-3.4z" fill-rule="evenodd" fill="#808080"/>
<path d="M105.2 68.7h3.4v1.8h-3.4z" fill="none" stroke="#808080" stroke-width=".2"/>
<path d="M110 70.4v1.8M113.1 70.4v1.8" fill="none" stroke="#808080" stroke-width=".25"/>
<path d="M109.9 72.1h3.3v1.8h-3.3z" fill-rule="evenodd" fill="#808080"/>
<path d="M109.9 72.1h3.3v1.8h-3.3z" fill="none" stroke="#808080" stroke-width=".2"/>
<path d="M109.9 68.7h3.3v1.8h-3.3z" fill-rule="evenodd" fill="#808080"/>
<path d="M109.9 68.7h3.3v1.8h-3.3z" fill="none" stroke="#808080" stroke-width=".2"/>
<path d="M83.5 67.8v1.7M86.6 67.7v1.8" fill="none" stroke="#808080" stroke-width=".25"/>
<path d="M83.4 66h3.3v1.8h-3.3z" fill-rule="evenodd" fill="#808080"/>
<path d="M83.4 66h3.3v1.8h-3.3z" fill="none" stroke="#808080" stroke-width=".2"/>
<path d="M83.4 69.4h3.3v1.8h-3.3z" fill-rule="evenodd" fill="#808080"/>
<path d="M83.4 69.4h3.3v1.8h-3.3z" fill="none" stroke="#808080" stroke-width=".2"/>
<path d="M104.8 113.2v1.8M107.9 113.2v1.8" fill="none" stroke="#808080" stroke-width=".25"/>
<path d="M104.6 111.5h3.4v1.8h-3.4z" fill-rule="evenodd" fill="#808080"/>
<path d="M104.6 111.5h3.4v1.8h-3.4z" fill="none" stroke="#808080" stroke-width=".2"/>
<path d="M104.6 114.9h3.4v1.8h-3.4z" fill-rule="evenodd" fill="#808080"/>
<path d="M104.6 114.9h3.4v1.8h-3.4z" fill="none" stroke="#808080" stroke-width=".2"/>
<path d="M97.4 113.2v1.8M100.5 113.2v1.8" fill="none" stroke="#808080" stroke-width=".25"/>
<path d="M97.2 111.5h3.4v1.8h-3.4z" fill-rule="evenodd" fill="#808080"/>
<path d="M97.2 111.5h3.4v1.8h-3.4z" fill="none" stroke="#808080" stroke-width=".2"/>
<path d="M97.2 114.9h3.4v1.8h-3.4z" fill-rule="evenodd" fill="#808080"/>
<path d="M97.2 114.9h3.4v1.8h-3.4z" fill="none" stroke="#808080" stroke-width=".2"/>
<path d="M101.4 171.5h6.6M101.4 175.3h6.6" fill="none" stroke="#808080" stroke-width=".38"/>
<path d="M106.3 169.9h1.2v1.5h-1.2z" fill-rule="evenodd" fill="#808080"/>
<path d="M106.3 169.9h1.2v1.5h-1.2z" fill="none" stroke="#808080" stroke-width=".2"/>
<path d="M104.1 169.9h1.2v1.5h-1.2z" fill-rule="evenodd" fill="#808080"/>
<path d="M104.1 169.9h1.2v1.5h-1.2z" fill="none" stroke="#808080" stroke-width=".2"/>
<path d="M101.9 169.9h1.2v1.5h-1.2z" fill-rule="evenodd" fill="#808080"/>
<path d="M101.9 169.9h1.2v1.5h-1.2z" fill="none" stroke="#808080" stroke-width=".2"/>
<path d="M101.9 175.4h1.2v1.5h-1.2z" fill-rule="evenodd" fill="#808080"/>
<path d="M101.9 175.4h1.2v1.5h-1.2z" fill="none" stroke="#808080" stroke-width=".2"/>
<path d="M106.3 175.4h1.2v1.5h-1.2z" fill-rule="evenodd" fill="#808080"/>
<path d="M106.3 175.4h1.2v1.5h-1.2z" fill="none" stroke="#808080" stroke-width=".2"/>
<path d="M67.4 172.9h6.7M67.4 176.7h6.7" fill="none" stroke="#808080" stroke-width=".38"/>
<path d="M72.4 171.3h1.2v1.5h-1.2z" fill-rule="evenodd" fill="#808080"/>
<path d="M72.4 171.3h1.2v1.5h-1.2z" fill="none" stroke="#808080" stroke-width=".2"/>
<path d="M70.1 171.3h1.2v1.5h-1.2z" fill-rule="evenodd" fill="#808080"/>
<path d="M70.1 171.3h1.2v1.5h-1.2z" fill="none" stroke="#808080" stroke-width=".2"/>
<path d="M67.9 171.3h1.2v1.5h-1.2z" fill-rule="evenodd" fill="#808080"/>
<path d="M67.9 171.3h1.2v1.5h-1.2z" fill="none" stroke="#808080" stroke-width=".2"/>
<path d="M67.9 176.8h1.2v1.5h-1.2z" fill-rule="evenodd" fill="#808080"/>
<path d="M67.9 176.8h1.2v1.5h-1.2z" fill="none" stroke="#808080" stroke-width=".2"/>
<path d="M72.4 176.8h1.2v1.5h-1.2z" fill-rule="evenodd" fill="#808080"/>
<g fill="none" stroke="#808080" stroke-width=".2">
<path d="M24.1 35.7l-4.7 4.8M36.6 35.5l-4.8 4.8M42.5 35.5l-4.7 4.8M48.5 35.5l-4.8 4.8M54.4 35.5l-4.7 4.8M60.3 35.5l-4.7 4.8M66.3 35.5l-4.8 4.8M72.2 35.5l-4.7 4.8M78.1 35.5l-4.7 4.8M84.1 35.5l-4.8 4.8M90 35.5l-4.7 4.8M96 35.5l-4.8 4.8"/>
<path d="M101.9 35.5l-4.7 4.8M107.9 35.5l-4.8 4.8M113.8 35.5l-4.7 4.8M119.8 35.5l-4.8 4.8M125.7 35.5l-4.8 4.8M131.6 35.5l-4.7 4.8M137.6 35.5l-4.8 4.8M143.5 35.5l-4.7 4.8M149.4 35.5l-4.7 4.8M155.4 35.5l-4.8 4.8M161.3 35.5l-4.7 4.8M167.3 35.5l-4.8 4.8"/>
<path d="M173.2 35.5l-4.8 4.8M179.2 35.5l-4.8 4.8M185.1 35.5l-4.8 4.8M196.5 35.7l-4.8 4.8M22.8 50.3l4.7 4.8M27.5 50.3l-4.7 4.8M36.6 41.4l-4.8 4.8M36.6 53.3l-4.8 4.8M36.6 47.4l-4.8 4.7M42.5 41.4l-4.7 4.8M42.5 53.3l-4.7 4.8M42.5 47.4l-4.7 4.7"/>
<path d="M48.5 41.4l-4.8 4.8M48.5 53.3l-4.8 4.8M48.5 47.4l-4.8 4.7M54.4 41.4l-4.7 4.8M54.4 53.3l-4.7 4.8M54.4 47.4l-4.7 4.7M60.3 41.4l-4.7 4.8M60.3 47.4l-4.7 4.7M60.3 53.3l-4.7 4.8M66.3 41.4l-4.8 4.8M66.3 53.3l-4.8 4.8M66.3 47.4l-4.8 4.7"/>
<path d="M72.2 41.4l-4.7 4.8M72.2 53.3l-4.7 4.8M72.2 47.4l-4.7 4.7M74.2 58.6l4.7 4.8M78.1 41.4l-4.7 4.8M78.1 53.3l-4.7 4.8M78.1 47.4l-4.7 4.7M78.9 58.6l-4.7 4.8M82.3 58.3l4.8 4.8M84.1 41.4l-4.8 4.8M84.1 53.3l-4.8 4.8M84.1 47.4l-4.8 4.7"/>
<path d="M87.1 58.3l-4.8 4.8M90 41.4l-4.7 4.8M90 53.3l-4.7 4.8M90 47.4l-4.7 4.7M91.3 58.1l4.8 4.8M96 41.4l-4.8 4.8M96 53.3l-4.8 4.8M96 47.4l-4.8 4.7M96.1 58.1l-4.8 4.8M98.2 58.1l4.7 4.8M101.9 41.4l-4.7 4.8M101.9 53.3l-4.7 4.8"/>
<path d="M101.9 47.4l-4.7 4.7M102.9 58.1l-4.7 4.8M107.9 41.4l-4.8 4.8M107.9 53.3l-4.8 4.8M107.9 47.4l-4.8 4.7M113.8 41.4l-4.7 4.8M113.8 47.4l-4.7 4.7M113.8 53.3l-4.7 4.8M119.8 41.4l-4.8 4.8M119.8 53.3l-4.8 4.8M119.8 47.4l-4.8 4.7M125.7 41.4l-4.8 4.8"/>
<path d="M125.7 53.3l-4.8 4.8M125.7 47.4l-4.8 4.7M131.6 41.4l-4.7 4.8M131.6 53.3l-4.7 4.8M131.6 47.4l-4.7 4.7M137.6 41.4l-4.8 4.8M137.6 53.3l-4.8 4.8M137.6 47.4l-4.8 4.7M143.5 41.4l-4.7 4.8M143.5 53.3l-4.7 4.8M143.5 47.4l-4.7 4.7M149.4 41.4l-4.7 4.8"/>
<path d="M149.4 53.3l-4.7 4.8M149.4 47.4l-4.7 4.7M155.4 41.4l-4.8 4.8M155.4 53.3l-4.8 4.8M155.4 47.4l-4.8 4.7M161.3 41.4l-4.7 4.8M161.3 53.3l-4.7 4.8M161.3 47.4l-4.7 4.7M167.3 41.4l-4.8 4.8M167.3 47.4l-4.8 4.7M167.3 53.3l-4.8 4.8M173.2 41.4l-4.8 4.8"/>
<path d="M173.2 53.3l-4.8 4.8M173.2 47.4l-4.8 4.7M179.2 41.4l-4.8 4.8M179.2 53.3l-4.8 4.8M179.2 47.4l-4.8 4.7M185.1 41.4l-4.8 4.8M185.1 53.3l-4.8 4.8M185.1 47.4l-4.8 4.7M195 48.7l4.8 4.8M199.8 48.7l-4.8 4.8M13.1 75.3l4.7 4.8M17.8 75.3l-4.7 4.8"/>
<path d="M27.6 69.8l4.8 4.8M32.4 69.8l-4.8 4.8M52.7 70.9l4.7 4.7M52.7 79.8l4.7 4.7M55.6 60.3l4.8 4.7M55.6 70.9l4.8 4.7M55.6 79.8l4.8 4.7M57.4 79.8l-4.7 4.7M57.4 70.9l-4.7 4.7M58.6 70.9l4.8 4.7M58.6 79.8l4.8 4.7M60.4 60.3l-4.8 4.7"/>
<path d="M60.4 70.9l-4.8 4.7M60.4 79.8l-4.8 4.7M61.6 70.9l4.8 4.7M61.6 79.8l4.8 4.7M63.4 70.9l-4.8 4.7M63.4 79.8l-4.8 4.7M64.2 60.7l4.8 4.7M66.4 70.9l-4.8 4.7M66.4 79.8l-4.8 4.7M69 60.7l-4.8 4.7M85.9 72.3l4.7 4.7M90.6 72.3l-4.7 4.7"/>
<path d="M90.6 79.2l4.8 4.8M95.4 79.2l-4.8 4.8M99 71.5l4.8 4.7M99.8 68.7l4.8 4.8M100 78.5l4.8 4.8M103.8 71.5l-4.8 4.7M104.6 68.7l-4.8 4.8M104.8 78.5l-4.8 4.8M117.8 66.2l4.7 4.8M122.5 66.2l-4.7 4.8M124.2 66.3l4.7 4.7M126.6 71.4l4.8 4.8"/>
<path d="M128.9 66.3l-4.7 4.7M131.4 71.4l-4.8 4.8M143.6 74.3l4.7 4.8M148.3 74.3l-4.7 4.8M170 76.4l4.7 4.8M174.1 66.3l4.8 4.7M174.7 76.4l-4.7 4.8M178.9 66.3l-4.8 4.7M195 67.1l4.8 4.7M199.8 67.1l-4.8 4.7M16.8 83.1l4.7 4.7M21.5 83.1l-4.7 4.7"/>
<path d="M61.6 86.9l4.8 4.8M66.4 86.9l-4.8 4.8M82.2 88l4.7 4.8M85.4 85.3l4.7 4.7M86.9 88l-4.7 4.8M90.1 85.3l-4.7 4.7M97.8 87.7l4.7 4.8M102.5 87.7l-4.7 4.8M113.5 89.9l4.8 4.8M118.3 89.9l-4.8 4.8M139.4 95.2l4.8 4.7M144.2 95.2l-4.8 4.7"/>
<path d="M164.5 80.3l4.7 4.8M169.2 80.3l-4.7 4.8M169.3 93.3l4.7 4.8M172.4 89.2l4.7 4.7M174 93.3l-4.7 4.8M177.1 89.2l-4.7 4.7M24 100.4l4.8 4.7M28.8 100.4l-4.8 4.7M41.5 100.8l4.8 4.8M46.3 100.8l-4.8 4.8M52.7 118.3l4.7 4.7M57.4 118.3l-4.7 4.7"/>
<path d="M107.7 113.7l4.7 4.7M112.4 113.7l-4.7 4.7M120.4 110.3l4.7 4.8M125.1 110.3l-4.7 4.8M128 107.4l4.8 4.7M132.8 107.4l-4.8 4.7M173.3 103.6l4.7 4.7M173.3 111.8l4.7 4.8M178 103.6l-4.7 4.7M178 111.8l-4.7 4.8M180.2 119.8l4.7 4.7M184.9 119.8l-4.7 4.7"/>
<path d="M197.5 118.2l4.8 4.7M202.3 118.2l-4.8 4.7M205.2 109l4.7 4.7M209.9 109l-4.7 4.7M58.6 130.9l4.8 4.7M63.4 130.9l-4.8 4.7M70.2 125.7l4.7 4.8M74.9 125.7l-4.7 4.8M88.7 123.4l4.7 4.7M90.9 121.4l4.8 4.8M93.4 123.4l-4.7 4.7M93.7 132l4.8 4.8"/>
<path d="M95.7 121.4l-4.8 4.8M96.4 129.3l4.7 4.8M98.5 132l-4.8 4.8M101.1 129.3l-4.7 4.8M103.6 122.8l4.8 4.7M108.4 122.8l-4.8 4.7M109.9 136.4l4.7 4.8M114.6 136.4l-4.7 4.8M168.2 135.2l4.7 4.8M172.9 135.2l-4.7 4.8M173 126.8l4.7 4.8M177.7 126.8l-4.7 4.8"/>
<path d="M185.2 126.7l4.8 4.8M187 137.8l4.8 4.8M190 126.7l-4.8 4.8M191.5 123.2l4.8 4.8M191.8 137.8l-4.8 4.8M195.2 137.8l4.8 4.8M196.3 123.2l-4.8 4.8M200 137.8l-4.8 4.8M47.2 154.1l4.8 4.7M49.1 148.5l4.8 4.7M52 154.1l-4.8 4.7M53.9 148.5l-4.8 4.7"/>
<path d="M64 154.8l4.7 4.7M68.7 154.8l-4.7 4.7M78.1 155.2l4.7 4.8M82.8 155.2l-4.7 4.8M103.7 150.4l4.7 4.7M108.4 150.4l-4.7 4.7M176.6 156.5l4.7 4.7M181.3 156.5l-4.7 4.7M56.4 166.4l4.7 4.8M61.1 166.4l-4.7 4.8M65.7 164.8l4.7 4.8M70.4 164.8l-4.7 4.8"/>
<path d="M72.4 176.8h1.2v1.5h-1.2zM76.9 167.3l4.8 4.7M81.7 167.3l-4.8 4.7M81.9 169.5l4.8 4.7M86.7 169.5l-4.8 4.7M87.2 165.7l4.7 4.7M91.9 165.7l-4.7 4.7M98.8 163.3l4.8 4.7M103.6 163.3l-4.8 4.7M110.2 166l4.7 4.8M114.9 166l-4.7 4.8M124.2 168.7l4.7 4.7"/>
<path d="M128.9 168.7l-4.7 4.7M141.9 170.9l4.7 4.8M146.6 170.9l-4.7 4.8M173 178.5l4.8 4.7M177.8 178.5l-4.8 4.7M52.4 197.6l4.7 4.7M57.1 197.6l-4.7 4.7M71.5 195.8l4.7 4.8M76.2 195.8l-4.7 4.8M100.4 186.4l4.8 4.8M105.2 186.4l-4.8 4.8M105.4 196l4.7 4.7"/>
<path d="M110.1 196l-4.7 4.7M173 186.3l4.8 4.8M177.8 186.3l-4.8 4.8M179.6 192.2l4.8 4.7M184.4 192.2l-4.8 4.7M191.3 196.6l4.7 4.7M196 196.6l-4.7 4.7M197.4 190.5l4.7 4.7M202.1 190.5l-4.7 4.7M205.3 182l4.8 4.7M210.1 182l-4.8 4.7M52.4 210.5l4.7 4.8"/>
<path d="M57.1 210.5l-4.7 4.8M57.5 210.2l4.8 4.7M58.9 213.2l4.7 4.7M62.3 210.2l-4.8 4.7M63.6 213.2l-4.7 4.7M64.2 200.5l4.8 4.8M65.5 213.2l4.7 4.7M65.5 205.7l4.7 4.7M68.8 216.8l4.8 4.8M69 200.5l-4.8 4.8M70.2 213.2l-4.7 4.7M70.2 205.7l-4.7 4.7"/>
<path d="M73.6 216.8l-4.8 4.8M89.5 211l4.8 4.8M92.8 200.1l4.7 4.8M94.3 211l-4.8 4.8M96.1 210.7l4.8 4.7M97.5 213.7l4.8 4.8M97.5 200.1l-4.7 4.8M100.9 210.7l-4.8 4.7M102.3 213.7l-4.8 4.8M104 213.8l4.7 4.8M104 204.9l4.7 4.7M107.9 217.4l4.8 4.8"/>
<path d="M108.7 213.8l-4.7 4.8M108.7 204.9l-4.7 4.7M112.7 217.4l-4.8 4.8M130.4 210.7l4.7 4.8M135.1 210.7l-4.7 4.8M168.4 210.1l4.7 4.7M173.1 210.1l-4.7 4.7M173.2 200.9l4.8 4.8M178 200.9l-4.8 4.8M184.6 200.9l4.8 4.8M186.6 210.8l4.7 4.7M189.4 200.9l-4.8 4.8"/>
<path d="M191.3 210.8l-4.7 4.7M195.5 210.8l4.8 4.7M200.3 210.8l-4.8 4.7M15.2 236.2l-4.7 4.8M23.9 231.9l4.8 4.7M28.7 231.9l-4.8 4.7M40.3 236.5l4.7 4.8M45 236.5l-4.7 4.8M48.1 222.3l4.7 4.7M52.5 220.3l4.7 4.7M52.8 222.3l-4.7 4.7M56.6 231.9l4.8 4.7"/>
<path d="M57.2 220.3l-4.7 4.7M61.4 231.9l-4.8 4.7M73 236.5l4.8 4.8M77.8 236.5l-4.8 4.8M89.4 231.9l4.7 4.7M94.1 231.9l-4.7 4.7M105.7 236.5l4.8 4.8M110.5 236.5l-4.8 4.8M122.1 231.9l4.8 4.7M126.9 231.9l-4.8 4.7M138.5 236.5l4.8 4.8M143.3 236.5l-4.8 4.8"/>
<path d="M154.9 231.9l4.7 4.7M159.6 231.9l-4.7 4.7M202.4 236.2l-4.8 4.8"/>
<circle cx="21.8" cy="38.1" r="2.32"/>
<circle cx="34.2" cy="37.9" r="2.32"/>
<circle cx="40.1" cy="37.9" r="2.32"/>
<circle cx="46.1" cy="37.9" r="2.32"/>
<circle cx="52" cy="37.9" r="2.32"/>
<circle cx="58" cy="37.9" r="2.32"/>
<circle cx="63.9" cy="37.9" r="2.32"/>
<circle cx="69.9" cy="37.9" r="2.32"/>
<circle cx="75.8" cy="37.9" r="2.32"/>
<circle cx="81.7" cy="37.9" r="2.32"/>
<circle cx="87.7" cy="37.9" r="2.32"/>
<circle cx="93.6" cy="37.9" r="2.32"/>
<circle cx="99.6" cy="37.9" r="2.32"/>
<circle cx="105.5" cy="37.9" r="2.32"/>
<circle cx="111.4" cy="37.9" r="2.32"/>
<circle cx="117.4" cy="37.9" r="2.32"/>
<circle cx="123.3" cy="37.9" r="2.32"/>
<circle cx="129.2" cy="37.9" r="2.32"/>
<circle cx="135.2" cy="37.9" r="2.32"/>
<circle cx="141.1" cy="37.9" r="2.32"/>
<circle cx="147.1" cy="37.9" r="2.32"/>
<circle cx="153" cy="37.9" r="2.32"/>
<circle cx="159" cy="37.9" r="2.32"/>
<circle cx="164.9" cy="37.9" r="2.32"/>
<circle cx="170.9" cy="37.9" r="2.32"/>
<circle cx="176.8" cy="37.9" r="2.32"/>
<circle cx="182.7" cy="37.9" r="2.32"/>
<circle cx="194.1" cy="38.1" r="2.32"/>
<circle cx="34.2" cy="55.7" r="2.32"/>
<circle cx="34.2" cy="43.8" r="2.32"/>
<circle cx="34.2" cy="49.7" r="2.32"/>
<circle cx="40.1" cy="49.7" r="2.32"/>
<circle cx="40.1" cy="43.8" r="2.32"/>
<circle cx="40.1" cy="55.7" r="2.32"/>
<circle cx="46.1" cy="55.7" r="2.32"/>
<circle cx="46.1" cy="49.7" r="2.32"/>
<circle cx="46.1" cy="43.8" r="2.32"/>
<circle cx="52" cy="49.7" r="2.32"/>
<circle cx="52" cy="55.7" r="2.32"/>
<circle cx="52" cy="43.8" r="2.32"/>
<circle cx="58" cy="49.7" r="2.32"/>
<circle cx="58" cy="55.7" r="2.32"/>
<circle cx="58" cy="43.8" r="2.32"/>
<circle cx="63.9" cy="49.7" r="2.32"/>
<circle cx="63.9" cy="55.7" r="2.32"/>
<circle cx="63.9" cy="43.8" r="2.32"/>
<circle cx="69.9" cy="49.7" r="2.32"/>
<circle cx="69.9" cy="55.7" r="2.32"/>
<circle cx="69.9" cy="43.8" r="2.32"/>
<circle cx="75.8" cy="49.7" r="2.32"/>
<circle cx="75.8" cy="55.7" r="2.32"/>
<circle cx="75.8" cy="43.8" r="2.32"/>
<circle cx="81.7" cy="55.7" r="2.32"/>
<circle cx="81.7" cy="49.7" r="2.32"/>
<circle cx="81.7" cy="43.8" r="2.32"/>
<circle cx="87.7" cy="49.7" r="2.32"/>
<circle cx="87.7" cy="43.8" r="2.32"/>
<circle cx="87.7" cy="55.7" r="2.32"/>
<circle cx="93.6" cy="49.7" r="2.32"/>
<circle cx="93.6" cy="43.8" r="2.32"/>
<circle cx="93.6" cy="55.7" r="2.32"/>
<circle cx="99.5" cy="55.7" r="2.32"/>
<circle cx="99.5" cy="49.7" r="2.32"/>
<circle cx="99.6" cy="43.8" r="2.32"/>
<circle cx="105.5" cy="55.7" r="2.32"/>
<circle cx="105.5" cy="49.7" r="2.32"/>
<circle cx="105.5" cy="43.8" r="2.32"/>
<circle cx="111.4" cy="55.7" r="2.32"/>
<circle cx="111.4" cy="49.7" r="2.32"/>
<circle cx="111.4" cy="43.8" r="2.32"/>
<circle cx="117.4" cy="55.7" r="2.32"/>
<circle cx="117.4" cy="49.7" r="2.32"/>
<circle cx="117.4" cy="43.8" r="2.32"/>
<circle cx="123.3" cy="43.8" r="2.32"/>
<circle cx="123.3" cy="55.7" r="2.32"/>
<circle cx="123.3" cy="49.7" r="2.32"/>
<circle cx="129.2" cy="49.7" r="2.32"/>
<circle cx="129.2" cy="43.8" r="2.32"/>
<circle cx="129.2" cy="55.7" r="2.32"/>
<circle cx="135.2" cy="49.7" r="2.32"/>
<circle cx="135.2" cy="55.7" r="2.32"/>
<circle cx="135.2" cy="43.8" r="2.32"/>
<circle cx="141.1" cy="43.8" r="2.32"/>
<circle cx="141.1" cy="55.7" r="2.32"/>
<circle cx="141.1" cy="49.7" r="2.32"/>
<circle cx="147.1" cy="49.7" r="2.32"/>
<circle cx="147.1" cy="43.8" r="2.32"/>
<circle cx="147.1" cy="55.7" r="2.32"/>
<circle cx="153" cy="49.7" r="2.32"/>
<circle cx="153" cy="55.7" r="2.32"/>
<circle cx="153" cy="43.8" r="2.32"/>
<circle cx="159" cy="49.7" r="2.32"/>
<circle cx="159" cy="43.8" r="2.32"/>
<circle cx="159" cy="55.7" r="2.32"/>
<circle cx="164.9" cy="43.8" r="2.32"/>
<circle cx="164.9" cy="55.7" r="2.32"/>
<circle cx="164.9" cy="49.7" r="2.32"/>
<circle cx="170.8" cy="49.7" r="2.32"/>
<circle cx="170.8" cy="55.7" r="2.32"/>
<circle cx="170.9" cy="43.8" r="2.32"/>
<circle cx="176.8" cy="43.8" r="2.32"/>
<circle cx="176.8" cy="49.7" r="2.32"/>
<circle cx="176.8" cy="55.7" r="2.32"/>
<circle cx="182.7" cy="43.8" r="2.32"/>
<circle cx="182.7" cy="55.7" r="2.32"/>
<circle cx="182.7" cy="49.7" r="2.32"/>
<circle cx="12.8" cy="238.6" r="2.32"/>
<circle cx="200" cy="238.6" r="2.32"/>
</g>
<g fill="none" stroke="#000" stroke-width=".2">
<path d="M99.6 38.5v4.7M97.2 40.9h4.7M97.2 52.7h4.7M99.5 50.3v4.8M7.5 61.3h2.3M8.6 60.1v2.3M18.9 64.6h3.4M20.6 62.9v3.4M84 68.6h2.1M85 67.5v2.1M92.8 71.6h3.4M94.5 69.9v3.4"/>
<path d="M105.9 71.3h2.1M106.9 70.3v2M110.2 71.3h2.7M111.5 70v2.7M156.6 70.6h2.1M157.6 69.6v2.1M158.2 78.8h2.2M159.3 77.7v2.1M165.9 71.2h3.3M167.6 69.5v3.4M180.1 74.3h2.9M181.6 72.9v2.8"/>
<path d="M189.7 74.3h2.7M191.1 72.9v2.8M196.2 61.8h2.3M197.4 60.7v2.3M26.2 90.6h3.4M27.9 88.9v3.4M42.5 90.6h3.4M44.2 88.9v3.4M97.9 88.6h4.6M100.2 86.3v4.6M112.4 96.8h2.8M113.8 95.4v2.7"/>
<path d="M115.3 84.8h2.7M116.7 83.4v2.7M125.2 96h2.4M125.3 82.6h2.3M126.4 94.9v2.3M126.5 81.4v2.3M134 89.6h2.4M135.2 88.4v2.4M149.6 98.2h2.4M150.8 97v2.4M159 87.8h3.4M160.7 86.1v3.4"/>
<path d="M180.3 85.9h2.6M180.8 98.7v4M181.6 84.5v2.7M189.7 85.9h2.7M191.1 84.5v2.7M198.3 99h3.8M200.2 97.1v3.7M28.3 119.6a12.9 12.9 0 0 1 13 13 12.9 12.9 0 0 1-13.1 12.8M28.6 119.6h-28v-88.5h211.6v214.8h-211.6v-22.2h28M72.8 119.9h2.8M74.2 118.5v2.8M97.6 114.1h2.7"/>
<path d="M98.9 112.7v2.7M105.3 114.1h2.1M106.3 113v2.1M115.1 114.2h3.5M116.9 112.5v3.4M158.6 117.7v4.8M178.8 100.7h4M190.5 115.1h3.3M192.2 113.4v3.4M205.7 119.2v2.8M80.5 124h2.9M82 122.6v2.8"/>
<path d="M90.1 133.9h2.7M91.4 132.6v2.7M107.4 128h3.6M109.1 126.2v3.6M118.7 124.6h2.7M120 123.2v2.7M123.6 124.6h2M124.6 123.5v2.1M156.3 120.1h4.7M180.1 133.9h2.8M181.5 132.5v2.8M193 131.8h3.3"/>
<path d="M194.6 130.2v3.2M204.3 120.6h2.8M204.3 131.4h2.7M205.7 130.1v2.7M28.6 145.3h-28v52.7h28M58.3 159.4v2.6M93.2 159v2.7M103.3 143.1h2.7M104.6 141.7v2.8M118.4 143.1h2.8M119.8 141.7v2.8M144.4 146.9h4"/>
<path d="M146.4 144.8v4M147 159v3.3M164.2 146.8h3.8M166.1 144.9v3.8M183.7 143.5h2.3M184.8 142.3v2.4M194.5 147.4h2.8M195.9 146v2.8M204.4 151.6h2.7M204.4 144h2.5M205.7 142.7v2.5M205.7 150.2v2.7"/>
<path d="M57 160.7h2.6M57.4 175.7h2.7M58.8 174.4v2.6M69.1 174.8h3.2M70.7 173.2v3.2M77.9 175.9h2.7M79.3 174.5v2.7M88.3 175.2h2.5M89.6 173.9v2.6M91.9 160.4h2.6M103.1 173.4h3.2M104.7 171.7v3.3"/>
<path d="M111.2 175.7h2.7M112.6 174.4v2.7M145.4 160.7h3.3M161 165.4h2.3M162.1 164.3v2.3M178.5 173.4h4M180.5 171.4v3.9M198.4 170.7h3.7M200.2 168.9v3.7M28.3 198a12.9 12.9 0 0 1 13 12.9 12.9 12.9 0 0 1-13.1 12.7M45.7 199.4h2.9M47.1 198v2.8"/>
<path d="M59.9 199.4h2.3M61 198.3v2.3M67.8 184.7h2.6M69.1 183.4v2.7M84.5 199.1h2.8M85.9 197.7v2.8M98.8 199.2h2.3M100 198v2.3M101 184.2h2.6M102.3 182.9v2.6M156.3 193.6h4.8M158.7 191.2v4.8"/>
<path d="M189.7 188.3h3.3M191.3 186.6v3.3M204.4 192.9h2.8M205.8 191.5v2.9M45.7 215.1h2.9M47.1 213.7v2.8M59.3 214.1h2.6M60.6 212.8v2.5M72.7 206.7h2.3M73.8 205.5v2.4M84.5 215.3h2.8M85.9 214v2.7"/>
<path d="M97.9 214.6h2.6M99.2 213.3v2.6M111.3 206.4h2.3M112.5 205.2v2.3M127.4 216.4h2.4M128.6 215.2v2.3M131.6 203.9h3.3M133.3 202.2v3.4M145.4 219.3v4.1M166.2 219.5v3.7M180 208.2h2.8M181.4 206.7v2.9"/>
<path d="M182.4 218.7h2.3M183.6 217.5v2.3M192.8 205.2h3.3M194.4 203.5v3.3M204.3 217.7h2.8M204.4 205.1h2.7M205.7 203.7v2.7M205.7 216.3v2.8M93.1 236.6h2M94.1 235.6v1.9M143.4 221.3h4M164.3 221.4h3.7"/>
<path d="M194.4 223.2h2.8M195.8 221.8v2.8M204.3 228.1h2.8M205.7 226.8v2.7"/>
</g>
<path d="M116 96.8h.1" fill="none" stroke="#808000" stroke-width=".2"/>
<use href="#words"/>
</svg>
